VERSION 5.7 ;
  NOWIREEXTENSIONATPIN ON ;
  DIVIDERCHAR "/" ;
  BUSBITCHARS "[]" ;
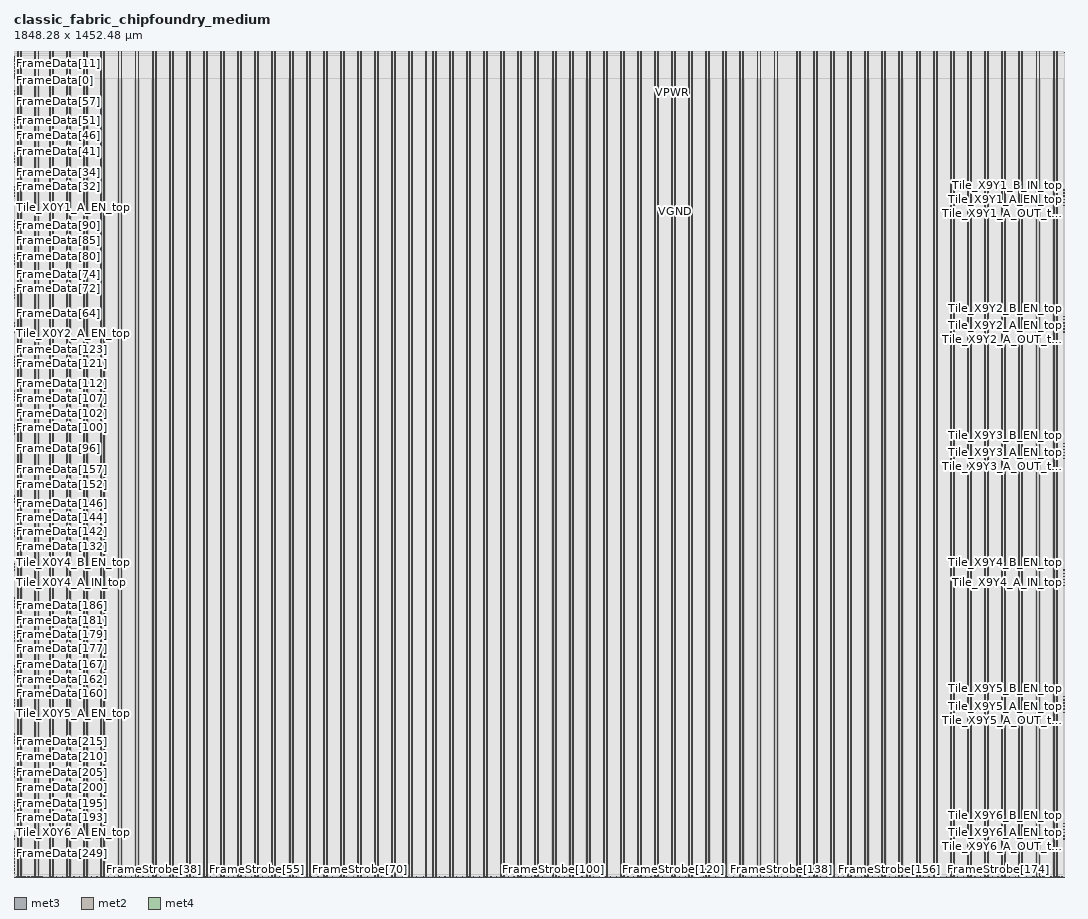
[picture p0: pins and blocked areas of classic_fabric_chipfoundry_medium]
MACRO classic_fabric_chipfoundry_medium
  CLASS BLOCK ;
  FOREIGN classic_fabric_chipfoundry_medium ;
  ORIGIN 0.000 0.000 ;
  SIZE 1848.280 BY 1452.480 ;
  PIN FrameData[0]
    DIRECTION INPUT ;
    USE SIGNAL ;
    ANTENNAGATEAREA 0.593700 ;
    ANTENNADIFFAREA 0.434700 ;
    PORT
      LAYER met3 ;
        RECT 0.000 1402.200 0.600 1402.800 ;
    END
  END FrameData[0]
  PIN FrameData[100]
    DIRECTION INPUT ;
    USE SIGNAL ;
    ANTENNAGATEAREA 0.795000 ;
    PORT
      LAYER met3 ;
        RECT 0.000 790.200 0.600 790.800 ;
    END
  END FrameData[100]
  PIN FrameData[101]
    DIRECTION INPUT ;
    USE SIGNAL ;
    ANTENNAGATEAREA 0.795000 ;
    PORT
      LAYER met3 ;
        RECT 0.000 795.640 0.600 796.240 ;
    END
  END FrameData[101]
  PIN FrameData[102]
    DIRECTION INPUT ;
    USE SIGNAL ;
    ANTENNAGATEAREA 0.795000 ;
    PORT
      LAYER met3 ;
        RECT 0.000 801.080 0.600 801.680 ;
    END
  END FrameData[102]
  PIN FrameData[103]
    DIRECTION INPUT ;
    USE SIGNAL ;
    ANTENNAGATEAREA 0.795000 ;
    PORT
      LAYER met3 ;
        RECT 0.000 806.520 0.600 807.120 ;
    END
  END FrameData[103]
  PIN FrameData[104]
    DIRECTION INPUT ;
    USE SIGNAL ;
    ANTENNAGATEAREA 0.795000 ;
    PORT
      LAYER met3 ;
        RECT 0.000 811.960 0.600 812.560 ;
    END
  END FrameData[104]
  PIN FrameData[105]
    DIRECTION INPUT ;
    USE SIGNAL ;
    ANTENNAGATEAREA 0.795000 ;
    PORT
      LAYER met3 ;
        RECT 0.000 817.400 0.600 818.000 ;
    END
  END FrameData[105]
  PIN FrameData[106]
    DIRECTION INPUT ;
    USE SIGNAL ;
    ANTENNAGATEAREA 0.795000 ;
    PORT
      LAYER met3 ;
        RECT 0.000 822.840 0.600 823.440 ;
    END
  END FrameData[106]
  PIN FrameData[107]
    DIRECTION INPUT ;
    USE SIGNAL ;
    ANTENNAGATEAREA 0.795000 ;
    PORT
      LAYER met3 ;
        RECT 0.000 828.280 0.600 828.880 ;
    END
  END FrameData[107]
  PIN FrameData[108]
    DIRECTION INPUT ;
    USE SIGNAL ;
    ANTENNAGATEAREA 0.795000 ;
    PORT
      LAYER met3 ;
        RECT 0.000 833.720 0.600 834.320 ;
    END
  END FrameData[108]
  PIN FrameData[109]
    DIRECTION INPUT ;
    USE SIGNAL ;
    ANTENNAGATEAREA 0.795000 ;
    PORT
      LAYER met3 ;
        RECT 0.000 839.160 0.600 839.760 ;
    END
  END FrameData[109]
  PIN FrameData[10]
    DIRECTION INPUT ;
    USE SIGNAL ;
    ANTENNAGATEAREA 0.159000 ;
    PORT
      LAYER met3 ;
        RECT 0.000 1415.800 0.600 1416.400 ;
    END
  END FrameData[10]
  PIN FrameData[110]
    DIRECTION INPUT ;
    USE SIGNAL ;
    ANTENNAGATEAREA 0.795000 ;
    PORT
      LAYER met3 ;
        RECT 0.000 844.600 0.600 845.200 ;
    END
  END FrameData[110]
  PIN FrameData[111]
    DIRECTION INPUT ;
    USE SIGNAL ;
    ANTENNAGATEAREA 0.795000 ;
    PORT
      LAYER met3 ;
        RECT 0.000 850.040 0.600 850.640 ;
    END
  END FrameData[111]
  PIN FrameData[112]
    DIRECTION INPUT ;
    USE SIGNAL ;
    ANTENNAGATEAREA 0.795000 ;
    PORT
      LAYER met3 ;
        RECT 0.000 855.480 0.600 856.080 ;
    END
  END FrameData[112]
  PIN FrameData[113]
    DIRECTION INPUT ;
    USE SIGNAL ;
    ANTENNAGATEAREA 0.795000 ;
    PORT
      LAYER met3 ;
        RECT 0.000 860.920 0.600 861.520 ;
    END
  END FrameData[113]
  PIN FrameData[114]
    DIRECTION INPUT ;
    USE SIGNAL ;
    ANTENNAGATEAREA 1.664400 ;
    ANTENNADIFFAREA 0.869400 ;
    PORT
      LAYER met3 ;
        RECT 0.000 866.360 0.600 866.960 ;
    END
  END FrameData[114]
  PIN FrameData[115]
    DIRECTION INPUT ;
    USE SIGNAL ;
    ANTENNAGATEAREA 0.795000 ;
    PORT
      LAYER met3 ;
        RECT 0.000 871.800 0.600 872.400 ;
    END
  END FrameData[115]
  PIN FrameData[116]
    DIRECTION INPUT ;
    USE SIGNAL ;
    ANTENNAGATEAREA 0.795000 ;
    PORT
      LAYER met3 ;
        RECT 0.000 877.240 0.600 877.840 ;
    END
  END FrameData[116]
  PIN FrameData[117]
    DIRECTION INPUT ;
    USE SIGNAL ;
    ANTENNAGATEAREA 0.795000 ;
    PORT
      LAYER met3 ;
        RECT 0.000 882.680 0.600 883.280 ;
    END
  END FrameData[117]
  PIN FrameData[118]
    DIRECTION INPUT ;
    USE SIGNAL ;
    ANTENNAGATEAREA 1.229700 ;
    ANTENNADIFFAREA 0.434700 ;
    PORT
      LAYER met3 ;
        RECT 0.000 888.120 0.600 888.720 ;
    END
  END FrameData[118]
  PIN FrameData[119]
    DIRECTION INPUT ;
    USE SIGNAL ;
    ANTENNAGATEAREA 0.795000 ;
    PORT
      LAYER met3 ;
        RECT 0.000 893.560 0.600 894.160 ;
    END
  END FrameData[119]
  PIN FrameData[11]
    DIRECTION INPUT ;
    USE SIGNAL ;
    ANTENNAGATEAREA 0.159000 ;
    PORT
      LAYER met3 ;
        RECT 0.000 1417.160 0.600 1417.760 ;
    END
  END FrameData[11]
  PIN FrameData[120]
    DIRECTION INPUT ;
    USE SIGNAL ;
    ANTENNAGATEAREA 0.795000 ;
    PORT
      LAYER met3 ;
        RECT 0.000 899.000 0.600 899.600 ;
    END
  END FrameData[120]
  PIN FrameData[121]
    DIRECTION INPUT ;
    USE SIGNAL ;
    ANTENNAGATEAREA 0.795000 ;
    PORT
      LAYER met3 ;
        RECT 0.000 904.440 0.600 905.040 ;
    END
  END FrameData[121]
  PIN FrameData[122]
    DIRECTION INPUT ;
    USE SIGNAL ;
    ANTENNAGATEAREA 0.795000 ;
    PORT
      LAYER met3 ;
        RECT 0.000 909.880 0.600 910.480 ;
    END
  END FrameData[122]
  PIN FrameData[123]
    DIRECTION INPUT ;
    USE SIGNAL ;
    ANTENNAGATEAREA 1.229700 ;
    ANTENNADIFFAREA 0.434700 ;
    PORT
      LAYER met3 ;
        RECT 0.000 915.320 0.600 915.920 ;
    END
  END FrameData[123]
  PIN FrameData[124]
    DIRECTION INPUT ;
    USE SIGNAL ;
    ANTENNAGATEAREA 0.795000 ;
    PORT
      LAYER met3 ;
        RECT 0.000 920.760 0.600 921.360 ;
    END
  END FrameData[124]
  PIN FrameData[125]
    DIRECTION INPUT ;
    USE SIGNAL ;
    ANTENNAGATEAREA 0.795000 ;
    PORT
      LAYER met3 ;
        RECT 0.000 926.200 0.600 926.800 ;
    END
  END FrameData[125]
  PIN FrameData[126]
    DIRECTION INPUT ;
    USE SIGNAL ;
    ANTENNAGATEAREA 0.795000 ;
    PORT
      LAYER met3 ;
        RECT 0.000 931.640 0.600 932.240 ;
    END
  END FrameData[126]
  PIN FrameData[127]
    DIRECTION INPUT ;
    USE SIGNAL ;
    ANTENNAGATEAREA 0.795000 ;
    PORT
      LAYER met3 ;
        RECT 0.000 937.080 0.600 937.680 ;
    END
  END FrameData[127]
  PIN FrameData[128]
    DIRECTION INPUT ;
    USE SIGNAL ;
    ANTENNAGATEAREA 0.636000 ;
    PORT
      LAYER met3 ;
        RECT 0.000 545.400 0.600 546.000 ;
    END
  END FrameData[128]
  PIN FrameData[129]
    DIRECTION INPUT ;
    USE SIGNAL ;
    ANTENNAGATEAREA 0.636000 ;
    PORT
      LAYER met3 ;
        RECT 0.000 550.840 0.600 551.440 ;
    END
  END FrameData[129]
  PIN FrameData[12]
    DIRECTION INPUT ;
    USE SIGNAL ;
    ANTENNAGATEAREA 0.159000 ;
    PORT
      LAYER met3 ;
        RECT 0.000 1418.520 0.600 1419.120 ;
    END
  END FrameData[12]
  PIN FrameData[130]
    DIRECTION INPUT ;
    USE SIGNAL ;
    ANTENNAGATEAREA 0.795000 ;
    PORT
      LAYER met3 ;
        RECT 0.000 556.280 0.600 556.880 ;
    END
  END FrameData[130]
  PIN FrameData[131]
    DIRECTION INPUT ;
    USE SIGNAL ;
    ANTENNAGATEAREA 0.795000 ;
    PORT
      LAYER met3 ;
        RECT 0.000 561.720 0.600 562.320 ;
    END
  END FrameData[131]
  PIN FrameData[132]
    DIRECTION INPUT ;
    USE SIGNAL ;
    ANTENNAGATEAREA 0.795000 ;
    PORT
      LAYER met3 ;
        RECT 0.000 567.160 0.600 567.760 ;
    END
  END FrameData[132]
  PIN FrameData[133]
    DIRECTION INPUT ;
    USE SIGNAL ;
    ANTENNAGATEAREA 0.795000 ;
    PORT
      LAYER met3 ;
        RECT 0.000 572.600 0.600 573.200 ;
    END
  END FrameData[133]
  PIN FrameData[134]
    DIRECTION INPUT ;
    USE SIGNAL ;
    ANTENNAGATEAREA 0.795000 ;
    PORT
      LAYER met3 ;
        RECT 0.000 578.040 0.600 578.640 ;
    END
  END FrameData[134]
  PIN FrameData[135]
    DIRECTION INPUT ;
    USE SIGNAL ;
    ANTENNAGATEAREA 0.795000 ;
    PORT
      LAYER met3 ;
        RECT 0.000 583.480 0.600 584.080 ;
    END
  END FrameData[135]
  PIN FrameData[136]
    DIRECTION INPUT ;
    USE SIGNAL ;
    ANTENNAGATEAREA 0.795000 ;
    PORT
      LAYER met3 ;
        RECT 0.000 588.920 0.600 589.520 ;
    END
  END FrameData[136]
  PIN FrameData[137]
    DIRECTION INPUT ;
    USE SIGNAL ;
    ANTENNAGATEAREA 0.795000 ;
    PORT
      LAYER met3 ;
        RECT 0.000 594.360 0.600 594.960 ;
    END
  END FrameData[137]
  PIN FrameData[138]
    DIRECTION INPUT ;
    USE SIGNAL ;
    ANTENNAGATEAREA 0.795000 ;
    PORT
      LAYER met3 ;
        RECT 0.000 599.800 0.600 600.400 ;
    END
  END FrameData[138]
  PIN FrameData[139]
    DIRECTION INPUT ;
    USE SIGNAL ;
    ANTENNAGATEAREA 0.795000 ;
    PORT
      LAYER met3 ;
        RECT 0.000 605.240 0.600 605.840 ;
    END
  END FrameData[139]
  PIN FrameData[13]
    DIRECTION INPUT ;
    USE SIGNAL ;
    ANTENNAGATEAREA 0.593700 ;
    ANTENNADIFFAREA 0.434700 ;
    PORT
      LAYER met3 ;
        RECT 0.000 1419.880 0.600 1420.480 ;
    END
  END FrameData[13]
  PIN FrameData[140]
    DIRECTION INPUT ;
    USE SIGNAL ;
    ANTENNAGATEAREA 0.795000 ;
    PORT
      LAYER met3 ;
        RECT 0.000 610.680 0.600 611.280 ;
    END
  END FrameData[140]
  PIN FrameData[141]
    DIRECTION INPUT ;
    USE SIGNAL ;
    ANTENNAGATEAREA 0.795000 ;
    PORT
      LAYER met3 ;
        RECT 0.000 616.120 0.600 616.720 ;
    END
  END FrameData[141]
  PIN FrameData[142]
    DIRECTION INPUT ;
    USE SIGNAL ;
    ANTENNAGATEAREA 0.795000 ;
    PORT
      LAYER met3 ;
        RECT 0.000 621.560 0.600 622.160 ;
    END
  END FrameData[142]
  PIN FrameData[143]
    DIRECTION INPUT ;
    USE SIGNAL ;
    ANTENNAGATEAREA 0.795000 ;
    PORT
      LAYER met3 ;
        RECT 0.000 627.000 0.600 627.600 ;
    END
  END FrameData[143]
  PIN FrameData[144]
    DIRECTION INPUT ;
    USE SIGNAL ;
    ANTENNAGATEAREA 0.795000 ;
    PORT
      LAYER met3 ;
        RECT 0.000 632.440 0.600 633.040 ;
    END
  END FrameData[144]
  PIN FrameData[145]
    DIRECTION INPUT ;
    USE SIGNAL ;
    ANTENNAGATEAREA 0.795000 ;
    PORT
      LAYER met3 ;
        RECT 0.000 637.880 0.600 638.480 ;
    END
  END FrameData[145]
  PIN FrameData[146]
    DIRECTION INPUT ;
    USE SIGNAL ;
    ANTENNAGATEAREA 1.664400 ;
    ANTENNADIFFAREA 0.869400 ;
    PORT
      LAYER met3 ;
        RECT 0.000 643.320 0.600 643.920 ;
    END
  END FrameData[146]
  PIN FrameData[147]
    DIRECTION INPUT ;
    USE SIGNAL ;
    ANTENNAGATEAREA 0.795000 ;
    PORT
      LAYER met3 ;
        RECT 0.000 648.760 0.600 649.360 ;
    END
  END FrameData[147]
  PIN FrameData[148]
    DIRECTION INPUT ;
    USE SIGNAL ;
    ANTENNAGATEAREA 0.795000 ;
    PORT
      LAYER met3 ;
        RECT 0.000 654.200 0.600 654.800 ;
    END
  END FrameData[148]
  PIN FrameData[149]
    DIRECTION INPUT ;
    USE SIGNAL ;
    ANTENNAGATEAREA 0.795000 ;
    PORT
      LAYER met3 ;
        RECT 0.000 659.640 0.600 660.240 ;
    END
  END FrameData[149]
  PIN FrameData[14]
    DIRECTION INPUT ;
    USE SIGNAL ;
    ANTENNAGATEAREA 0.593700 ;
    ANTENNADIFFAREA 0.434700 ;
    PORT
      LAYER met3 ;
        RECT 0.000 1421.240 0.600 1421.840 ;
    END
  END FrameData[14]
  PIN FrameData[150]
    DIRECTION INPUT ;
    USE SIGNAL ;
    ANTENNAGATEAREA 1.229700 ;
    ANTENNADIFFAREA 0.434700 ;
    PORT
      LAYER met3 ;
        RECT 0.000 665.080 0.600 665.680 ;
    END
  END FrameData[150]
  PIN FrameData[151]
    DIRECTION INPUT ;
    USE SIGNAL ;
    ANTENNAGATEAREA 0.795000 ;
    PORT
      LAYER met3 ;
        RECT 0.000 670.520 0.600 671.120 ;
    END
  END FrameData[151]
  PIN FrameData[152]
    DIRECTION INPUT ;
    USE SIGNAL ;
    ANTENNAGATEAREA 0.795000 ;
    PORT
      LAYER met3 ;
        RECT 0.000 675.960 0.600 676.560 ;
    END
  END FrameData[152]
  PIN FrameData[153]
    DIRECTION INPUT ;
    USE SIGNAL ;
    ANTENNAGATEAREA 0.795000 ;
    PORT
      LAYER met3 ;
        RECT 0.000 681.400 0.600 682.000 ;
    END
  END FrameData[153]
  PIN FrameData[154]
    DIRECTION INPUT ;
    USE SIGNAL ;
    ANTENNAGATEAREA 0.795000 ;
    PORT
      LAYER met3 ;
        RECT 0.000 686.840 0.600 687.440 ;
    END
  END FrameData[154]
  PIN FrameData[155]
    DIRECTION INPUT ;
    USE SIGNAL ;
    ANTENNAGATEAREA 1.229700 ;
    ANTENNADIFFAREA 0.434700 ;
    PORT
      LAYER met3 ;
        RECT 0.000 692.280 0.600 692.880 ;
    END
  END FrameData[155]
  PIN FrameData[156]
    DIRECTION INPUT ;
    USE SIGNAL ;
    ANTENNAGATEAREA 0.795000 ;
    PORT
      LAYER met3 ;
        RECT 0.000 697.720 0.600 698.320 ;
    END
  END FrameData[156]
  PIN FrameData[157]
    DIRECTION INPUT ;
    USE SIGNAL ;
    ANTENNAGATEAREA 0.795000 ;
    PORT
      LAYER met3 ;
        RECT 0.000 703.160 0.600 703.760 ;
    END
  END FrameData[157]
  PIN FrameData[158]
    DIRECTION INPUT ;
    USE SIGNAL ;
    ANTENNAGATEAREA 0.795000 ;
    PORT
      LAYER met3 ;
        RECT 0.000 708.600 0.600 709.200 ;
    END
  END FrameData[158]
  PIN FrameData[159]
    DIRECTION INPUT ;
    USE SIGNAL ;
    ANTENNAGATEAREA 0.795000 ;
    PORT
      LAYER met3 ;
        RECT 0.000 714.040 0.600 714.640 ;
    END
  END FrameData[159]
  PIN FrameData[15]
    DIRECTION INPUT ;
    USE SIGNAL ;
    ANTENNAGATEAREA 0.159000 ;
    PORT
      LAYER met3 ;
        RECT 0.000 1422.600 0.600 1423.200 ;
    END
  END FrameData[15]
  PIN FrameData[160]
    DIRECTION INPUT ;
    USE SIGNAL ;
    ANTENNAGATEAREA 0.636000 ;
    PORT
      LAYER met3 ;
        RECT 0.000 322.360 0.600 322.960 ;
    END
  END FrameData[160]
  PIN FrameData[161]
    DIRECTION INPUT ;
    USE SIGNAL ;
    ANTENNAGATEAREA 0.636000 ;
    PORT
      LAYER met3 ;
        RECT 0.000 327.800 0.600 328.400 ;
    END
  END FrameData[161]
  PIN FrameData[162]
    DIRECTION INPUT ;
    USE SIGNAL ;
    ANTENNAGATEAREA 0.795000 ;
    PORT
      LAYER met3 ;
        RECT 0.000 333.240 0.600 333.840 ;
    END
  END FrameData[162]
  PIN FrameData[163]
    DIRECTION INPUT ;
    USE SIGNAL ;
    ANTENNAGATEAREA 0.795000 ;
    PORT
      LAYER met3 ;
        RECT 0.000 338.680 0.600 339.280 ;
    END
  END FrameData[163]
  PIN FrameData[164]
    DIRECTION INPUT ;
    USE SIGNAL ;
    ANTENNAGATEAREA 0.795000 ;
    PORT
      LAYER met3 ;
        RECT 0.000 344.120 0.600 344.720 ;
    END
  END FrameData[164]
  PIN FrameData[165]
    DIRECTION INPUT ;
    USE SIGNAL ;
    ANTENNAGATEAREA 0.795000 ;
    PORT
      LAYER met3 ;
        RECT 0.000 349.560 0.600 350.160 ;
    END
  END FrameData[165]
  PIN FrameData[166]
    DIRECTION INPUT ;
    USE SIGNAL ;
    ANTENNAGATEAREA 0.795000 ;
    PORT
      LAYER met3 ;
        RECT 0.000 355.000 0.600 355.600 ;
    END
  END FrameData[166]
  PIN FrameData[167]
    DIRECTION INPUT ;
    USE SIGNAL ;
    ANTENNAGATEAREA 0.795000 ;
    PORT
      LAYER met3 ;
        RECT 0.000 360.440 0.600 361.040 ;
    END
  END FrameData[167]
  PIN FrameData[168]
    DIRECTION INPUT ;
    USE SIGNAL ;
    ANTENNAGATEAREA 0.795000 ;
    PORT
      LAYER met3 ;
        RECT 0.000 365.880 0.600 366.480 ;
    END
  END FrameData[168]
  PIN FrameData[169]
    DIRECTION INPUT ;
    USE SIGNAL ;
    ANTENNAGATEAREA 0.795000 ;
    PORT
      LAYER met3 ;
        RECT 0.000 371.320 0.600 371.920 ;
    END
  END FrameData[169]
  PIN FrameData[16]
    DIRECTION INPUT ;
    USE SIGNAL ;
    ANTENNAGATEAREA 0.593700 ;
    ANTENNADIFFAREA 0.434700 ;
    PORT
      LAYER met3 ;
        RECT 0.000 1423.960 0.600 1424.560 ;
    END
  END FrameData[16]
  PIN FrameData[170]
    DIRECTION INPUT ;
    USE SIGNAL ;
    ANTENNAGATEAREA 0.795000 ;
    PORT
      LAYER met3 ;
        RECT 0.000 376.760 0.600 377.360 ;
    END
  END FrameData[170]
  PIN FrameData[171]
    DIRECTION INPUT ;
    USE SIGNAL ;
    ANTENNAGATEAREA 0.795000 ;
    PORT
      LAYER met3 ;
        RECT 0.000 382.200 0.600 382.800 ;
    END
  END FrameData[171]
  PIN FrameData[172]
    DIRECTION INPUT ;
    USE SIGNAL ;
    ANTENNAGATEAREA 0.795000 ;
    PORT
      LAYER met3 ;
        RECT 0.000 387.640 0.600 388.240 ;
    END
  END FrameData[172]
  PIN FrameData[173]
    DIRECTION INPUT ;
    USE SIGNAL ;
    ANTENNAGATEAREA 0.795000 ;
    PORT
      LAYER met3 ;
        RECT 0.000 393.080 0.600 393.680 ;
    END
  END FrameData[173]
  PIN FrameData[174]
    DIRECTION INPUT ;
    USE SIGNAL ;
    ANTENNAGATEAREA 0.795000 ;
    PORT
      LAYER met3 ;
        RECT 0.000 398.520 0.600 399.120 ;
    END
  END FrameData[174]
  PIN FrameData[175]
    DIRECTION INPUT ;
    USE SIGNAL ;
    ANTENNAGATEAREA 0.795000 ;
    PORT
      LAYER met3 ;
        RECT 0.000 403.960 0.600 404.560 ;
    END
  END FrameData[175]
  PIN FrameData[176]
    DIRECTION INPUT ;
    USE SIGNAL ;
    ANTENNAGATEAREA 0.795000 ;
    PORT
      LAYER met3 ;
        RECT 0.000 409.400 0.600 410.000 ;
    END
  END FrameData[176]
  PIN FrameData[177]
    DIRECTION INPUT ;
    USE SIGNAL ;
    ANTENNAGATEAREA 0.795000 ;
    PORT
      LAYER met3 ;
        RECT 0.000 414.840 0.600 415.440 ;
    END
  END FrameData[177]
  PIN FrameData[178]
    DIRECTION INPUT ;
    USE SIGNAL ;
    ANTENNAGATEAREA 1.664400 ;
    ANTENNADIFFAREA 0.869400 ;
    PORT
      LAYER met3 ;
        RECT 0.000 420.280 0.600 420.880 ;
    END
  END FrameData[178]
  PIN FrameData[179]
    DIRECTION INPUT ;
    USE SIGNAL ;
    ANTENNAGATEAREA 0.795000 ;
    PORT
      LAYER met3 ;
        RECT 0.000 425.720 0.600 426.320 ;
    END
  END FrameData[179]
  PIN FrameData[17]
    DIRECTION INPUT ;
    USE SIGNAL ;
    ANTENNAGATEAREA 0.593700 ;
    ANTENNADIFFAREA 0.434700 ;
    PORT
      LAYER met3 ;
        RECT 0.000 1425.320 0.600 1425.920 ;
    END
  END FrameData[17]
  PIN FrameData[180]
    DIRECTION INPUT ;
    USE SIGNAL ;
    ANTENNAGATEAREA 0.795000 ;
    PORT
      LAYER met3 ;
        RECT 0.000 431.160 0.600 431.760 ;
    END
  END FrameData[180]
  PIN FrameData[181]
    DIRECTION INPUT ;
    USE SIGNAL ;
    ANTENNAGATEAREA 0.795000 ;
    PORT
      LAYER met3 ;
        RECT 0.000 436.600 0.600 437.200 ;
    END
  END FrameData[181]
  PIN FrameData[182]
    DIRECTION INPUT ;
    USE SIGNAL ;
    ANTENNAGATEAREA 1.229700 ;
    ANTENNADIFFAREA 0.434700 ;
    PORT
      LAYER met3 ;
        RECT 0.000 442.040 0.600 442.640 ;
    END
  END FrameData[182]
  PIN FrameData[183]
    DIRECTION INPUT ;
    USE SIGNAL ;
    ANTENNAGATEAREA 0.795000 ;
    PORT
      LAYER met3 ;
        RECT 0.000 447.480 0.600 448.080 ;
    END
  END FrameData[183]
  PIN FrameData[184]
    DIRECTION INPUT ;
    USE SIGNAL ;
    ANTENNAGATEAREA 0.795000 ;
    PORT
      LAYER met3 ;
        RECT 0.000 452.920 0.600 453.520 ;
    END
  END FrameData[184]
  PIN FrameData[185]
    DIRECTION INPUT ;
    USE SIGNAL ;
    ANTENNAGATEAREA 0.795000 ;
    PORT
      LAYER met3 ;
        RECT 0.000 458.360 0.600 458.960 ;
    END
  END FrameData[185]
  PIN FrameData[186]
    DIRECTION INPUT ;
    USE SIGNAL ;
    ANTENNAGATEAREA 0.795000 ;
    PORT
      LAYER met3 ;
        RECT 0.000 463.800 0.600 464.400 ;
    END
  END FrameData[186]
  PIN FrameData[187]
    DIRECTION INPUT ;
    USE SIGNAL ;
    ANTENNAGATEAREA 1.229700 ;
    ANTENNADIFFAREA 0.434700 ;
    PORT
      LAYER met3 ;
        RECT 0.000 469.240 0.600 469.840 ;
    END
  END FrameData[187]
  PIN FrameData[188]
    DIRECTION INPUT ;
    USE SIGNAL ;
    ANTENNAGATEAREA 0.795000 ;
    PORT
      LAYER met3 ;
        RECT 0.000 474.680 0.600 475.280 ;
    END
  END FrameData[188]
  PIN FrameData[189]
    DIRECTION INPUT ;
    USE SIGNAL ;
    ANTENNAGATEAREA 0.795000 ;
    PORT
      LAYER met3 ;
        RECT 0.000 480.120 0.600 480.720 ;
    END
  END FrameData[189]
  PIN FrameData[18]
    DIRECTION INPUT ;
    USE SIGNAL ;
    ANTENNAGATEAREA 0.159000 ;
    PORT
      LAYER met3 ;
        RECT 0.000 1426.680 0.600 1427.280 ;
    END
  END FrameData[18]
  PIN FrameData[190]
    DIRECTION INPUT ;
    USE SIGNAL ;
    ANTENNAGATEAREA 0.795000 ;
    PORT
      LAYER met3 ;
        RECT 0.000 485.560 0.600 486.160 ;
    END
  END FrameData[190]
  PIN FrameData[191]
    DIRECTION INPUT ;
    USE SIGNAL ;
    ANTENNAGATEAREA 0.795000 ;
    PORT
      LAYER met3 ;
        RECT 0.000 491.000 0.600 491.600 ;
    END
  END FrameData[191]
  PIN FrameData[192]
    DIRECTION INPUT ;
    USE SIGNAL ;
    ANTENNAGATEAREA 0.636000 ;
    PORT
      LAYER met3 ;
        RECT 0.000 99.320 0.600 99.920 ;
    END
  END FrameData[192]
  PIN FrameData[193]
    DIRECTION INPUT ;
    USE SIGNAL ;
    ANTENNAGATEAREA 0.636000 ;
    PORT
      LAYER met3 ;
        RECT 0.000 104.760 0.600 105.360 ;
    END
  END FrameData[193]
  PIN FrameData[194]
    DIRECTION INPUT ;
    USE SIGNAL ;
    ANTENNAGATEAREA 0.795000 ;
    PORT
      LAYER met3 ;
        RECT 0.000 110.200 0.600 110.800 ;
    END
  END FrameData[194]
  PIN FrameData[195]
    DIRECTION INPUT ;
    USE SIGNAL ;
    ANTENNAGATEAREA 0.795000 ;
    PORT
      LAYER met3 ;
        RECT 0.000 115.640 0.600 116.240 ;
    END
  END FrameData[195]
  PIN FrameData[196]
    DIRECTION INPUT ;
    USE SIGNAL ;
    ANTENNAGATEAREA 0.795000 ;
    PORT
      LAYER met3 ;
        RECT 0.000 121.080 0.600 121.680 ;
    END
  END FrameData[196]
  PIN FrameData[197]
    DIRECTION INPUT ;
    USE SIGNAL ;
    ANTENNAGATEAREA 0.795000 ;
    PORT
      LAYER met3 ;
        RECT 0.000 126.520 0.600 127.120 ;
    END
  END FrameData[197]
  PIN FrameData[198]
    DIRECTION INPUT ;
    USE SIGNAL ;
    ANTENNAGATEAREA 0.795000 ;
    PORT
      LAYER met3 ;
        RECT 0.000 131.960 0.600 132.560 ;
    END
  END FrameData[198]
  PIN FrameData[199]
    DIRECTION INPUT ;
    USE SIGNAL ;
    ANTENNAGATEAREA 0.795000 ;
    PORT
      LAYER met3 ;
        RECT 0.000 137.400 0.600 138.000 ;
    END
  END FrameData[199]
  PIN FrameData[19]
    DIRECTION INPUT ;
    USE SIGNAL ;
    ANTENNAGATEAREA 0.593700 ;
    ANTENNADIFFAREA 0.434700 ;
    PORT
      LAYER met3 ;
        RECT 0.000 1428.040 0.600 1428.640 ;
    END
  END FrameData[19]
  PIN FrameData[1]
    DIRECTION INPUT ;
    USE SIGNAL ;
    ANTENNAGATEAREA 0.593700 ;
    ANTENNADIFFAREA 0.434700 ;
    PORT
      LAYER met3 ;
        RECT 0.000 1403.560 0.600 1404.160 ;
    END
  END FrameData[1]
  PIN FrameData[200]
    DIRECTION INPUT ;
    USE SIGNAL ;
    ANTENNAGATEAREA 0.795000 ;
    PORT
      LAYER met3 ;
        RECT 0.000 142.840 0.600 143.440 ;
    END
  END FrameData[200]
  PIN FrameData[201]
    DIRECTION INPUT ;
    USE SIGNAL ;
    ANTENNAGATEAREA 0.795000 ;
    PORT
      LAYER met3 ;
        RECT 0.000 148.280 0.600 148.880 ;
    END
  END FrameData[201]
  PIN FrameData[202]
    DIRECTION INPUT ;
    USE SIGNAL ;
    ANTENNAGATEAREA 0.795000 ;
    PORT
      LAYER met3 ;
        RECT 0.000 153.720 0.600 154.320 ;
    END
  END FrameData[202]
  PIN FrameData[203]
    DIRECTION INPUT ;
    USE SIGNAL ;
    ANTENNAGATEAREA 0.795000 ;
    PORT
      LAYER met3 ;
        RECT 0.000 159.160 0.600 159.760 ;
    END
  END FrameData[203]
  PIN FrameData[204]
    DIRECTION INPUT ;
    USE SIGNAL ;
    ANTENNAGATEAREA 0.795000 ;
    PORT
      LAYER met3 ;
        RECT 0.000 164.600 0.600 165.200 ;
    END
  END FrameData[204]
  PIN FrameData[205]
    DIRECTION INPUT ;
    USE SIGNAL ;
    ANTENNAGATEAREA 0.795000 ;
    PORT
      LAYER met3 ;
        RECT 0.000 170.040 0.600 170.640 ;
    END
  END FrameData[205]
  PIN FrameData[206]
    DIRECTION INPUT ;
    USE SIGNAL ;
    ANTENNAGATEAREA 0.795000 ;
    PORT
      LAYER met3 ;
        RECT 0.000 175.480 0.600 176.080 ;
    END
  END FrameData[206]
  PIN FrameData[207]
    DIRECTION INPUT ;
    USE SIGNAL ;
    ANTENNAGATEAREA 0.795000 ;
    PORT
      LAYER met3 ;
        RECT 0.000 180.920 0.600 181.520 ;
    END
  END FrameData[207]
  PIN FrameData[208]
    DIRECTION INPUT ;
    USE SIGNAL ;
    ANTENNAGATEAREA 0.795000 ;
    PORT
      LAYER met3 ;
        RECT 0.000 186.360 0.600 186.960 ;
    END
  END FrameData[208]
  PIN FrameData[209]
    DIRECTION INPUT ;
    USE SIGNAL ;
    ANTENNAGATEAREA 0.795000 ;
    PORT
      LAYER met3 ;
        RECT 0.000 191.800 0.600 192.400 ;
    END
  END FrameData[209]
  PIN FrameData[20]
    DIRECTION INPUT ;
    USE SIGNAL ;
    ANTENNAGATEAREA 0.593700 ;
    ANTENNADIFFAREA 0.434700 ;
    PORT
      LAYER met3 ;
        RECT 0.000 1429.400 0.600 1430.000 ;
    END
  END FrameData[20]
  PIN FrameData[210]
    DIRECTION INPUT ;
    USE SIGNAL ;
    ANTENNAGATEAREA 1.664400 ;
    ANTENNADIFFAREA 0.869400 ;
    PORT
      LAYER met3 ;
        RECT 0.000 197.240 0.600 197.840 ;
    END
  END FrameData[210]
  PIN FrameData[211]
    DIRECTION INPUT ;
    USE SIGNAL ;
    ANTENNAGATEAREA 0.795000 ;
    PORT
      LAYER met3 ;
        RECT 0.000 202.680 0.600 203.280 ;
    END
  END FrameData[211]
  PIN FrameData[212]
    DIRECTION INPUT ;
    USE SIGNAL ;
    ANTENNAGATEAREA 0.795000 ;
    PORT
      LAYER met3 ;
        RECT 0.000 208.120 0.600 208.720 ;
    END
  END FrameData[212]
  PIN FrameData[213]
    DIRECTION INPUT ;
    USE SIGNAL ;
    ANTENNAGATEAREA 0.795000 ;
    PORT
      LAYER met3 ;
        RECT 0.000 213.560 0.600 214.160 ;
    END
  END FrameData[213]
  PIN FrameData[214]
    DIRECTION INPUT ;
    USE SIGNAL ;
    ANTENNAGATEAREA 1.229700 ;
    ANTENNADIFFAREA 0.434700 ;
    PORT
      LAYER met3 ;
        RECT 0.000 219.000 0.600 219.600 ;
    END
  END FrameData[214]
  PIN FrameData[215]
    DIRECTION INPUT ;
    USE SIGNAL ;
    ANTENNAGATEAREA 0.795000 ;
    PORT
      LAYER met3 ;
        RECT 0.000 224.440 0.600 225.040 ;
    END
  END FrameData[215]
  PIN FrameData[216]
    DIRECTION INPUT ;
    USE SIGNAL ;
    ANTENNAGATEAREA 0.795000 ;
    PORT
      LAYER met3 ;
        RECT 0.000 229.880 0.600 230.480 ;
    END
  END FrameData[216]
  PIN FrameData[217]
    DIRECTION INPUT ;
    USE SIGNAL ;
    ANTENNAGATEAREA 0.795000 ;
    PORT
      LAYER met3 ;
        RECT 0.000 235.320 0.600 235.920 ;
    END
  END FrameData[217]
  PIN FrameData[218]
    DIRECTION INPUT ;
    USE SIGNAL ;
    ANTENNAGATEAREA 0.795000 ;
    PORT
      LAYER met3 ;
        RECT 0.000 240.760 0.600 241.360 ;
    END
  END FrameData[218]
  PIN FrameData[219]
    DIRECTION INPUT ;
    USE SIGNAL ;
    ANTENNAGATEAREA 1.229700 ;
    ANTENNADIFFAREA 0.434700 ;
    PORT
      LAYER met3 ;
        RECT 0.000 246.200 0.600 246.800 ;
    END
  END FrameData[219]
  PIN FrameData[21]
    DIRECTION INPUT ;
    USE SIGNAL ;
    ANTENNAGATEAREA 0.159000 ;
    PORT
      LAYER met3 ;
        RECT 0.000 1430.760 0.600 1431.360 ;
    END
  END FrameData[21]
  PIN FrameData[220]
    DIRECTION INPUT ;
    USE SIGNAL ;
    ANTENNAGATEAREA 0.795000 ;
    PORT
      LAYER met3 ;
        RECT 0.000 251.640 0.600 252.240 ;
    END
  END FrameData[220]
  PIN FrameData[221]
    DIRECTION INPUT ;
    USE SIGNAL ;
    ANTENNAGATEAREA 0.795000 ;
    PORT
      LAYER met3 ;
        RECT 0.000 257.080 0.600 257.680 ;
    END
  END FrameData[221]
  PIN FrameData[222]
    DIRECTION INPUT ;
    USE SIGNAL ;
    ANTENNAGATEAREA 0.795000 ;
    PORT
      LAYER met3 ;
        RECT 0.000 262.520 0.600 263.120 ;
    END
  END FrameData[222]
  PIN FrameData[223]
    DIRECTION INPUT ;
    USE SIGNAL ;
    ANTENNAGATEAREA 0.795000 ;
    PORT
      LAYER met3 ;
        RECT 0.000 267.960 0.600 268.560 ;
    END
  END FrameData[223]
  PIN FrameData[224]
    DIRECTION INPUT ;
    USE SIGNAL ;
    ANTENNAGATEAREA 0.159000 ;
    PORT
      LAYER met3 ;
        RECT 0.000 6.840 0.600 7.440 ;
    END
  END FrameData[224]
  PIN FrameData[225]
    DIRECTION INPUT ;
    USE SIGNAL ;
    ANTENNAGATEAREA 0.159000 ;
    PORT
      LAYER met3 ;
        RECT 0.000 8.200 0.600 8.800 ;
    END
  END FrameData[225]
  PIN FrameData[226]
    DIRECTION INPUT ;
    USE SIGNAL ;
    ANTENNAGATEAREA 0.159000 ;
    PORT
      LAYER met3 ;
        RECT 0.000 9.560 0.600 10.160 ;
    END
  END FrameData[226]
  PIN FrameData[227]
    DIRECTION INPUT ;
    USE SIGNAL ;
    ANTENNAGATEAREA 0.593700 ;
    ANTENNADIFFAREA 0.434700 ;
    PORT
      LAYER met3 ;
        RECT 0.000 10.920 0.600 11.520 ;
    END
  END FrameData[227]
  PIN FrameData[228]
    DIRECTION INPUT ;
    USE SIGNAL ;
    ANTENNAGATEAREA 0.593700 ;
    ANTENNADIFFAREA 0.434700 ;
    PORT
      LAYER met3 ;
        RECT 0.000 12.280 0.600 12.880 ;
    END
  END FrameData[228]
  PIN FrameData[229]
    DIRECTION INPUT ;
    USE SIGNAL ;
    ANTENNAGATEAREA 0.593700 ;
    ANTENNADIFFAREA 0.434700 ;
    PORT
      LAYER met3 ;
        RECT 0.000 13.640 0.600 14.240 ;
    END
  END FrameData[229]
  PIN FrameData[22]
    DIRECTION INPUT ;
    USE SIGNAL ;
    ANTENNAGATEAREA 0.159000 ;
    PORT
      LAYER met3 ;
        RECT 0.000 1432.120 0.600 1432.720 ;
    END
  END FrameData[22]
  PIN FrameData[230]
    DIRECTION INPUT ;
    USE SIGNAL ;
    ANTENNAGATEAREA 0.159000 ;
    PORT
      LAYER met3 ;
        RECT 0.000 15.000 0.600 15.600 ;
    END
  END FrameData[230]
  PIN FrameData[231]
    DIRECTION INPUT ;
    USE SIGNAL ;
    ANTENNAGATEAREA 0.159000 ;
    PORT
      LAYER met3 ;
        RECT 0.000 16.360 0.600 16.960 ;
    END
  END FrameData[231]
  PIN FrameData[232]
    DIRECTION INPUT ;
    USE SIGNAL ;
    ANTENNAGATEAREA 0.593700 ;
    ANTENNADIFFAREA 0.434700 ;
    PORT
      LAYER met3 ;
        RECT 0.000 17.720 0.600 18.320 ;
    END
  END FrameData[232]
  PIN FrameData[233]
    DIRECTION INPUT ;
    USE SIGNAL ;
    ANTENNAGATEAREA 0.593700 ;
    ANTENNADIFFAREA 0.434700 ;
    PORT
      LAYER met3 ;
        RECT 0.000 19.080 0.600 19.680 ;
    END
  END FrameData[233]
  PIN FrameData[234]
    DIRECTION INPUT ;
    USE SIGNAL ;
    ANTENNAGATEAREA 0.159000 ;
    PORT
      LAYER met3 ;
        RECT 0.000 20.440 0.600 21.040 ;
    END
  END FrameData[234]
  PIN FrameData[235]
    DIRECTION INPUT ;
    USE SIGNAL ;
    ANTENNAGATEAREA 0.593700 ;
    ANTENNADIFFAREA 0.434700 ;
    PORT
      LAYER met3 ;
        RECT 0.000 21.800 0.600 22.400 ;
    END
  END FrameData[235]
  PIN FrameData[236]
    DIRECTION INPUT ;
    USE SIGNAL ;
    ANTENNAGATEAREA 0.318000 ;
    PORT
      LAYER met3 ;
        RECT 0.000 23.160 0.600 23.760 ;
    END
  END FrameData[236]
  PIN FrameData[237]
    DIRECTION INPUT ;
    USE SIGNAL ;
    ANTENNAGATEAREA 0.318000 ;
    PORT
      LAYER met3 ;
        RECT 0.000 24.520 0.600 25.120 ;
    END
  END FrameData[237]
  PIN FrameData[238]
    DIRECTION INPUT ;
    USE SIGNAL ;
    ANTENNAGATEAREA 0.318000 ;
    PORT
      LAYER met3 ;
        RECT 0.000 25.880 0.600 26.480 ;
    END
  END FrameData[238]
  PIN FrameData[239]
    DIRECTION INPUT ;
    USE SIGNAL ;
    ANTENNAGATEAREA 0.318000 ;
    PORT
      LAYER met3 ;
        RECT 0.000 27.240 0.600 27.840 ;
    END
  END FrameData[239]
  PIN FrameData[23]
    DIRECTION INPUT ;
    USE SIGNAL ;
    ANTENNAGATEAREA 0.159000 ;
    PORT
      LAYER met3 ;
        RECT 0.000 1433.480 0.600 1434.080 ;
    END
  END FrameData[23]
  PIN FrameData[240]
    DIRECTION INPUT ;
    USE SIGNAL ;
    ANTENNAGATEAREA 0.318000 ;
    PORT
      LAYER met3 ;
        RECT 0.000 28.600 0.600 29.200 ;
    END
  END FrameData[240]
  PIN FrameData[241]
    DIRECTION INPUT ;
    USE SIGNAL ;
    ANTENNAGATEAREA 0.318000 ;
    PORT
      LAYER met3 ;
        RECT 0.000 29.960 0.600 30.560 ;
    END
  END FrameData[241]
  PIN FrameData[242]
    DIRECTION INPUT ;
    USE SIGNAL ;
    ANTENNAGATEAREA 0.318000 ;
    PORT
      LAYER met3 ;
        RECT 0.000 31.320 0.600 31.920 ;
    END
  END FrameData[242]
  PIN FrameData[243]
    DIRECTION INPUT ;
    USE SIGNAL ;
    ANTENNAGATEAREA 0.318000 ;
    PORT
      LAYER met3 ;
        RECT 0.000 32.680 0.600 33.280 ;
    END
  END FrameData[243]
  PIN FrameData[244]
    DIRECTION INPUT ;
    USE SIGNAL ;
    ANTENNAGATEAREA 0.318000 ;
    PORT
      LAYER met3 ;
        RECT 0.000 34.040 0.600 34.640 ;
    END
  END FrameData[244]
  PIN FrameData[245]
    DIRECTION INPUT ;
    USE SIGNAL ;
    ANTENNAGATEAREA 0.318000 ;
    PORT
      LAYER met3 ;
        RECT 0.000 35.400 0.600 36.000 ;
    END
  END FrameData[245]
  PIN FrameData[246]
    DIRECTION INPUT ;
    USE SIGNAL ;
    ANTENNAGATEAREA 0.318000 ;
    PORT
      LAYER met3 ;
        RECT 0.000 36.760 0.600 37.360 ;
    END
  END FrameData[246]
  PIN FrameData[247]
    DIRECTION INPUT ;
    USE SIGNAL ;
    ANTENNAGATEAREA 0.318000 ;
    PORT
      LAYER met3 ;
        RECT 0.000 38.120 0.600 38.720 ;
    END
  END FrameData[247]
  PIN FrameData[248]
    DIRECTION INPUT ;
    USE SIGNAL ;
    ANTENNAGATEAREA 0.318000 ;
    PORT
      LAYER met3 ;
        RECT 0.000 39.480 0.600 40.080 ;
    END
  END FrameData[248]
  PIN FrameData[249]
    DIRECTION INPUT ;
    USE SIGNAL ;
    ANTENNAGATEAREA 0.318000 ;
    PORT
      LAYER met3 ;
        RECT 0.000 40.840 0.600 41.440 ;
    END
  END FrameData[249]
  PIN FrameData[24]
    DIRECTION INPUT ;
    USE SIGNAL ;
    ANTENNAGATEAREA 0.159000 ;
    PORT
      LAYER met3 ;
        RECT 0.000 1434.840 0.600 1435.440 ;
    END
  END FrameData[24]
  PIN FrameData[250]
    DIRECTION INPUT ;
    USE SIGNAL ;
    ANTENNAGATEAREA 0.318000 ;
    PORT
      LAYER met3 ;
        RECT 0.000 42.200 0.600 42.800 ;
    END
  END FrameData[250]
  PIN FrameData[251]
    DIRECTION INPUT ;
    USE SIGNAL ;
    ANTENNAGATEAREA 0.318000 ;
    PORT
      LAYER met3 ;
        RECT 0.000 43.560 0.600 44.160 ;
    END
  END FrameData[251]
  PIN FrameData[252]
    DIRECTION INPUT ;
    USE SIGNAL ;
    ANTENNAGATEAREA 0.318000 ;
    PORT
      LAYER met3 ;
        RECT 0.000 44.920 0.600 45.520 ;
    END
  END FrameData[252]
  PIN FrameData[253]
    DIRECTION INPUT ;
    USE SIGNAL ;
    ANTENNAGATEAREA 0.318000 ;
    PORT
      LAYER met3 ;
        RECT 0.000 46.280 0.600 46.880 ;
    END
  END FrameData[253]
  PIN FrameData[254]
    DIRECTION INPUT ;
    USE SIGNAL ;
    ANTENNAGATEAREA 0.318000 ;
    PORT
      LAYER met3 ;
        RECT 0.000 47.640 0.600 48.240 ;
    END
  END FrameData[254]
  PIN FrameData[255]
    DIRECTION INPUT ;
    USE SIGNAL ;
    ANTENNAGATEAREA 0.318000 ;
    PORT
      LAYER met3 ;
        RECT 0.000 49.000 0.600 49.600 ;
    END
  END FrameData[255]
  PIN FrameData[25]
    DIRECTION INPUT ;
    USE SIGNAL ;
    ANTENNAGATEAREA 0.159000 ;
    PORT
      LAYER met3 ;
        RECT 0.000 1436.200 0.600 1436.800 ;
    END
  END FrameData[25]
  PIN FrameData[26]
    DIRECTION INPUT ;
    USE SIGNAL ;
    ANTENNAGATEAREA 0.159000 ;
    PORT
      LAYER met3 ;
        RECT 0.000 1437.560 0.600 1438.160 ;
    END
  END FrameData[26]
  PIN FrameData[27]
    DIRECTION INPUT ;
    USE SIGNAL ;
    ANTENNAGATEAREA 0.159000 ;
    PORT
      LAYER met3 ;
        RECT 0.000 1438.920 0.600 1439.520 ;
    END
  END FrameData[27]
  PIN FrameData[28]
    DIRECTION INPUT ;
    USE SIGNAL ;
    ANTENNAGATEAREA 0.318000 ;
    PORT
      LAYER met3 ;
        RECT 0.000 1440.280 0.600 1440.880 ;
    END
  END FrameData[28]
  PIN FrameData[29]
    DIRECTION INPUT ;
    USE SIGNAL ;
    ANTENNAGATEAREA 0.318000 ;
    PORT
      LAYER met3 ;
        RECT 0.000 1441.640 0.600 1442.240 ;
    END
  END FrameData[29]
  PIN FrameData[2]
    DIRECTION INPUT ;
    USE SIGNAL ;
    ANTENNAGATEAREA 0.593700 ;
    ANTENNADIFFAREA 0.434700 ;
    PORT
      LAYER met3 ;
        RECT 0.000 1404.920 0.600 1405.520 ;
    END
  END FrameData[2]
  PIN FrameData[30]
    DIRECTION INPUT ;
    USE SIGNAL ;
    ANTENNAGATEAREA 0.318000 ;
    PORT
      LAYER met3 ;
        RECT 0.000 1443.000 0.600 1443.600 ;
    END
  END FrameData[30]
  PIN FrameData[31]
    DIRECTION INPUT ;
    USE SIGNAL ;
    ANTENNAGATEAREA 0.318000 ;
    PORT
      LAYER met3 ;
        RECT 0.000 1444.360 0.600 1444.960 ;
    END
  END FrameData[31]
  PIN FrameData[32]
    DIRECTION INPUT ;
    USE SIGNAL ;
    ANTENNAGATEAREA 0.636000 ;
    PORT
      LAYER met3 ;
        RECT 0.000 1214.520 0.600 1215.120 ;
    END
  END FrameData[32]
  PIN FrameData[33]
    DIRECTION INPUT ;
    USE SIGNAL ;
    ANTENNAGATEAREA 0.636000 ;
    PORT
      LAYER met3 ;
        RECT 0.000 1219.960 0.600 1220.560 ;
    END
  END FrameData[33]
  PIN FrameData[34]
    DIRECTION INPUT ;
    USE SIGNAL ;
    ANTENNAGATEAREA 0.795000 ;
    PORT
      LAYER met3 ;
        RECT 0.000 1225.400 0.600 1226.000 ;
    END
  END FrameData[34]
  PIN FrameData[35]
    DIRECTION INPUT ;
    USE SIGNAL ;
    ANTENNAGATEAREA 0.795000 ;
    PORT
      LAYER met3 ;
        RECT 0.000 1230.840 0.600 1231.440 ;
    END
  END FrameData[35]
  PIN FrameData[36]
    DIRECTION INPUT ;
    USE SIGNAL ;
    ANTENNAGATEAREA 0.795000 ;
    PORT
      LAYER met3 ;
        RECT 0.000 1236.280 0.600 1236.880 ;
    END
  END FrameData[36]
  PIN FrameData[37]
    DIRECTION INPUT ;
    USE SIGNAL ;
    ANTENNAGATEAREA 0.795000 ;
    PORT
      LAYER met3 ;
        RECT 0.000 1241.720 0.600 1242.320 ;
    END
  END FrameData[37]
  PIN FrameData[38]
    DIRECTION INPUT ;
    USE SIGNAL ;
    ANTENNAGATEAREA 0.795000 ;
    PORT
      LAYER met3 ;
        RECT 0.000 1247.160 0.600 1247.760 ;
    END
  END FrameData[38]
  PIN FrameData[39]
    DIRECTION INPUT ;
    USE SIGNAL ;
    ANTENNAGATEAREA 0.795000 ;
    PORT
      LAYER met3 ;
        RECT 0.000 1252.600 0.600 1253.200 ;
    END
  END FrameData[39]
  PIN FrameData[3]
    DIRECTION INPUT ;
    USE SIGNAL ;
    ANTENNAGATEAREA 0.593700 ;
    ANTENNADIFFAREA 0.434700 ;
    PORT
      LAYER met3 ;
        RECT 0.000 1406.280 0.600 1406.880 ;
    END
  END FrameData[3]
  PIN FrameData[40]
    DIRECTION INPUT ;
    USE SIGNAL ;
    ANTENNAGATEAREA 0.795000 ;
    PORT
      LAYER met3 ;
        RECT 0.000 1258.040 0.600 1258.640 ;
    END
  END FrameData[40]
  PIN FrameData[41]
    DIRECTION INPUT ;
    USE SIGNAL ;
    ANTENNAGATEAREA 0.795000 ;
    PORT
      LAYER met3 ;
        RECT 0.000 1263.480 0.600 1264.080 ;
    END
  END FrameData[41]
  PIN FrameData[42]
    DIRECTION INPUT ;
    USE SIGNAL ;
    ANTENNAGATEAREA 0.795000 ;
    PORT
      LAYER met3 ;
        RECT 0.000 1268.920 0.600 1269.520 ;
    END
  END FrameData[42]
  PIN FrameData[43]
    DIRECTION INPUT ;
    USE SIGNAL ;
    ANTENNAGATEAREA 0.795000 ;
    PORT
      LAYER met3 ;
        RECT 0.000 1274.360 0.600 1274.960 ;
    END
  END FrameData[43]
  PIN FrameData[44]
    DIRECTION INPUT ;
    USE SIGNAL ;
    ANTENNAGATEAREA 0.795000 ;
    PORT
      LAYER met3 ;
        RECT 0.000 1279.800 0.600 1280.400 ;
    END
  END FrameData[44]
  PIN FrameData[45]
    DIRECTION INPUT ;
    USE SIGNAL ;
    ANTENNAGATEAREA 0.795000 ;
    PORT
      LAYER met3 ;
        RECT 0.000 1285.240 0.600 1285.840 ;
    END
  END FrameData[45]
  PIN FrameData[46]
    DIRECTION INPUT ;
    USE SIGNAL ;
    ANTENNAGATEAREA 0.795000 ;
    PORT
      LAYER met3 ;
        RECT 0.000 1290.680 0.600 1291.280 ;
    END
  END FrameData[46]
  PIN FrameData[47]
    DIRECTION INPUT ;
    USE SIGNAL ;
    ANTENNAGATEAREA 0.795000 ;
    PORT
      LAYER met3 ;
        RECT 0.000 1296.120 0.600 1296.720 ;
    END
  END FrameData[47]
  PIN FrameData[48]
    DIRECTION INPUT ;
    USE SIGNAL ;
    ANTENNAGATEAREA 0.795000 ;
    PORT
      LAYER met3 ;
        RECT 0.000 1301.560 0.600 1302.160 ;
    END
  END FrameData[48]
  PIN FrameData[49]
    DIRECTION INPUT ;
    USE SIGNAL ;
    ANTENNAGATEAREA 0.795000 ;
    PORT
      LAYER met3 ;
        RECT 0.000 1307.000 0.600 1307.600 ;
    END
  END FrameData[49]
  PIN FrameData[4]
    DIRECTION INPUT ;
    USE SIGNAL ;
    ANTENNAGATEAREA 0.159000 ;
    PORT
      LAYER met3 ;
        RECT 0.000 1407.640 0.600 1408.240 ;
    END
  END FrameData[4]
  PIN FrameData[50]
    DIRECTION INPUT ;
    USE SIGNAL ;
    ANTENNAGATEAREA 1.664400 ;
    ANTENNADIFFAREA 0.869400 ;
    PORT
      LAYER met3 ;
        RECT 0.000 1312.440 0.600 1313.040 ;
    END
  END FrameData[50]
  PIN FrameData[51]
    DIRECTION INPUT ;
    USE SIGNAL ;
    ANTENNAGATEAREA 0.795000 ;
    PORT
      LAYER met3 ;
        RECT 0.000 1317.880 0.600 1318.480 ;
    END
  END FrameData[51]
  PIN FrameData[52]
    DIRECTION INPUT ;
    USE SIGNAL ;
    ANTENNAGATEAREA 0.795000 ;
    PORT
      LAYER met3 ;
        RECT 0.000 1323.320 0.600 1323.920 ;
    END
  END FrameData[52]
  PIN FrameData[53]
    DIRECTION INPUT ;
    USE SIGNAL ;
    ANTENNAGATEAREA 0.795000 ;
    PORT
      LAYER met3 ;
        RECT 0.000 1328.760 0.600 1329.360 ;
    END
  END FrameData[53]
  PIN FrameData[54]
    DIRECTION INPUT ;
    USE SIGNAL ;
    ANTENNAGATEAREA 1.229700 ;
    ANTENNADIFFAREA 0.434700 ;
    PORT
      LAYER met3 ;
        RECT 0.000 1334.200 0.600 1334.800 ;
    END
  END FrameData[54]
  PIN FrameData[55]
    DIRECTION INPUT ;
    USE SIGNAL ;
    ANTENNAGATEAREA 0.795000 ;
    PORT
      LAYER met3 ;
        RECT 0.000 1339.640 0.600 1340.240 ;
    END
  END FrameData[55]
  PIN FrameData[56]
    DIRECTION INPUT ;
    USE SIGNAL ;
    ANTENNAGATEAREA 0.795000 ;
    PORT
      LAYER met3 ;
        RECT 0.000 1345.080 0.600 1345.680 ;
    END
  END FrameData[56]
  PIN FrameData[57]
    DIRECTION INPUT ;
    USE SIGNAL ;
    ANTENNAGATEAREA 0.795000 ;
    PORT
      LAYER met3 ;
        RECT 0.000 1350.520 0.600 1351.120 ;
    END
  END FrameData[57]
  PIN FrameData[58]
    DIRECTION INPUT ;
    USE SIGNAL ;
    ANTENNAGATEAREA 0.795000 ;
    PORT
      LAYER met3 ;
        RECT 0.000 1355.960 0.600 1356.560 ;
    END
  END FrameData[58]
  PIN FrameData[59]
    DIRECTION INPUT ;
    USE SIGNAL ;
    ANTENNAGATEAREA 1.229700 ;
    ANTENNADIFFAREA 0.434700 ;
    PORT
      LAYER met3 ;
        RECT 0.000 1361.400 0.600 1362.000 ;
    END
  END FrameData[59]
  PIN FrameData[5]
    DIRECTION INPUT ;
    USE SIGNAL ;
    ANTENNAGATEAREA 0.159000 ;
    PORT
      LAYER met3 ;
        RECT 0.000 1409.000 0.600 1409.600 ;
    END
  END FrameData[5]
  PIN FrameData[60]
    DIRECTION INPUT ;
    USE SIGNAL ;
    ANTENNAGATEAREA 0.795000 ;
    PORT
      LAYER met3 ;
        RECT 0.000 1366.840 0.600 1367.440 ;
    END
  END FrameData[60]
  PIN FrameData[61]
    DIRECTION INPUT ;
    USE SIGNAL ;
    ANTENNAGATEAREA 0.795000 ;
    PORT
      LAYER met3 ;
        RECT 0.000 1372.280 0.600 1372.880 ;
    END
  END FrameData[61]
  PIN FrameData[62]
    DIRECTION INPUT ;
    USE SIGNAL ;
    ANTENNAGATEAREA 0.795000 ;
    PORT
      LAYER met3 ;
        RECT 0.000 1377.720 0.600 1378.320 ;
    END
  END FrameData[62]
  PIN FrameData[63]
    DIRECTION INPUT ;
    USE SIGNAL ;
    ANTENNAGATEAREA 0.795000 ;
    PORT
      LAYER met3 ;
        RECT 0.000 1383.160 0.600 1383.760 ;
    END
  END FrameData[63]
  PIN FrameData[64]
    DIRECTION INPUT ;
    USE SIGNAL ;
    ANTENNAGATEAREA 0.636000 ;
    PORT
      LAYER met3 ;
        RECT 0.000 991.480 0.600 992.080 ;
    END
  END FrameData[64]
  PIN FrameData[65]
    DIRECTION INPUT ;
    USE SIGNAL ;
    ANTENNAGATEAREA 0.636000 ;
    PORT
      LAYER met3 ;
        RECT 0.000 996.920 0.600 997.520 ;
    END
  END FrameData[65]
  PIN FrameData[66]
    DIRECTION INPUT ;
    USE SIGNAL ;
    ANTENNAGATEAREA 0.795000 ;
    PORT
      LAYER met3 ;
        RECT 0.000 1002.360 0.600 1002.960 ;
    END
  END FrameData[66]
  PIN FrameData[67]
    DIRECTION INPUT ;
    USE SIGNAL ;
    ANTENNAGATEAREA 0.795000 ;
    PORT
      LAYER met3 ;
        RECT 0.000 1007.800 0.600 1008.400 ;
    END
  END FrameData[67]
  PIN FrameData[68]
    DIRECTION INPUT ;
    USE SIGNAL ;
    ANTENNAGATEAREA 0.795000 ;
    PORT
      LAYER met3 ;
        RECT 0.000 1013.240 0.600 1013.840 ;
    END
  END FrameData[68]
  PIN FrameData[69]
    DIRECTION INPUT ;
    USE SIGNAL ;
    ANTENNAGATEAREA 0.795000 ;
    PORT
      LAYER met3 ;
        RECT 0.000 1018.680 0.600 1019.280 ;
    END
  END FrameData[69]
  PIN FrameData[6]
    DIRECTION INPUT ;
    USE SIGNAL ;
    ANTENNAGATEAREA 0.159000 ;
    PORT
      LAYER met3 ;
        RECT 0.000 1410.360 0.600 1410.960 ;
    END
  END FrameData[6]
  PIN FrameData[70]
    DIRECTION INPUT ;
    USE SIGNAL ;
    ANTENNAGATEAREA 0.795000 ;
    PORT
      LAYER met3 ;
        RECT 0.000 1024.120 0.600 1024.720 ;
    END
  END FrameData[70]
  PIN FrameData[71]
    DIRECTION INPUT ;
    USE SIGNAL ;
    ANTENNAGATEAREA 0.795000 ;
    PORT
      LAYER met3 ;
        RECT 0.000 1029.560 0.600 1030.160 ;
    END
  END FrameData[71]
  PIN FrameData[72]
    DIRECTION INPUT ;
    USE SIGNAL ;
    ANTENNAGATEAREA 0.795000 ;
    PORT
      LAYER met3 ;
        RECT 0.000 1035.000 0.600 1035.600 ;
    END
  END FrameData[72]
  PIN FrameData[73]
    DIRECTION INPUT ;
    USE SIGNAL ;
    ANTENNAGATEAREA 0.795000 ;
    PORT
      LAYER met3 ;
        RECT 0.000 1040.440 0.600 1041.040 ;
    END
  END FrameData[73]
  PIN FrameData[74]
    DIRECTION INPUT ;
    USE SIGNAL ;
    ANTENNAGATEAREA 0.795000 ;
    PORT
      LAYER met3 ;
        RECT 0.000 1045.880 0.600 1046.480 ;
    END
  END FrameData[74]
  PIN FrameData[75]
    DIRECTION INPUT ;
    USE SIGNAL ;
    ANTENNAGATEAREA 0.795000 ;
    PORT
      LAYER met3 ;
        RECT 0.000 1051.320 0.600 1051.920 ;
    END
  END FrameData[75]
  PIN FrameData[76]
    DIRECTION INPUT ;
    USE SIGNAL ;
    ANTENNAGATEAREA 0.795000 ;
    PORT
      LAYER met3 ;
        RECT 0.000 1056.760 0.600 1057.360 ;
    END
  END FrameData[76]
  PIN FrameData[77]
    DIRECTION INPUT ;
    USE SIGNAL ;
    ANTENNAGATEAREA 0.795000 ;
    PORT
      LAYER met3 ;
        RECT 0.000 1062.200 0.600 1062.800 ;
    END
  END FrameData[77]
  PIN FrameData[78]
    DIRECTION INPUT ;
    USE SIGNAL ;
    ANTENNAGATEAREA 0.795000 ;
    PORT
      LAYER met3 ;
        RECT 0.000 1067.640 0.600 1068.240 ;
    END
  END FrameData[78]
  PIN FrameData[79]
    DIRECTION INPUT ;
    USE SIGNAL ;
    ANTENNAGATEAREA 0.795000 ;
    PORT
      LAYER met3 ;
        RECT 0.000 1073.080 0.600 1073.680 ;
    END
  END FrameData[79]
  PIN FrameData[7]
    DIRECTION INPUT ;
    USE SIGNAL ;
    ANTENNAGATEAREA 0.593700 ;
    ANTENNADIFFAREA 0.434700 ;
    PORT
      LAYER met3 ;
        RECT 0.000 1411.720 0.600 1412.320 ;
    END
  END FrameData[7]
  PIN FrameData[80]
    DIRECTION INPUT ;
    USE SIGNAL ;
    ANTENNAGATEAREA 0.795000 ;
    PORT
      LAYER met3 ;
        RECT 0.000 1078.520 0.600 1079.120 ;
    END
  END FrameData[80]
  PIN FrameData[81]
    DIRECTION INPUT ;
    USE SIGNAL ;
    ANTENNAGATEAREA 0.795000 ;
    PORT
      LAYER met3 ;
        RECT 0.000 1083.960 0.600 1084.560 ;
    END
  END FrameData[81]
  PIN FrameData[82]
    DIRECTION INPUT ;
    USE SIGNAL ;
    ANTENNAGATEAREA 1.664400 ;
    ANTENNADIFFAREA 0.869400 ;
    PORT
      LAYER met3 ;
        RECT 0.000 1089.400 0.600 1090.000 ;
    END
  END FrameData[82]
  PIN FrameData[83]
    DIRECTION INPUT ;
    USE SIGNAL ;
    ANTENNAGATEAREA 0.795000 ;
    PORT
      LAYER met3 ;
        RECT 0.000 1094.840 0.600 1095.440 ;
    END
  END FrameData[83]
  PIN FrameData[84]
    DIRECTION INPUT ;
    USE SIGNAL ;
    ANTENNAGATEAREA 0.795000 ;
    PORT
      LAYER met3 ;
        RECT 0.000 1100.280 0.600 1100.880 ;
    END
  END FrameData[84]
  PIN FrameData[85]
    DIRECTION INPUT ;
    USE SIGNAL ;
    ANTENNAGATEAREA 0.795000 ;
    PORT
      LAYER met3 ;
        RECT 0.000 1105.720 0.600 1106.320 ;
    END
  END FrameData[85]
  PIN FrameData[86]
    DIRECTION INPUT ;
    USE SIGNAL ;
    ANTENNAGATEAREA 1.229700 ;
    ANTENNADIFFAREA 0.434700 ;
    PORT
      LAYER met3 ;
        RECT 0.000 1111.160 0.600 1111.760 ;
    END
  END FrameData[86]
  PIN FrameData[87]
    DIRECTION INPUT ;
    USE SIGNAL ;
    ANTENNAGATEAREA 0.795000 ;
    PORT
      LAYER met3 ;
        RECT 0.000 1116.600 0.600 1117.200 ;
    END
  END FrameData[87]
  PIN FrameData[88]
    DIRECTION INPUT ;
    USE SIGNAL ;
    ANTENNAGATEAREA 0.795000 ;
    PORT
      LAYER met3 ;
        RECT 0.000 1122.040 0.600 1122.640 ;
    END
  END FrameData[88]
  PIN FrameData[89]
    DIRECTION INPUT ;
    USE SIGNAL ;
    ANTENNAGATEAREA 0.795000 ;
    PORT
      LAYER met3 ;
        RECT 0.000 1127.480 0.600 1128.080 ;
    END
  END FrameData[89]
  PIN FrameData[8]
    DIRECTION INPUT ;
    USE SIGNAL ;
    ANTENNAGATEAREA 0.159000 ;
    PORT
      LAYER met3 ;
        RECT 0.000 1413.080 0.600 1413.680 ;
    END
  END FrameData[8]
  PIN FrameData[90]
    DIRECTION INPUT ;
    USE SIGNAL ;
    ANTENNAGATEAREA 0.795000 ;
    PORT
      LAYER met3 ;
        RECT 0.000 1132.920 0.600 1133.520 ;
    END
  END FrameData[90]
  PIN FrameData[91]
    DIRECTION INPUT ;
    USE SIGNAL ;
    ANTENNAGATEAREA 1.229700 ;
    ANTENNADIFFAREA 0.434700 ;
    PORT
      LAYER met3 ;
        RECT 0.000 1138.360 0.600 1138.960 ;
    END
  END FrameData[91]
  PIN FrameData[92]
    DIRECTION INPUT ;
    USE SIGNAL ;
    ANTENNAGATEAREA 0.795000 ;
    PORT
      LAYER met3 ;
        RECT 0.000 1143.800 0.600 1144.400 ;
    END
  END FrameData[92]
  PIN FrameData[93]
    DIRECTION INPUT ;
    USE SIGNAL ;
    ANTENNAGATEAREA 0.795000 ;
    PORT
      LAYER met3 ;
        RECT 0.000 1149.240 0.600 1149.840 ;
    END
  END FrameData[93]
  PIN FrameData[94]
    DIRECTION INPUT ;
    USE SIGNAL ;
    ANTENNAGATEAREA 0.795000 ;
    PORT
      LAYER met3 ;
        RECT 0.000 1154.680 0.600 1155.280 ;
    END
  END FrameData[94]
  PIN FrameData[95]
    DIRECTION INPUT ;
    USE SIGNAL ;
    ANTENNAGATEAREA 0.795000 ;
    PORT
      LAYER met3 ;
        RECT 0.000 1160.120 0.600 1160.720 ;
    END
  END FrameData[95]
  PIN FrameData[96]
    DIRECTION INPUT ;
    USE SIGNAL ;
    ANTENNAGATEAREA 0.636000 ;
    PORT
      LAYER met3 ;
        RECT 0.000 768.440 0.600 769.040 ;
    END
  END FrameData[96]
  PIN FrameData[97]
    DIRECTION INPUT ;
    USE SIGNAL ;
    ANTENNAGATEAREA 0.636000 ;
    PORT
      LAYER met3 ;
        RECT 0.000 773.880 0.600 774.480 ;
    END
  END FrameData[97]
  PIN FrameData[98]
    DIRECTION INPUT ;
    USE SIGNAL ;
    ANTENNAGATEAREA 0.795000 ;
    PORT
      LAYER met3 ;
        RECT 0.000 779.320 0.600 779.920 ;
    END
  END FrameData[98]
  PIN FrameData[99]
    DIRECTION INPUT ;
    USE SIGNAL ;
    ANTENNAGATEAREA 0.795000 ;
    PORT
      LAYER met3 ;
        RECT 0.000 784.760 0.600 785.360 ;
    END
  END FrameData[99]
  PIN FrameData[9]
    DIRECTION INPUT ;
    USE SIGNAL ;
    ANTENNAGATEAREA 0.159000 ;
    PORT
      LAYER met3 ;
        RECT 0.000 1414.440 0.600 1415.040 ;
    END
  END FrameData[9]
  PIN FrameStrobe[0]
    DIRECTION INPUT ;
    USE SIGNAL ;
    ANTENNAGATEAREA 3.339000 ;
    PORT
      LAYER met2 ;
        RECT 6.990 0.000 7.270 0.280 ;
    END
  END FrameStrobe[0]
  PIN FrameStrobe[100]
    DIRECTION INPUT ;
    USE SIGNAL ;
    ANTENNAGATEAREA 1.431000 ;
    PORT
      LAYER met2 ;
        RECT 949.070 0.000 949.350 0.280 ;
    END
  END FrameStrobe[100]
  PIN FrameStrobe[101]
    DIRECTION INPUT ;
    USE SIGNAL ;
    ANTENNAGATEAREA 0.593700 ;
    ANTENNADIFFAREA 0.434700 ;
    PORT
      LAYER met2 ;
        RECT 959.190 0.000 959.470 0.280 ;
    END
  END FrameStrobe[101]
  PIN FrameStrobe[102]
    DIRECTION INPUT ;
    USE SIGNAL ;
    ANTENNAGATEAREA 0.593700 ;
    ANTENNADIFFAREA 0.434700 ;
    PORT
      LAYER met2 ;
        RECT 969.310 0.000 969.590 0.280 ;
    END
  END FrameStrobe[102]
  PIN FrameStrobe[103]
    DIRECTION INPUT ;
    USE SIGNAL ;
    ANTENNAGATEAREA 0.159000 ;
    PORT
      LAYER met2 ;
        RECT 979.430 0.000 979.710 0.280 ;
    END
  END FrameStrobe[103]
  PIN FrameStrobe[104]
    DIRECTION INPUT ;
    USE SIGNAL ;
    ANTENNAGATEAREA 0.159000 ;
    PORT
      LAYER met2 ;
        RECT 989.550 0.000 989.830 0.280 ;
    END
  END FrameStrobe[104]
  PIN FrameStrobe[105]
    DIRECTION INPUT ;
    USE SIGNAL ;
    ANTENNAGATEAREA 0.159000 ;
    PORT
      LAYER met2 ;
        RECT 999.670 0.000 999.950 0.280 ;
    END
  END FrameStrobe[105]
  PIN FrameStrobe[106]
    DIRECTION INPUT ;
    USE SIGNAL ;
    ANTENNAGATEAREA 0.159000 ;
    PORT
      LAYER met2 ;
        RECT 1009.790 0.000 1010.070 0.280 ;
    END
  END FrameStrobe[106]
  PIN FrameStrobe[107]
    DIRECTION INPUT ;
    USE SIGNAL ;
    ANTENNAGATEAREA 0.159000 ;
    PORT
      LAYER met2 ;
        RECT 1019.910 0.000 1020.190 0.280 ;
    END
  END FrameStrobe[107]
  PIN FrameStrobe[108]
    DIRECTION INPUT ;
    USE SIGNAL ;
    ANTENNAGATEAREA 0.159000 ;
    PORT
      LAYER met2 ;
        RECT 1030.030 0.000 1030.310 0.280 ;
    END
  END FrameStrobe[108]
  PIN FrameStrobe[109]
    DIRECTION INPUT ;
    USE SIGNAL ;
    ANTENNAGATEAREA 0.159000 ;
    PORT
      LAYER met2 ;
        RECT 1040.150 0.000 1040.430 0.280 ;
    END
  END FrameStrobe[109]
  PIN FrameStrobe[10]
    DIRECTION INPUT ;
    USE SIGNAL ;
    ANTENNAGATEAREA 0.159000 ;
    PORT
      LAYER met2 ;
        RECT 29.990 0.000 30.270 0.280 ;
    END
  END FrameStrobe[10]
  PIN FrameStrobe[110]
    DIRECTION INPUT ;
    USE SIGNAL ;
    ANTENNAGATEAREA 0.159000 ;
    PORT
      LAYER met2 ;
        RECT 1050.270 0.000 1050.550 0.280 ;
    END
  END FrameStrobe[110]
  PIN FrameStrobe[111]
    DIRECTION INPUT ;
    USE SIGNAL ;
    ANTENNAGATEAREA 0.159000 ;
    PORT
      LAYER met2 ;
        RECT 1060.390 0.000 1060.670 0.280 ;
    END
  END FrameStrobe[111]
  PIN FrameStrobe[112]
    DIRECTION INPUT ;
    USE SIGNAL ;
    ANTENNAGATEAREA 0.159000 ;
    PORT
      LAYER met2 ;
        RECT 1070.510 0.000 1070.790 0.280 ;
    END
  END FrameStrobe[112]
  PIN FrameStrobe[113]
    DIRECTION INPUT ;
    USE SIGNAL ;
    ANTENNAGATEAREA 0.159000 ;
    PORT
      LAYER met2 ;
        RECT 1080.630 0.000 1080.910 0.280 ;
    END
  END FrameStrobe[113]
  PIN FrameStrobe[114]
    DIRECTION INPUT ;
    USE SIGNAL ;
    ANTENNAGATEAREA 0.159000 ;
    PORT
      LAYER met2 ;
        RECT 1090.750 0.000 1091.030 0.280 ;
    END
  END FrameStrobe[114]
  PIN FrameStrobe[115]
    DIRECTION INPUT ;
    USE SIGNAL ;
    ANTENNAGATEAREA 0.159000 ;
    PORT
      LAYER met2 ;
        RECT 1100.870 0.000 1101.150 0.280 ;
    END
  END FrameStrobe[115]
  PIN FrameStrobe[116]
    DIRECTION INPUT ;
    USE SIGNAL ;
    ANTENNAGATEAREA 0.159000 ;
    PORT
      LAYER met2 ;
        RECT 1110.990 0.000 1111.270 0.280 ;
    END
  END FrameStrobe[116]
  PIN FrameStrobe[117]
    DIRECTION INPUT ;
    USE SIGNAL ;
    ANTENNAGATEAREA 0.159000 ;
    PORT
      LAYER met2 ;
        RECT 1121.110 0.000 1121.390 0.280 ;
    END
  END FrameStrobe[117]
  PIN FrameStrobe[118]
    DIRECTION INPUT ;
    USE SIGNAL ;
    ANTENNAGATEAREA 0.159000 ;
    PORT
      LAYER met2 ;
        RECT 1131.230 0.000 1131.510 0.280 ;
    END
  END FrameStrobe[118]
  PIN FrameStrobe[119]
    DIRECTION INPUT ;
    USE SIGNAL ;
    ANTENNAGATEAREA 0.159000 ;
    PORT
      LAYER met2 ;
        RECT 1141.350 0.000 1141.630 0.280 ;
    END
  END FrameStrobe[119]
  PIN FrameStrobe[11]
    DIRECTION INPUT ;
    USE SIGNAL ;
    ANTENNAGATEAREA 0.159000 ;
    PORT
      LAYER met2 ;
        RECT 32.290 0.000 32.570 0.280 ;
    END
  END FrameStrobe[11]
  PIN FrameStrobe[120]
    DIRECTION INPUT ;
    USE SIGNAL ;
    ANTENNAGATEAREA 1.431000 ;
    PORT
      LAYER met2 ;
        RECT 1160.210 0.000 1160.490 0.280 ;
    END
  END FrameStrobe[120]
  PIN FrameStrobe[121]
    DIRECTION INPUT ;
    USE SIGNAL ;
    ANTENNAGATEAREA 0.159000 ;
    PORT
      LAYER met2 ;
        RECT 1170.790 0.000 1171.070 0.280 ;
    END
  END FrameStrobe[121]
  PIN FrameStrobe[122]
    DIRECTION INPUT ;
    USE SIGNAL ;
    ANTENNAGATEAREA 0.159000 ;
    PORT
      LAYER met2 ;
        RECT 1181.370 0.000 1181.650 0.280 ;
    END
  END FrameStrobe[122]
  PIN FrameStrobe[123]
    DIRECTION INPUT ;
    USE SIGNAL ;
    ANTENNAGATEAREA 0.159000 ;
    PORT
      LAYER met2 ;
        RECT 1191.950 0.000 1192.230 0.280 ;
    END
  END FrameStrobe[123]
  PIN FrameStrobe[124]
    DIRECTION INPUT ;
    USE SIGNAL ;
    ANTENNAGATEAREA 0.159000 ;
    PORT
      LAYER met2 ;
        RECT 1202.530 0.000 1202.810 0.280 ;
    END
  END FrameStrobe[124]
  PIN FrameStrobe[125]
    DIRECTION INPUT ;
    USE SIGNAL ;
    ANTENNAGATEAREA 0.159000 ;
    PORT
      LAYER met2 ;
        RECT 1213.110 0.000 1213.390 0.280 ;
    END
  END FrameStrobe[125]
  PIN FrameStrobe[126]
    DIRECTION INPUT ;
    USE SIGNAL ;
    ANTENNAGATEAREA 0.159000 ;
    PORT
      LAYER met2 ;
        RECT 1223.690 0.000 1223.970 0.280 ;
    END
  END FrameStrobe[126]
  PIN FrameStrobe[127]
    DIRECTION INPUT ;
    USE SIGNAL ;
    ANTENNAGATEAREA 0.159000 ;
    PORT
      LAYER met2 ;
        RECT 1234.270 0.000 1234.550 0.280 ;
    END
  END FrameStrobe[127]
  PIN FrameStrobe[128]
    DIRECTION INPUT ;
    USE SIGNAL ;
    ANTENNAGATEAREA 0.159000 ;
    PORT
      LAYER met2 ;
        RECT 1244.850 0.000 1245.130 0.280 ;
    END
  END FrameStrobe[128]
  PIN FrameStrobe[129]
    DIRECTION INPUT ;
    USE SIGNAL ;
    ANTENNAGATEAREA 0.159000 ;
    PORT
      LAYER met2 ;
        RECT 1255.430 0.000 1255.710 0.280 ;
    END
  END FrameStrobe[129]
  PIN FrameStrobe[12]
    DIRECTION INPUT ;
    USE SIGNAL ;
    ANTENNAGATEAREA 0.159000 ;
    PORT
      LAYER met2 ;
        RECT 34.590 0.000 34.870 0.280 ;
    END
  END FrameStrobe[12]
  PIN FrameStrobe[130]
    DIRECTION INPUT ;
    USE SIGNAL ;
    ANTENNAGATEAREA 0.159000 ;
    PORT
      LAYER met2 ;
        RECT 1266.010 0.000 1266.290 0.280 ;
    END
  END FrameStrobe[130]
  PIN FrameStrobe[131]
    DIRECTION INPUT ;
    USE SIGNAL ;
    ANTENNAGATEAREA 0.159000 ;
    PORT
      LAYER met2 ;
        RECT 1276.590 0.000 1276.870 0.280 ;
    END
  END FrameStrobe[131]
  PIN FrameStrobe[132]
    DIRECTION INPUT ;
    USE SIGNAL ;
    ANTENNAGATEAREA 0.159000 ;
    PORT
      LAYER met2 ;
        RECT 1287.170 0.000 1287.450 0.280 ;
    END
  END FrameStrobe[132]
  PIN FrameStrobe[133]
    DIRECTION INPUT ;
    USE SIGNAL ;
    ANTENNAGATEAREA 0.159000 ;
    PORT
      LAYER met2 ;
        RECT 1297.750 0.000 1298.030 0.280 ;
    END
  END FrameStrobe[133]
  PIN FrameStrobe[134]
    DIRECTION INPUT ;
    USE SIGNAL ;
    ANTENNAGATEAREA 0.159000 ;
    PORT
      LAYER met2 ;
        RECT 1308.330 0.000 1308.610 0.280 ;
    END
  END FrameStrobe[134]
  PIN FrameStrobe[135]
    DIRECTION INPUT ;
    USE SIGNAL ;
    ANTENNAGATEAREA 0.159000 ;
    PORT
      LAYER met2 ;
        RECT 1318.910 0.000 1319.190 0.280 ;
    END
  END FrameStrobe[135]
  PIN FrameStrobe[136]
    DIRECTION INPUT ;
    USE SIGNAL ;
    ANTENNAGATEAREA 0.159000 ;
    PORT
      LAYER met2 ;
        RECT 1329.490 0.000 1329.770 0.280 ;
    END
  END FrameStrobe[136]
  PIN FrameStrobe[137]
    DIRECTION INPUT ;
    USE SIGNAL ;
    ANTENNAGATEAREA 0.159000 ;
    PORT
      LAYER met2 ;
        RECT 1340.070 0.000 1340.350 0.280 ;
    END
  END FrameStrobe[137]
  PIN FrameStrobe[138]
    DIRECTION INPUT ;
    USE SIGNAL ;
    ANTENNAGATEAREA 0.159000 ;
    PORT
      LAYER met2 ;
        RECT 1350.650 0.000 1350.930 0.280 ;
    END
  END FrameStrobe[138]
  PIN FrameStrobe[139]
    DIRECTION INPUT ;
    USE SIGNAL ;
    ANTENNAGATEAREA 0.159000 ;
    PORT
      LAYER met2 ;
        RECT 1361.230 0.000 1361.510 0.280 ;
    END
  END FrameStrobe[139]
  PIN FrameStrobe[13]
    DIRECTION INPUT ;
    USE SIGNAL ;
    ANTENNAGATEAREA 0.159000 ;
    PORT
      LAYER met2 ;
        RECT 36.890 0.000 37.170 0.280 ;
    END
  END FrameStrobe[13]
  PIN FrameStrobe[140]
    DIRECTION INPUT ;
    USE SIGNAL ;
    ANTENNAGATEAREA 1.431000 ;
    PORT
      LAYER met2 ;
        RECT 1379.630 0.000 1379.910 0.280 ;
    END
  END FrameStrobe[140]
  PIN FrameStrobe[141]
    DIRECTION INPUT ;
    USE SIGNAL ;
    ANTENNAGATEAREA 0.593700 ;
    ANTENNADIFFAREA 0.434700 ;
    PORT
      LAYER met2 ;
        RECT 1389.750 0.000 1390.030 0.280 ;
    END
  END FrameStrobe[141]
  PIN FrameStrobe[142]
    DIRECTION INPUT ;
    USE SIGNAL ;
    ANTENNAGATEAREA 0.593700 ;
    ANTENNADIFFAREA 0.434700 ;
    PORT
      LAYER met2 ;
        RECT 1399.870 0.000 1400.150 0.280 ;
    END
  END FrameStrobe[142]
  PIN FrameStrobe[143]
    DIRECTION INPUT ;
    USE SIGNAL ;
    ANTENNAGATEAREA 0.159000 ;
    PORT
      LAYER met2 ;
        RECT 1409.990 0.000 1410.270 0.280 ;
    END
  END FrameStrobe[143]
  PIN FrameStrobe[144]
    DIRECTION INPUT ;
    USE SIGNAL ;
    ANTENNAGATEAREA 0.159000 ;
    PORT
      LAYER met2 ;
        RECT 1420.110 0.000 1420.390 0.280 ;
    END
  END FrameStrobe[144]
  PIN FrameStrobe[145]
    DIRECTION INPUT ;
    USE SIGNAL ;
    ANTENNAGATEAREA 0.159000 ;
    PORT
      LAYER met2 ;
        RECT 1430.230 0.000 1430.510 0.280 ;
    END
  END FrameStrobe[145]
  PIN FrameStrobe[146]
    DIRECTION INPUT ;
    USE SIGNAL ;
    ANTENNAGATEAREA 0.159000 ;
    PORT
      LAYER met2 ;
        RECT 1440.350 0.000 1440.630 0.280 ;
    END
  END FrameStrobe[146]
  PIN FrameStrobe[147]
    DIRECTION INPUT ;
    USE SIGNAL ;
    ANTENNAGATEAREA 0.159000 ;
    PORT
      LAYER met2 ;
        RECT 1450.470 0.000 1450.750 0.280 ;
    END
  END FrameStrobe[147]
  PIN FrameStrobe[148]
    DIRECTION INPUT ;
    USE SIGNAL ;
    ANTENNAGATEAREA 0.159000 ;
    PORT
      LAYER met2 ;
        RECT 1460.590 0.000 1460.870 0.280 ;
    END
  END FrameStrobe[148]
  PIN FrameStrobe[149]
    DIRECTION INPUT ;
    USE SIGNAL ;
    ANTENNAGATEAREA 0.159000 ;
    PORT
      LAYER met2 ;
        RECT 1470.710 0.000 1470.990 0.280 ;
    END
  END FrameStrobe[149]
  PIN FrameStrobe[14]
    DIRECTION INPUT ;
    USE SIGNAL ;
    ANTENNAGATEAREA 0.159000 ;
    PORT
      LAYER met2 ;
        RECT 39.190 0.000 39.470 0.280 ;
    END
  END FrameStrobe[14]
  PIN FrameStrobe[150]
    DIRECTION INPUT ;
    USE SIGNAL ;
    ANTENNAGATEAREA 0.159000 ;
    PORT
      LAYER met2 ;
        RECT 1480.830 0.000 1481.110 0.280 ;
    END
  END FrameStrobe[150]
  PIN FrameStrobe[151]
    DIRECTION INPUT ;
    USE SIGNAL ;
    ANTENNAGATEAREA 0.159000 ;
    PORT
      LAYER met2 ;
        RECT 1490.950 0.000 1491.230 0.280 ;
    END
  END FrameStrobe[151]
  PIN FrameStrobe[152]
    DIRECTION INPUT ;
    USE SIGNAL ;
    ANTENNAGATEAREA 0.159000 ;
    PORT
      LAYER met2 ;
        RECT 1501.070 0.000 1501.350 0.280 ;
    END
  END FrameStrobe[152]
  PIN FrameStrobe[153]
    DIRECTION INPUT ;
    USE SIGNAL ;
    ANTENNAGATEAREA 0.159000 ;
    PORT
      LAYER met2 ;
        RECT 1511.190 0.000 1511.470 0.280 ;
    END
  END FrameStrobe[153]
  PIN FrameStrobe[154]
    DIRECTION INPUT ;
    USE SIGNAL ;
    ANTENNAGATEAREA 0.159000 ;
    PORT
      LAYER met2 ;
        RECT 1521.310 0.000 1521.590 0.280 ;
    END
  END FrameStrobe[154]
  PIN FrameStrobe[155]
    DIRECTION INPUT ;
    USE SIGNAL ;
    ANTENNAGATEAREA 0.159000 ;
    PORT
      LAYER met2 ;
        RECT 1531.430 0.000 1531.710 0.280 ;
    END
  END FrameStrobe[155]
  PIN FrameStrobe[156]
    DIRECTION INPUT ;
    USE SIGNAL ;
    ANTENNAGATEAREA 0.159000 ;
    PORT
      LAYER met2 ;
        RECT 1541.550 0.000 1541.830 0.280 ;
    END
  END FrameStrobe[156]
  PIN FrameStrobe[157]
    DIRECTION INPUT ;
    USE SIGNAL ;
    ANTENNAGATEAREA 0.159000 ;
    PORT
      LAYER met2 ;
        RECT 1551.670 0.000 1551.950 0.280 ;
    END
  END FrameStrobe[157]
  PIN FrameStrobe[158]
    DIRECTION INPUT ;
    USE SIGNAL ;
    ANTENNAGATEAREA 0.159000 ;
    PORT
      LAYER met2 ;
        RECT 1561.790 0.000 1562.070 0.280 ;
    END
  END FrameStrobe[158]
  PIN FrameStrobe[159]
    DIRECTION INPUT ;
    USE SIGNAL ;
    ANTENNAGATEAREA 0.159000 ;
    PORT
      LAYER met2 ;
        RECT 1571.910 0.000 1572.190 0.280 ;
    END
  END FrameStrobe[159]
  PIN FrameStrobe[15]
    DIRECTION INPUT ;
    USE SIGNAL ;
    ANTENNAGATEAREA 0.159000 ;
    PORT
      LAYER met2 ;
        RECT 41.490 0.000 41.770 0.280 ;
    END
  END FrameStrobe[15]
  PIN FrameStrobe[160]
    DIRECTION INPUT ;
    USE SIGNAL ;
    ANTENNAGATEAREA 1.431000 ;
    PORT
      LAYER met2 ;
        RECT 1590.310 0.000 1590.590 0.280 ;
    END
  END FrameStrobe[160]
  PIN FrameStrobe[161]
    DIRECTION INPUT ;
    USE SIGNAL ;
    ANTENNAGATEAREA 0.593700 ;
    ANTENNADIFFAREA 0.434700 ;
    PORT
      LAYER met2 ;
        RECT 1600.430 0.000 1600.710 0.280 ;
    END
  END FrameStrobe[161]
  PIN FrameStrobe[162]
    DIRECTION INPUT ;
    USE SIGNAL ;
    ANTENNAGATEAREA 0.593700 ;
    ANTENNADIFFAREA 0.434700 ;
    PORT
      LAYER met2 ;
        RECT 1610.550 0.000 1610.830 0.280 ;
    END
  END FrameStrobe[162]
  PIN FrameStrobe[163]
    DIRECTION INPUT ;
    USE SIGNAL ;
    ANTENNAGATEAREA 0.159000 ;
    PORT
      LAYER met2 ;
        RECT 1620.670 0.000 1620.950 0.280 ;
    END
  END FrameStrobe[163]
  PIN FrameStrobe[164]
    DIRECTION INPUT ;
    USE SIGNAL ;
    ANTENNAGATEAREA 0.159000 ;
    PORT
      LAYER met2 ;
        RECT 1630.790 0.000 1631.070 0.280 ;
    END
  END FrameStrobe[164]
  PIN FrameStrobe[165]
    DIRECTION INPUT ;
    USE SIGNAL ;
    ANTENNAGATEAREA 0.159000 ;
    PORT
      LAYER met2 ;
        RECT 1640.910 0.000 1641.190 0.280 ;
    END
  END FrameStrobe[165]
  PIN FrameStrobe[166]
    DIRECTION INPUT ;
    USE SIGNAL ;
    ANTENNAGATEAREA 0.159000 ;
    PORT
      LAYER met2 ;
        RECT 1651.030 0.000 1651.310 0.280 ;
    END
  END FrameStrobe[166]
  PIN FrameStrobe[167]
    DIRECTION INPUT ;
    USE SIGNAL ;
    ANTENNAGATEAREA 0.159000 ;
    PORT
      LAYER met2 ;
        RECT 1661.150 0.000 1661.430 0.280 ;
    END
  END FrameStrobe[167]
  PIN FrameStrobe[168]
    DIRECTION INPUT ;
    USE SIGNAL ;
    ANTENNAGATEAREA 0.159000 ;
    PORT
      LAYER met2 ;
        RECT 1671.270 0.000 1671.550 0.280 ;
    END
  END FrameStrobe[168]
  PIN FrameStrobe[169]
    DIRECTION INPUT ;
    USE SIGNAL ;
    ANTENNAGATEAREA 0.159000 ;
    PORT
      LAYER met2 ;
        RECT 1681.390 0.000 1681.670 0.280 ;
    END
  END FrameStrobe[169]
  PIN FrameStrobe[16]
    DIRECTION INPUT ;
    USE SIGNAL ;
    ANTENNAGATEAREA 0.159000 ;
    PORT
      LAYER met2 ;
        RECT 43.790 0.000 44.070 0.280 ;
    END
  END FrameStrobe[16]
  PIN FrameStrobe[170]
    DIRECTION INPUT ;
    USE SIGNAL ;
    ANTENNAGATEAREA 0.159000 ;
    PORT
      LAYER met2 ;
        RECT 1691.510 0.000 1691.790 0.280 ;
    END
  END FrameStrobe[170]
  PIN FrameStrobe[171]
    DIRECTION INPUT ;
    USE SIGNAL ;
    ANTENNAGATEAREA 0.159000 ;
    PORT
      LAYER met2 ;
        RECT 1701.630 0.000 1701.910 0.280 ;
    END
  END FrameStrobe[171]
  PIN FrameStrobe[172]
    DIRECTION INPUT ;
    USE SIGNAL ;
    ANTENNAGATEAREA 0.159000 ;
    PORT
      LAYER met2 ;
        RECT 1711.750 0.000 1712.030 0.280 ;
    END
  END FrameStrobe[172]
  PIN FrameStrobe[173]
    DIRECTION INPUT ;
    USE SIGNAL ;
    ANTENNAGATEAREA 0.159000 ;
    PORT
      LAYER met2 ;
        RECT 1721.870 0.000 1722.150 0.280 ;
    END
  END FrameStrobe[173]
  PIN FrameStrobe[174]
    DIRECTION INPUT ;
    USE SIGNAL ;
    ANTENNAGATEAREA 0.159000 ;
    PORT
      LAYER met2 ;
        RECT 1731.990 0.000 1732.270 0.280 ;
    END
  END FrameStrobe[174]
  PIN FrameStrobe[175]
    DIRECTION INPUT ;
    USE SIGNAL ;
    ANTENNAGATEAREA 0.159000 ;
    PORT
      LAYER met2 ;
        RECT 1742.110 0.000 1742.390 0.280 ;
    END
  END FrameStrobe[175]
  PIN FrameStrobe[176]
    DIRECTION INPUT ;
    USE SIGNAL ;
    ANTENNAGATEAREA 0.159000 ;
    PORT
      LAYER met2 ;
        RECT 1752.230 0.000 1752.510 0.280 ;
    END
  END FrameStrobe[176]
  PIN FrameStrobe[177]
    DIRECTION INPUT ;
    USE SIGNAL ;
    ANTENNAGATEAREA 0.159000 ;
    PORT
      LAYER met2 ;
        RECT 1762.350 0.000 1762.630 0.280 ;
    END
  END FrameStrobe[177]
  PIN FrameStrobe[178]
    DIRECTION INPUT ;
    USE SIGNAL ;
    ANTENNAGATEAREA 0.159000 ;
    PORT
      LAYER met2 ;
        RECT 1772.470 0.000 1772.750 0.280 ;
    END
  END FrameStrobe[178]
  PIN FrameStrobe[179]
    DIRECTION INPUT ;
    USE SIGNAL ;
    ANTENNAGATEAREA 0.159000 ;
    PORT
      LAYER met2 ;
        RECT 1782.590 0.000 1782.870 0.280 ;
    END
  END FrameStrobe[179]
  PIN FrameStrobe[17]
    DIRECTION INPUT ;
    USE SIGNAL ;
    ANTENNAGATEAREA 0.159000 ;
    PORT
      LAYER met2 ;
        RECT 46.090 0.000 46.370 0.280 ;
    END
  END FrameStrobe[17]
  PIN FrameStrobe[180]
    DIRECTION INPUT ;
    USE SIGNAL ;
    ANTENNAGATEAREA 0.795000 ;
    PORT
      LAYER met2 ;
        RECT 1793.630 0.000 1793.910 0.280 ;
    END
  END FrameStrobe[180]
  PIN FrameStrobe[181]
    DIRECTION INPUT ;
    USE SIGNAL ;
    ANTENNAGATEAREA 0.159000 ;
    PORT
      LAYER met2 ;
        RECT 1796.390 0.000 1796.670 0.280 ;
    END
  END FrameStrobe[181]
  PIN FrameStrobe[182]
    DIRECTION INPUT ;
    USE SIGNAL ;
    ANTENNAGATEAREA 0.159000 ;
    PORT
      LAYER met2 ;
        RECT 1799.150 0.000 1799.430 0.280 ;
    END
  END FrameStrobe[182]
  PIN FrameStrobe[183]
    DIRECTION INPUT ;
    USE SIGNAL ;
    ANTENNAGATEAREA 0.159000 ;
    PORT
      LAYER met2 ;
        RECT 1801.910 0.000 1802.190 0.280 ;
    END
  END FrameStrobe[183]
  PIN FrameStrobe[184]
    DIRECTION INPUT ;
    USE SIGNAL ;
    ANTENNAGATEAREA 0.159000 ;
    PORT
      LAYER met2 ;
        RECT 1804.670 0.000 1804.950 0.280 ;
    END
  END FrameStrobe[184]
  PIN FrameStrobe[185]
    DIRECTION INPUT ;
    USE SIGNAL ;
    ANTENNAGATEAREA 0.159000 ;
    PORT
      LAYER met2 ;
        RECT 1807.430 0.000 1807.710 0.280 ;
    END
  END FrameStrobe[185]
  PIN FrameStrobe[186]
    DIRECTION INPUT ;
    USE SIGNAL ;
    ANTENNAGATEAREA 0.159000 ;
    PORT
      LAYER met2 ;
        RECT 1810.190 0.000 1810.470 0.280 ;
    END
  END FrameStrobe[186]
  PIN FrameStrobe[187]
    DIRECTION INPUT ;
    USE SIGNAL ;
    ANTENNAGATEAREA 0.159000 ;
    PORT
      LAYER met2 ;
        RECT 1812.950 0.000 1813.230 0.280 ;
    END
  END FrameStrobe[187]
  PIN FrameStrobe[188]
    DIRECTION INPUT ;
    USE SIGNAL ;
    ANTENNAGATEAREA 0.159000 ;
    PORT
      LAYER met2 ;
        RECT 1815.710 0.000 1815.990 0.280 ;
    END
  END FrameStrobe[188]
  PIN FrameStrobe[189]
    DIRECTION INPUT ;
    USE SIGNAL ;
    ANTENNAGATEAREA 0.159000 ;
    PORT
      LAYER met2 ;
        RECT 1818.470 0.000 1818.750 0.280 ;
    END
  END FrameStrobe[189]
  PIN FrameStrobe[18]
    DIRECTION INPUT ;
    USE SIGNAL ;
    ANTENNAGATEAREA 0.159000 ;
    PORT
      LAYER met2 ;
        RECT 48.390 0.000 48.670 0.280 ;
    END
  END FrameStrobe[18]
  PIN FrameStrobe[190]
    DIRECTION INPUT ;
    USE SIGNAL ;
    ANTENNAGATEAREA 0.159000 ;
    PORT
      LAYER met2 ;
        RECT 1821.230 0.000 1821.510 0.280 ;
    END
  END FrameStrobe[190]
  PIN FrameStrobe[191]
    DIRECTION INPUT ;
    USE SIGNAL ;
    ANTENNAGATEAREA 0.159000 ;
    PORT
      LAYER met2 ;
        RECT 1823.990 0.000 1824.270 0.280 ;
    END
  END FrameStrobe[191]
  PIN FrameStrobe[192]
    DIRECTION INPUT ;
    USE SIGNAL ;
    ANTENNAGATEAREA 0.159000 ;
    PORT
      LAYER met2 ;
        RECT 1826.750 0.000 1827.030 0.280 ;
    END
  END FrameStrobe[192]
  PIN FrameStrobe[193]
    DIRECTION INPUT ;
    USE SIGNAL ;
    ANTENNAGATEAREA 0.159000 ;
    PORT
      LAYER met2 ;
        RECT 1829.510 0.000 1829.790 0.280 ;
    END
  END FrameStrobe[193]
  PIN FrameStrobe[194]
    DIRECTION INPUT ;
    USE SIGNAL ;
    ANTENNAGATEAREA 0.159000 ;
    PORT
      LAYER met2 ;
        RECT 1832.270 0.000 1832.550 0.280 ;
    END
  END FrameStrobe[194]
  PIN FrameStrobe[195]
    DIRECTION INPUT ;
    USE SIGNAL ;
    ANTENNAGATEAREA 0.159000 ;
    PORT
      LAYER met2 ;
        RECT 1835.030 0.000 1835.310 0.280 ;
    END
  END FrameStrobe[195]
  PIN FrameStrobe[196]
    DIRECTION INPUT ;
    USE SIGNAL ;
    ANTENNAGATEAREA 0.159000 ;
    PORT
      LAYER met2 ;
        RECT 1837.790 0.000 1838.070 0.280 ;
    END
  END FrameStrobe[196]
  PIN FrameStrobe[197]
    DIRECTION INPUT ;
    USE SIGNAL ;
    ANTENNAGATEAREA 0.159000 ;
    PORT
      LAYER met2 ;
        RECT 1840.550 0.000 1840.830 0.280 ;
    END
  END FrameStrobe[197]
  PIN FrameStrobe[198]
    DIRECTION INPUT ;
    USE SIGNAL ;
    ANTENNAGATEAREA 0.159000 ;
    PORT
      LAYER met2 ;
        RECT 1843.310 0.000 1843.590 0.280 ;
    END
  END FrameStrobe[198]
  PIN FrameStrobe[199]
    DIRECTION INPUT ;
    USE SIGNAL ;
    ANTENNAGATEAREA 0.159000 ;
    PORT
      LAYER met2 ;
        RECT 1846.070 0.000 1846.350 0.280 ;
    END
  END FrameStrobe[199]
  PIN FrameStrobe[19]
    DIRECTION INPUT ;
    USE SIGNAL ;
    ANTENNAGATEAREA 0.159000 ;
    PORT
      LAYER met2 ;
        RECT 50.690 0.000 50.970 0.280 ;
    END
  END FrameStrobe[19]
  PIN FrameStrobe[1]
    DIRECTION INPUT ;
    USE SIGNAL ;
    ANTENNAGATEAREA 0.159000 ;
    PORT
      LAYER met2 ;
        RECT 9.290 0.000 9.570 0.280 ;
    END
  END FrameStrobe[1]
  PIN FrameStrobe[20]
    DIRECTION INPUT ;
    USE SIGNAL ;
    ANTENNAGATEAREA 1.431000 ;
    PORT
      LAYER met2 ;
        RECT 64.950 0.000 65.230 0.280 ;
    END
  END FrameStrobe[20]
  PIN FrameStrobe[21]
    DIRECTION INPUT ;
    USE SIGNAL ;
    ANTENNAGATEAREA 0.593700 ;
    ANTENNADIFFAREA 0.434700 ;
    PORT
      LAYER met2 ;
        RECT 75.070 0.000 75.350 0.280 ;
    END
  END FrameStrobe[21]
  PIN FrameStrobe[22]
    DIRECTION INPUT ;
    USE SIGNAL ;
    ANTENNAGATEAREA 0.593700 ;
    ANTENNADIFFAREA 0.434700 ;
    PORT
      LAYER met2 ;
        RECT 85.190 0.000 85.470 0.280 ;
    END
  END FrameStrobe[22]
  PIN FrameStrobe[23]
    DIRECTION INPUT ;
    USE SIGNAL ;
    ANTENNAGATEAREA 0.159000 ;
    PORT
      LAYER met2 ;
        RECT 95.310 0.000 95.590 0.280 ;
    END
  END FrameStrobe[23]
  PIN FrameStrobe[24]
    DIRECTION INPUT ;
    USE SIGNAL ;
    ANTENNAGATEAREA 0.159000 ;
    PORT
      LAYER met2 ;
        RECT 105.430 0.000 105.710 0.280 ;
    END
  END FrameStrobe[24]
  PIN FrameStrobe[25]
    DIRECTION INPUT ;
    USE SIGNAL ;
    ANTENNAGATEAREA 0.159000 ;
    PORT
      LAYER met2 ;
        RECT 115.550 0.000 115.830 0.280 ;
    END
  END FrameStrobe[25]
  PIN FrameStrobe[26]
    DIRECTION INPUT ;
    USE SIGNAL ;
    ANTENNAGATEAREA 0.159000 ;
    PORT
      LAYER met2 ;
        RECT 125.670 0.000 125.950 0.280 ;
    END
  END FrameStrobe[26]
  PIN FrameStrobe[27]
    DIRECTION INPUT ;
    USE SIGNAL ;
    ANTENNAGATEAREA 0.159000 ;
    PORT
      LAYER met2 ;
        RECT 135.790 0.000 136.070 0.280 ;
    END
  END FrameStrobe[27]
  PIN FrameStrobe[28]
    DIRECTION INPUT ;
    USE SIGNAL ;
    ANTENNAGATEAREA 0.159000 ;
    PORT
      LAYER met2 ;
        RECT 145.910 0.000 146.190 0.280 ;
    END
  END FrameStrobe[28]
  PIN FrameStrobe[29]
    DIRECTION INPUT ;
    USE SIGNAL ;
    ANTENNAGATEAREA 0.159000 ;
    PORT
      LAYER met2 ;
        RECT 156.030 0.000 156.310 0.280 ;
    END
  END FrameStrobe[29]
  PIN FrameStrobe[2]
    DIRECTION INPUT ;
    USE SIGNAL ;
    ANTENNAGATEAREA 0.159000 ;
    PORT
      LAYER met2 ;
        RECT 11.590 0.000 11.870 0.280 ;
    END
  END FrameStrobe[2]
  PIN FrameStrobe[30]
    DIRECTION INPUT ;
    USE SIGNAL ;
    ANTENNAGATEAREA 0.159000 ;
    PORT
      LAYER met2 ;
        RECT 166.150 0.000 166.430 0.280 ;
    END
  END FrameStrobe[30]
  PIN FrameStrobe[31]
    DIRECTION INPUT ;
    USE SIGNAL ;
    ANTENNAGATEAREA 0.159000 ;
    PORT
      LAYER met2 ;
        RECT 176.270 0.000 176.550 0.280 ;
    END
  END FrameStrobe[31]
  PIN FrameStrobe[32]
    DIRECTION INPUT ;
    USE SIGNAL ;
    ANTENNAGATEAREA 0.159000 ;
    PORT
      LAYER met2 ;
        RECT 186.390 0.000 186.670 0.280 ;
    END
  END FrameStrobe[32]
  PIN FrameStrobe[33]
    DIRECTION INPUT ;
    USE SIGNAL ;
    ANTENNAGATEAREA 0.159000 ;
    PORT
      LAYER met2 ;
        RECT 196.510 0.000 196.790 0.280 ;
    END
  END FrameStrobe[33]
  PIN FrameStrobe[34]
    DIRECTION INPUT ;
    USE SIGNAL ;
    ANTENNAGATEAREA 0.159000 ;
    PORT
      LAYER met2 ;
        RECT 206.630 0.000 206.910 0.280 ;
    END
  END FrameStrobe[34]
  PIN FrameStrobe[35]
    DIRECTION INPUT ;
    USE SIGNAL ;
    ANTENNAGATEAREA 0.159000 ;
    PORT
      LAYER met2 ;
        RECT 216.750 0.000 217.030 0.280 ;
    END
  END FrameStrobe[35]
  PIN FrameStrobe[36]
    DIRECTION INPUT ;
    USE SIGNAL ;
    ANTENNAGATEAREA 0.159000 ;
    PORT
      LAYER met2 ;
        RECT 226.870 0.000 227.150 0.280 ;
    END
  END FrameStrobe[36]
  PIN FrameStrobe[37]
    DIRECTION INPUT ;
    USE SIGNAL ;
    ANTENNAGATEAREA 0.159000 ;
    PORT
      LAYER met2 ;
        RECT 236.990 0.000 237.270 0.280 ;
    END
  END FrameStrobe[37]
  PIN FrameStrobe[38]
    DIRECTION INPUT ;
    USE SIGNAL ;
    ANTENNAGATEAREA 0.159000 ;
    PORT
      LAYER met2 ;
        RECT 247.110 0.000 247.390 0.280 ;
    END
  END FrameStrobe[38]
  PIN FrameStrobe[39]
    DIRECTION INPUT ;
    USE SIGNAL ;
    ANTENNAGATEAREA 0.159000 ;
    PORT
      LAYER met2 ;
        RECT 257.230 0.000 257.510 0.280 ;
    END
  END FrameStrobe[39]
  PIN FrameStrobe[3]
    DIRECTION INPUT ;
    USE SIGNAL ;
    ANTENNAGATEAREA 0.159000 ;
    PORT
      LAYER met2 ;
        RECT 13.890 0.000 14.170 0.280 ;
    END
  END FrameStrobe[3]
  PIN FrameStrobe[40]
    DIRECTION INPUT ;
    USE SIGNAL ;
    ANTENNAGATEAREA 1.431000 ;
    PORT
      LAYER met2 ;
        RECT 275.630 0.000 275.910 0.280 ;
    END
  END FrameStrobe[40]
  PIN FrameStrobe[41]
    DIRECTION INPUT ;
    USE SIGNAL ;
    ANTENNAGATEAREA 0.593700 ;
    ANTENNADIFFAREA 0.434700 ;
    PORT
      LAYER met2 ;
        RECT 285.750 0.000 286.030 0.280 ;
    END
  END FrameStrobe[41]
  PIN FrameStrobe[42]
    DIRECTION INPUT ;
    USE SIGNAL ;
    ANTENNAGATEAREA 0.593700 ;
    ANTENNADIFFAREA 0.434700 ;
    PORT
      LAYER met2 ;
        RECT 295.870 0.000 296.150 0.280 ;
    END
  END FrameStrobe[42]
  PIN FrameStrobe[43]
    DIRECTION INPUT ;
    USE SIGNAL ;
    ANTENNAGATEAREA 0.159000 ;
    PORT
      LAYER met2 ;
        RECT 305.990 0.000 306.270 0.280 ;
    END
  END FrameStrobe[43]
  PIN FrameStrobe[44]
    DIRECTION INPUT ;
    USE SIGNAL ;
    ANTENNAGATEAREA 0.159000 ;
    PORT
      LAYER met2 ;
        RECT 316.110 0.000 316.390 0.280 ;
    END
  END FrameStrobe[44]
  PIN FrameStrobe[45]
    DIRECTION INPUT ;
    USE SIGNAL ;
    ANTENNAGATEAREA 0.159000 ;
    PORT
      LAYER met2 ;
        RECT 326.230 0.000 326.510 0.280 ;
    END
  END FrameStrobe[45]
  PIN FrameStrobe[46]
    DIRECTION INPUT ;
    USE SIGNAL ;
    ANTENNAGATEAREA 0.159000 ;
    PORT
      LAYER met2 ;
        RECT 336.350 0.000 336.630 0.280 ;
    END
  END FrameStrobe[46]
  PIN FrameStrobe[47]
    DIRECTION INPUT ;
    USE SIGNAL ;
    ANTENNAGATEAREA 0.159000 ;
    PORT
      LAYER met2 ;
        RECT 346.470 0.000 346.750 0.280 ;
    END
  END FrameStrobe[47]
  PIN FrameStrobe[48]
    DIRECTION INPUT ;
    USE SIGNAL ;
    ANTENNAGATEAREA 0.159000 ;
    PORT
      LAYER met2 ;
        RECT 356.590 0.000 356.870 0.280 ;
    END
  END FrameStrobe[48]
  PIN FrameStrobe[49]
    DIRECTION INPUT ;
    USE SIGNAL ;
    ANTENNAGATEAREA 0.159000 ;
    PORT
      LAYER met2 ;
        RECT 366.710 0.000 366.990 0.280 ;
    END
  END FrameStrobe[49]
  PIN FrameStrobe[4]
    DIRECTION INPUT ;
    USE SIGNAL ;
    ANTENNAGATEAREA 0.159000 ;
    PORT
      LAYER met2 ;
        RECT 16.190 0.000 16.470 0.280 ;
    END
  END FrameStrobe[4]
  PIN FrameStrobe[50]
    DIRECTION INPUT ;
    USE SIGNAL ;
    ANTENNAGATEAREA 0.159000 ;
    PORT
      LAYER met2 ;
        RECT 376.830 0.000 377.110 0.280 ;
    END
  END FrameStrobe[50]
  PIN FrameStrobe[51]
    DIRECTION INPUT ;
    USE SIGNAL ;
    ANTENNAGATEAREA 0.159000 ;
    PORT
      LAYER met2 ;
        RECT 386.950 0.000 387.230 0.280 ;
    END
  END FrameStrobe[51]
  PIN FrameStrobe[52]
    DIRECTION INPUT ;
    USE SIGNAL ;
    ANTENNAGATEAREA 0.159000 ;
    PORT
      LAYER met2 ;
        RECT 397.070 0.000 397.350 0.280 ;
    END
  END FrameStrobe[52]
  PIN FrameStrobe[53]
    DIRECTION INPUT ;
    USE SIGNAL ;
    ANTENNAGATEAREA 0.159000 ;
    PORT
      LAYER met2 ;
        RECT 407.190 0.000 407.470 0.280 ;
    END
  END FrameStrobe[53]
  PIN FrameStrobe[54]
    DIRECTION INPUT ;
    USE SIGNAL ;
    ANTENNAGATEAREA 0.159000 ;
    PORT
      LAYER met2 ;
        RECT 417.310 0.000 417.590 0.280 ;
    END
  END FrameStrobe[54]
  PIN FrameStrobe[55]
    DIRECTION INPUT ;
    USE SIGNAL ;
    ANTENNAGATEAREA 0.159000 ;
    PORT
      LAYER met2 ;
        RECT 427.430 0.000 427.710 0.280 ;
    END
  END FrameStrobe[55]
  PIN FrameStrobe[56]
    DIRECTION INPUT ;
    USE SIGNAL ;
    ANTENNAGATEAREA 0.159000 ;
    PORT
      LAYER met2 ;
        RECT 437.550 0.000 437.830 0.280 ;
    END
  END FrameStrobe[56]
  PIN FrameStrobe[57]
    DIRECTION INPUT ;
    USE SIGNAL ;
    ANTENNAGATEAREA 0.159000 ;
    PORT
      LAYER met2 ;
        RECT 447.670 0.000 447.950 0.280 ;
    END
  END FrameStrobe[57]
  PIN FrameStrobe[58]
    DIRECTION INPUT ;
    USE SIGNAL ;
    ANTENNAGATEAREA 0.159000 ;
    PORT
      LAYER met2 ;
        RECT 457.790 0.000 458.070 0.280 ;
    END
  END FrameStrobe[58]
  PIN FrameStrobe[59]
    DIRECTION INPUT ;
    USE SIGNAL ;
    ANTENNAGATEAREA 0.159000 ;
    PORT
      LAYER met2 ;
        RECT 467.910 0.000 468.190 0.280 ;
    END
  END FrameStrobe[59]
  PIN FrameStrobe[5]
    DIRECTION INPUT ;
    USE SIGNAL ;
    ANTENNAGATEAREA 0.159000 ;
    PORT
      LAYER met2 ;
        RECT 18.490 0.000 18.770 0.280 ;
    END
  END FrameStrobe[5]
  PIN FrameStrobe[60]
    DIRECTION INPUT ;
    USE SIGNAL ;
    ANTENNAGATEAREA 1.431000 ;
    PORT
      LAYER met2 ;
        RECT 485.390 0.000 485.670 0.280 ;
    END
  END FrameStrobe[60]
  PIN FrameStrobe[61]
    DIRECTION INPUT ;
    USE SIGNAL ;
    ANTENNAGATEAREA 0.159000 ;
    PORT
      LAYER met2 ;
        RECT 497.810 0.000 498.090 0.280 ;
    END
  END FrameStrobe[61]
  PIN FrameStrobe[62]
    DIRECTION INPUT ;
    USE SIGNAL ;
    ANTENNAGATEAREA 0.593700 ;
    ANTENNADIFFAREA 0.434700 ;
    PORT
      LAYER met2 ;
        RECT 510.230 0.000 510.510 0.280 ;
    END
  END FrameStrobe[62]
  PIN FrameStrobe[63]
    DIRECTION INPUT ;
    USE SIGNAL ;
    ANTENNAGATEAREA 0.593700 ;
    ANTENNADIFFAREA 0.434700 ;
    PORT
      LAYER met2 ;
        RECT 522.650 0.000 522.930 0.280 ;
    END
  END FrameStrobe[63]
  PIN FrameStrobe[64]
    DIRECTION INPUT ;
    USE SIGNAL ;
    ANTENNAGATEAREA 0.159000 ;
    PORT
      LAYER met2 ;
        RECT 535.070 0.000 535.350 0.280 ;
    END
  END FrameStrobe[64]
  PIN FrameStrobe[65]
    DIRECTION INPUT ;
    USE SIGNAL ;
    ANTENNAGATEAREA 0.159000 ;
    PORT
      LAYER met2 ;
        RECT 547.490 0.000 547.770 0.280 ;
    END
  END FrameStrobe[65]
  PIN FrameStrobe[66]
    DIRECTION INPUT ;
    USE SIGNAL ;
    ANTENNAGATEAREA 0.593700 ;
    ANTENNADIFFAREA 0.434700 ;
    PORT
      LAYER met2 ;
        RECT 559.910 0.000 560.190 0.280 ;
    END
  END FrameStrobe[66]
  PIN FrameStrobe[67]
    DIRECTION INPUT ;
    USE SIGNAL ;
    ANTENNAGATEAREA 0.159000 ;
    PORT
      LAYER met2 ;
        RECT 572.330 0.000 572.610 0.280 ;
    END
  END FrameStrobe[67]
  PIN FrameStrobe[68]
    DIRECTION INPUT ;
    USE SIGNAL ;
    ANTENNAGATEAREA 0.159000 ;
    PORT
      LAYER met2 ;
        RECT 584.750 0.000 585.030 0.280 ;
    END
  END FrameStrobe[68]
  PIN FrameStrobe[69]
    DIRECTION INPUT ;
    USE SIGNAL ;
    ANTENNAGATEAREA 0.593700 ;
    ANTENNADIFFAREA 0.434700 ;
    PORT
      LAYER met2 ;
        RECT 597.170 0.000 597.450 0.280 ;
    END
  END FrameStrobe[69]
  PIN FrameStrobe[6]
    DIRECTION INPUT ;
    USE SIGNAL ;
    ANTENNAGATEAREA 0.159000 ;
    PORT
      LAYER met2 ;
        RECT 20.790 0.000 21.070 0.280 ;
    END
  END FrameStrobe[6]
  PIN FrameStrobe[70]
    DIRECTION INPUT ;
    USE SIGNAL ;
    ANTENNAGATEAREA 0.159000 ;
    PORT
      LAYER met2 ;
        RECT 609.590 0.000 609.870 0.280 ;
    END
  END FrameStrobe[70]
  PIN FrameStrobe[71]
    DIRECTION INPUT ;
    USE SIGNAL ;
    ANTENNAGATEAREA 0.159000 ;
    PORT
      LAYER met2 ;
        RECT 622.010 0.000 622.290 0.280 ;
    END
  END FrameStrobe[71]
  PIN FrameStrobe[72]
    DIRECTION INPUT ;
    USE SIGNAL ;
    ANTENNAGATEAREA 0.159000 ;
    PORT
      LAYER met2 ;
        RECT 634.430 0.000 634.710 0.280 ;
    END
  END FrameStrobe[72]
  PIN FrameStrobe[73]
    DIRECTION INPUT ;
    USE SIGNAL ;
    ANTENNAGATEAREA 0.159000 ;
    PORT
      LAYER met2 ;
        RECT 646.850 0.000 647.130 0.280 ;
    END
  END FrameStrobe[73]
  PIN FrameStrobe[74]
    DIRECTION INPUT ;
    USE SIGNAL ;
    ANTENNAGATEAREA 0.159000 ;
    PORT
      LAYER met2 ;
        RECT 659.270 0.000 659.550 0.280 ;
    END
  END FrameStrobe[74]
  PIN FrameStrobe[75]
    DIRECTION INPUT ;
    USE SIGNAL ;
    ANTENNAGATEAREA 0.159000 ;
    PORT
      LAYER met2 ;
        RECT 671.690 0.000 671.970 0.280 ;
    END
  END FrameStrobe[75]
  PIN FrameStrobe[76]
    DIRECTION INPUT ;
    USE SIGNAL ;
    ANTENNAGATEAREA 0.159000 ;
    PORT
      LAYER met2 ;
        RECT 684.110 0.000 684.390 0.280 ;
    END
  END FrameStrobe[76]
  PIN FrameStrobe[77]
    DIRECTION INPUT ;
    USE SIGNAL ;
    ANTENNAGATEAREA 0.159000 ;
    PORT
      LAYER met2 ;
        RECT 696.530 0.000 696.810 0.280 ;
    END
  END FrameStrobe[77]
  PIN FrameStrobe[78]
    DIRECTION INPUT ;
    USE SIGNAL ;
    ANTENNAGATEAREA 0.159000 ;
    PORT
      LAYER met2 ;
        RECT 708.950 0.000 709.230 0.280 ;
    END
  END FrameStrobe[78]
  PIN FrameStrobe[79]
    DIRECTION INPUT ;
    USE SIGNAL ;
    ANTENNAGATEAREA 0.159000 ;
    PORT
      LAYER met2 ;
        RECT 721.370 0.000 721.650 0.280 ;
    END
  END FrameStrobe[79]
  PIN FrameStrobe[7]
    DIRECTION INPUT ;
    USE SIGNAL ;
    ANTENNAGATEAREA 0.159000 ;
    PORT
      LAYER met2 ;
        RECT 23.090 0.000 23.370 0.280 ;
    END
  END FrameStrobe[7]
  PIN FrameStrobe[80]
    DIRECTION INPUT ;
    USE SIGNAL ;
    ANTENNAGATEAREA 1.431000 ;
    PORT
      LAYER met2 ;
        RECT 738.390 0.000 738.670 0.280 ;
    END
  END FrameStrobe[80]
  PIN FrameStrobe[81]
    DIRECTION INPUT ;
    USE SIGNAL ;
    ANTENNAGATEAREA 0.593700 ;
    ANTENNADIFFAREA 0.434700 ;
    PORT
      LAYER met2 ;
        RECT 748.510 0.000 748.790 0.280 ;
    END
  END FrameStrobe[81]
  PIN FrameStrobe[82]
    DIRECTION INPUT ;
    USE SIGNAL ;
    ANTENNAGATEAREA 0.593700 ;
    ANTENNADIFFAREA 0.434700 ;
    PORT
      LAYER met2 ;
        RECT 758.630 0.000 758.910 0.280 ;
    END
  END FrameStrobe[82]
  PIN FrameStrobe[83]
    DIRECTION INPUT ;
    USE SIGNAL ;
    ANTENNAGATEAREA 0.159000 ;
    PORT
      LAYER met2 ;
        RECT 768.750 0.000 769.030 0.280 ;
    END
  END FrameStrobe[83]
  PIN FrameStrobe[84]
    DIRECTION INPUT ;
    USE SIGNAL ;
    ANTENNAGATEAREA 0.159000 ;
    PORT
      LAYER met2 ;
        RECT 778.870 0.000 779.150 0.280 ;
    END
  END FrameStrobe[84]
  PIN FrameStrobe[85]
    DIRECTION INPUT ;
    USE SIGNAL ;
    ANTENNAGATEAREA 0.159000 ;
    PORT
      LAYER met2 ;
        RECT 788.990 0.000 789.270 0.280 ;
    END
  END FrameStrobe[85]
  PIN FrameStrobe[86]
    DIRECTION INPUT ;
    USE SIGNAL ;
    ANTENNAGATEAREA 0.159000 ;
    PORT
      LAYER met2 ;
        RECT 799.110 0.000 799.390 0.280 ;
    END
  END FrameStrobe[86]
  PIN FrameStrobe[87]
    DIRECTION INPUT ;
    USE SIGNAL ;
    ANTENNAGATEAREA 0.159000 ;
    PORT
      LAYER met2 ;
        RECT 809.230 0.000 809.510 0.280 ;
    END
  END FrameStrobe[87]
  PIN FrameStrobe[88]
    DIRECTION INPUT ;
    USE SIGNAL ;
    ANTENNAGATEAREA 0.159000 ;
    PORT
      LAYER met2 ;
        RECT 819.350 0.000 819.630 0.280 ;
    END
  END FrameStrobe[88]
  PIN FrameStrobe[89]
    DIRECTION INPUT ;
    USE SIGNAL ;
    ANTENNAGATEAREA 0.159000 ;
    PORT
      LAYER met2 ;
        RECT 829.470 0.000 829.750 0.280 ;
    END
  END FrameStrobe[89]
  PIN FrameStrobe[8]
    DIRECTION INPUT ;
    USE SIGNAL ;
    ANTENNAGATEAREA 0.159000 ;
    PORT
      LAYER met2 ;
        RECT 25.390 0.000 25.670 0.280 ;
    END
  END FrameStrobe[8]
  PIN FrameStrobe[90]
    DIRECTION INPUT ;
    USE SIGNAL ;
    ANTENNAGATEAREA 0.159000 ;
    PORT
      LAYER met2 ;
        RECT 839.590 0.000 839.870 0.280 ;
    END
  END FrameStrobe[90]
  PIN FrameStrobe[91]
    DIRECTION INPUT ;
    USE SIGNAL ;
    ANTENNAGATEAREA 0.159000 ;
    PORT
      LAYER met2 ;
        RECT 849.710 0.000 849.990 0.280 ;
    END
  END FrameStrobe[91]
  PIN FrameStrobe[92]
    DIRECTION INPUT ;
    USE SIGNAL ;
    ANTENNAGATEAREA 0.159000 ;
    PORT
      LAYER met2 ;
        RECT 859.830 0.000 860.110 0.280 ;
    END
  END FrameStrobe[92]
  PIN FrameStrobe[93]
    DIRECTION INPUT ;
    USE SIGNAL ;
    ANTENNAGATEAREA 0.159000 ;
    PORT
      LAYER met2 ;
        RECT 869.950 0.000 870.230 0.280 ;
    END
  END FrameStrobe[93]
  PIN FrameStrobe[94]
    DIRECTION INPUT ;
    USE SIGNAL ;
    ANTENNAGATEAREA 0.159000 ;
    PORT
      LAYER met2 ;
        RECT 880.070 0.000 880.350 0.280 ;
    END
  END FrameStrobe[94]
  PIN FrameStrobe[95]
    DIRECTION INPUT ;
    USE SIGNAL ;
    ANTENNAGATEAREA 0.159000 ;
    PORT
      LAYER met2 ;
        RECT 890.190 0.000 890.470 0.280 ;
    END
  END FrameStrobe[95]
  PIN FrameStrobe[96]
    DIRECTION INPUT ;
    USE SIGNAL ;
    ANTENNAGATEAREA 0.159000 ;
    PORT
      LAYER met2 ;
        RECT 900.310 0.000 900.590 0.280 ;
    END
  END FrameStrobe[96]
  PIN FrameStrobe[97]
    DIRECTION INPUT ;
    USE SIGNAL ;
    ANTENNAGATEAREA 0.159000 ;
    PORT
      LAYER met2 ;
        RECT 910.430 0.000 910.710 0.280 ;
    END
  END FrameStrobe[97]
  PIN FrameStrobe[98]
    DIRECTION INPUT ;
    USE SIGNAL ;
    ANTENNAGATEAREA 0.159000 ;
    PORT
      LAYER met2 ;
        RECT 920.550 0.000 920.830 0.280 ;
    END
  END FrameStrobe[98]
  PIN FrameStrobe[99]
    DIRECTION INPUT ;
    USE SIGNAL ;
    ANTENNAGATEAREA 0.159000 ;
    PORT
      LAYER met2 ;
        RECT 930.670 0.000 930.950 0.280 ;
    END
  END FrameStrobe[99]
  PIN FrameStrobe[9]
    DIRECTION INPUT ;
    USE SIGNAL ;
    ANTENNAGATEAREA 0.159000 ;
    PORT
      LAYER met2 ;
        RECT 27.690 0.000 27.970 0.280 ;
    END
  END FrameStrobe[9]
  PIN Tile_X0Y1_A_EN_top
    DIRECTION OUTPUT ;
    USE SIGNAL ;
    ANTENNADIFFAREA 0.702900 ;
    PORT
      LAYER met3 ;
        RECT 0.000 1192.760 0.600 1193.360 ;
    END
  END Tile_X0Y1_A_EN_top
  PIN Tile_X0Y1_A_IN_top
    DIRECTION OUTPUT ;
    USE SIGNAL ;
    ANTENNADIFFAREA 0.702900 ;
    PORT
      LAYER met3 ;
        RECT 0.000 1187.320 0.600 1187.920 ;
    END
  END Tile_X0Y1_A_IN_top
  PIN Tile_X0Y1_A_OUT_top
    DIRECTION INPUT ;
    USE SIGNAL ;
    ANTENNAGATEAREA 0.252000 ;
    PORT
      LAYER met3 ;
        RECT 0.000 1181.880 0.600 1182.480 ;
    END
  END Tile_X0Y1_A_OUT_top
  PIN Tile_X0Y1_B_EN_top
    DIRECTION OUTPUT ;
    USE SIGNAL ;
    ANTENNADIFFAREA 0.702900 ;
    PORT
      LAYER met3 ;
        RECT 0.000 1209.080 0.600 1209.680 ;
    END
  END Tile_X0Y1_B_EN_top
  PIN Tile_X0Y1_B_IN_top
    DIRECTION OUTPUT ;
    USE SIGNAL ;
    ANTENNADIFFAREA 0.702900 ;
    PORT
      LAYER met3 ;
        RECT 0.000 1203.640 0.600 1204.240 ;
    END
  END Tile_X0Y1_B_IN_top
  PIN Tile_X0Y1_B_OUT_top
    DIRECTION INPUT ;
    USE SIGNAL ;
    ANTENNAGATEAREA 0.252000 ;
    PORT
      LAYER met3 ;
        RECT 0.000 1198.200 0.600 1198.800 ;
    END
  END Tile_X0Y1_B_OUT_top
  PIN Tile_X0Y2_A_EN_top
    DIRECTION OUTPUT ;
    USE SIGNAL ;
    ANTENNADIFFAREA 0.702900 ;
    PORT
      LAYER met3 ;
        RECT 0.000 969.720 0.600 970.320 ;
    END
  END Tile_X0Y2_A_EN_top
  PIN Tile_X0Y2_A_IN_top
    DIRECTION OUTPUT ;
    USE SIGNAL ;
    ANTENNADIFFAREA 0.702900 ;
    PORT
      LAYER met3 ;
        RECT 0.000 964.280 0.600 964.880 ;
    END
  END Tile_X0Y2_A_IN_top
  PIN Tile_X0Y2_A_OUT_top
    DIRECTION INPUT ;
    USE SIGNAL ;
    ANTENNAGATEAREA 0.252000 ;
    PORT
      LAYER met3 ;
        RECT 0.000 958.840 0.600 959.440 ;
    END
  END Tile_X0Y2_A_OUT_top
  PIN Tile_X0Y2_B_EN_top
    DIRECTION OUTPUT ;
    USE SIGNAL ;
    ANTENNADIFFAREA 0.702900 ;
    PORT
      LAYER met3 ;
        RECT 0.000 986.040 0.600 986.640 ;
    END
  END Tile_X0Y2_B_EN_top
  PIN Tile_X0Y2_B_IN_top
    DIRECTION OUTPUT ;
    USE SIGNAL ;
    ANTENNADIFFAREA 0.702900 ;
    PORT
      LAYER met3 ;
        RECT 0.000 980.600 0.600 981.200 ;
    END
  END Tile_X0Y2_B_IN_top
  PIN Tile_X0Y2_B_OUT_top
    DIRECTION INPUT ;
    USE SIGNAL ;
    ANTENNAGATEAREA 0.252000 ;
    PORT
      LAYER met3 ;
        RECT 0.000 975.160 0.600 975.760 ;
    END
  END Tile_X0Y2_B_OUT_top
  PIN Tile_X0Y3_A_EN_top
    DIRECTION OUTPUT ;
    USE SIGNAL ;
    ANTENNADIFFAREA 0.702900 ;
    PORT
      LAYER met3 ;
        RECT 0.000 746.680 0.600 747.280 ;
    END
  END Tile_X0Y3_A_EN_top
  PIN Tile_X0Y3_A_IN_top
    DIRECTION OUTPUT ;
    USE SIGNAL ;
    ANTENNADIFFAREA 0.702900 ;
    PORT
      LAYER met3 ;
        RECT 0.000 741.240 0.600 741.840 ;
    END
  END Tile_X0Y3_A_IN_top
  PIN Tile_X0Y3_A_OUT_top
    DIRECTION INPUT ;
    USE SIGNAL ;
    ANTENNAGATEAREA 0.252000 ;
    PORT
      LAYER met3 ;
        RECT 0.000 735.800 0.600 736.400 ;
    END
  END Tile_X0Y3_A_OUT_top
  PIN Tile_X0Y3_B_EN_top
    DIRECTION OUTPUT ;
    USE SIGNAL ;
    ANTENNADIFFAREA 0.702900 ;
    PORT
      LAYER met3 ;
        RECT 0.000 763.000 0.600 763.600 ;
    END
  END Tile_X0Y3_B_EN_top
  PIN Tile_X0Y3_B_IN_top
    DIRECTION OUTPUT ;
    USE SIGNAL ;
    ANTENNADIFFAREA 0.702900 ;
    PORT
      LAYER met3 ;
        RECT 0.000 757.560 0.600 758.160 ;
    END
  END Tile_X0Y3_B_IN_top
  PIN Tile_X0Y3_B_OUT_top
    DIRECTION INPUT ;
    USE SIGNAL ;
    ANTENNAGATEAREA 0.252000 ;
    PORT
      LAYER met3 ;
        RECT 0.000 752.120 0.600 752.720 ;
    END
  END Tile_X0Y3_B_OUT_top
  PIN Tile_X0Y4_A_EN_top
    DIRECTION OUTPUT ;
    USE SIGNAL ;
    ANTENNADIFFAREA 0.702900 ;
    PORT
      LAYER met3 ;
        RECT 0.000 523.640 0.600 524.240 ;
    END
  END Tile_X0Y4_A_EN_top
  PIN Tile_X0Y4_A_IN_top
    DIRECTION OUTPUT ;
    USE SIGNAL ;
    ANTENNADIFFAREA 0.702900 ;
    PORT
      LAYER met3 ;
        RECT 0.000 518.200 0.600 518.800 ;
    END
  END Tile_X0Y4_A_IN_top
  PIN Tile_X0Y4_A_OUT_top
    DIRECTION INPUT ;
    USE SIGNAL ;
    ANTENNAGATEAREA 0.252000 ;
    PORT
      LAYER met3 ;
        RECT 0.000 512.760 0.600 513.360 ;
    END
  END Tile_X0Y4_A_OUT_top
  PIN Tile_X0Y4_B_EN_top
    DIRECTION OUTPUT ;
    USE SIGNAL ;
    ANTENNADIFFAREA 0.702900 ;
    PORT
      LAYER met3 ;
        RECT 0.000 539.960 0.600 540.560 ;
    END
  END Tile_X0Y4_B_EN_top
  PIN Tile_X0Y4_B_IN_top
    DIRECTION OUTPUT ;
    USE SIGNAL ;
    ANTENNADIFFAREA 0.702900 ;
    PORT
      LAYER met3 ;
        RECT 0.000 534.520 0.600 535.120 ;
    END
  END Tile_X0Y4_B_IN_top
  PIN Tile_X0Y4_B_OUT_top
    DIRECTION INPUT ;
    USE SIGNAL ;
    ANTENNAGATEAREA 0.252000 ;
    PORT
      LAYER met3 ;
        RECT 0.000 529.080 0.600 529.680 ;
    END
  END Tile_X0Y4_B_OUT_top
  PIN Tile_X0Y5_A_EN_top
    DIRECTION OUTPUT ;
    USE SIGNAL ;
    ANTENNADIFFAREA 0.702900 ;
    PORT
      LAYER met3 ;
        RECT 0.000 300.600 0.600 301.200 ;
    END
  END Tile_X0Y5_A_EN_top
  PIN Tile_X0Y5_A_IN_top
    DIRECTION OUTPUT ;
    USE SIGNAL ;
    ANTENNADIFFAREA 0.702900 ;
    PORT
      LAYER met3 ;
        RECT 0.000 295.160 0.600 295.760 ;
    END
  END Tile_X0Y5_A_IN_top
  PIN Tile_X0Y5_A_OUT_top
    DIRECTION INPUT ;
    USE SIGNAL ;
    ANTENNAGATEAREA 0.252000 ;
    PORT
      LAYER met3 ;
        RECT 0.000 289.720 0.600 290.320 ;
    END
  END Tile_X0Y5_A_OUT_top
  PIN Tile_X0Y5_B_EN_top
    DIRECTION OUTPUT ;
    USE SIGNAL ;
    ANTENNADIFFAREA 0.702900 ;
    PORT
      LAYER met3 ;
        RECT 0.000 316.920 0.600 317.520 ;
    END
  END Tile_X0Y5_B_EN_top
  PIN Tile_X0Y5_B_IN_top
    DIRECTION OUTPUT ;
    USE SIGNAL ;
    ANTENNADIFFAREA 0.702900 ;
    PORT
      LAYER met3 ;
        RECT 0.000 311.480 0.600 312.080 ;
    END
  END Tile_X0Y5_B_IN_top
  PIN Tile_X0Y5_B_OUT_top
    DIRECTION INPUT ;
    USE SIGNAL ;
    ANTENNAGATEAREA 0.252000 ;
    PORT
      LAYER met3 ;
        RECT 0.000 306.040 0.600 306.640 ;
    END
  END Tile_X0Y5_B_OUT_top
  PIN Tile_X0Y6_A_EN_top
    DIRECTION OUTPUT ;
    USE SIGNAL ;
    ANTENNADIFFAREA 0.702900 ;
    PORT
      LAYER met3 ;
        RECT 0.000 77.560 0.600 78.160 ;
    END
  END Tile_X0Y6_A_EN_top
  PIN Tile_X0Y6_A_IN_top
    DIRECTION OUTPUT ;
    USE SIGNAL ;
    ANTENNADIFFAREA 0.702900 ;
    PORT
      LAYER met3 ;
        RECT 0.000 72.120 0.600 72.720 ;
    END
  END Tile_X0Y6_A_IN_top
  PIN Tile_X0Y6_A_OUT_top
    DIRECTION INPUT ;
    USE SIGNAL ;
    ANTENNAGATEAREA 0.252000 ;
    PORT
      LAYER met3 ;
        RECT 0.000 66.680 0.600 67.280 ;
    END
  END Tile_X0Y6_A_OUT_top
  PIN Tile_X0Y6_B_EN_top
    DIRECTION OUTPUT ;
    USE SIGNAL ;
    ANTENNADIFFAREA 0.702900 ;
    PORT
      LAYER met3 ;
        RECT 0.000 93.880 0.600 94.480 ;
    END
  END Tile_X0Y6_B_EN_top
  PIN Tile_X0Y6_B_IN_top
    DIRECTION OUTPUT ;
    USE SIGNAL ;
    ANTENNADIFFAREA 0.702900 ;
    PORT
      LAYER met3 ;
        RECT 0.000 88.440 0.600 89.040 ;
    END
  END Tile_X0Y6_B_IN_top
  PIN Tile_X0Y6_B_OUT_top
    DIRECTION INPUT ;
    USE SIGNAL ;
    ANTENNAGATEAREA 0.252000 ;
    PORT
      LAYER met3 ;
        RECT 0.000 83.000 0.600 83.600 ;
    END
  END Tile_X0Y6_B_OUT_top
  PIN Tile_X0Y7_SYS_RESET_RESET_top
    DIRECTION INPUT ;
    USE SIGNAL ;
    ANTENNAGATEAREA 0.621000 ;
    PORT
      LAYER met2 ;
        RECT 4.690 0.000 4.970 0.280 ;
    END
  END Tile_X0Y7_SYS_RESET_RESET_top
  PIN Tile_X9Y1_A_EN_top
    DIRECTION OUTPUT ;
    USE SIGNAL ;
    ANTENNADIFFAREA 0.702900 ;
    PORT
      LAYER met3 ;
        RECT 1847.680 1192.760 1848.280 1193.360 ;
    END
  END Tile_X9Y1_A_EN_top
  PIN Tile_X9Y1_A_IN_top
    DIRECTION OUTPUT ;
    USE SIGNAL ;
    ANTENNADIFFAREA 0.702900 ;
    PORT
      LAYER met3 ;
        RECT 1847.680 1187.320 1848.280 1187.920 ;
    END
  END Tile_X9Y1_A_IN_top
  PIN Tile_X9Y1_A_OUT_top
    DIRECTION INPUT ;
    USE SIGNAL ;
    ANTENNAGATEAREA 0.252000 ;
    PORT
      LAYER met3 ;
        RECT 1847.680 1181.880 1848.280 1182.480 ;
    END
  END Tile_X9Y1_A_OUT_top
  PIN Tile_X9Y1_B_EN_top
    DIRECTION OUTPUT ;
    USE SIGNAL ;
    ANTENNADIFFAREA 0.702900 ;
    PORT
      LAYER met3 ;
        RECT 1847.680 1209.080 1848.280 1209.680 ;
    END
  END Tile_X9Y1_B_EN_top
  PIN Tile_X9Y1_B_IN_top
    DIRECTION OUTPUT ;
    USE SIGNAL ;
    ANTENNADIFFAREA 0.702900 ;
    PORT
      LAYER met3 ;
        RECT 1847.680 1203.640 1848.280 1204.240 ;
    END
  END Tile_X9Y1_B_IN_top
  PIN Tile_X9Y1_B_OUT_top
    DIRECTION INPUT ;
    USE SIGNAL ;
    ANTENNAGATEAREA 0.252000 ;
    PORT
      LAYER met3 ;
        RECT 1847.680 1198.200 1848.280 1198.800 ;
    END
  END Tile_X9Y1_B_OUT_top
  PIN Tile_X9Y2_A_EN_top
    DIRECTION OUTPUT ;
    USE SIGNAL ;
    ANTENNADIFFAREA 0.702900 ;
    PORT
      LAYER met3 ;
        RECT 1847.680 969.720 1848.280 970.320 ;
    END
  END Tile_X9Y2_A_EN_top
  PIN Tile_X9Y2_A_IN_top
    DIRECTION OUTPUT ;
    USE SIGNAL ;
    ANTENNADIFFAREA 0.702900 ;
    PORT
      LAYER met3 ;
        RECT 1847.680 964.280 1848.280 964.880 ;
    END
  END Tile_X9Y2_A_IN_top
  PIN Tile_X9Y2_A_OUT_top
    DIRECTION INPUT ;
    USE SIGNAL ;
    ANTENNAGATEAREA 0.252000 ;
    PORT
      LAYER met3 ;
        RECT 1847.680 958.840 1848.280 959.440 ;
    END
  END Tile_X9Y2_A_OUT_top
  PIN Tile_X9Y2_B_EN_top
    DIRECTION OUTPUT ;
    USE SIGNAL ;
    ANTENNADIFFAREA 0.702900 ;
    PORT
      LAYER met3 ;
        RECT 1847.680 986.040 1848.280 986.640 ;
    END
  END Tile_X9Y2_B_EN_top
  PIN Tile_X9Y2_B_IN_top
    DIRECTION OUTPUT ;
    USE SIGNAL ;
    ANTENNADIFFAREA 0.702900 ;
    PORT
      LAYER met3 ;
        RECT 1847.680 980.600 1848.280 981.200 ;
    END
  END Tile_X9Y2_B_IN_top
  PIN Tile_X9Y2_B_OUT_top
    DIRECTION INPUT ;
    USE SIGNAL ;
    ANTENNAGATEAREA 0.252000 ;
    PORT
      LAYER met3 ;
        RECT 1847.680 975.160 1848.280 975.760 ;
    END
  END Tile_X9Y2_B_OUT_top
  PIN Tile_X9Y3_A_EN_top
    DIRECTION OUTPUT ;
    USE SIGNAL ;
    ANTENNADIFFAREA 0.702900 ;
    PORT
      LAYER met3 ;
        RECT 1847.680 746.680 1848.280 747.280 ;
    END
  END Tile_X9Y3_A_EN_top
  PIN Tile_X9Y3_A_IN_top
    DIRECTION OUTPUT ;
    USE SIGNAL ;
    ANTENNADIFFAREA 0.702900 ;
    PORT
      LAYER met3 ;
        RECT 1847.680 741.240 1848.280 741.840 ;
    END
  END Tile_X9Y3_A_IN_top
  PIN Tile_X9Y3_A_OUT_top
    DIRECTION INPUT ;
    USE SIGNAL ;
    ANTENNAGATEAREA 0.252000 ;
    PORT
      LAYER met3 ;
        RECT 1847.680 735.800 1848.280 736.400 ;
    END
  END Tile_X9Y3_A_OUT_top
  PIN Tile_X9Y3_B_EN_top
    DIRECTION OUTPUT ;
    USE SIGNAL ;
    ANTENNADIFFAREA 0.702900 ;
    PORT
      LAYER met3 ;
        RECT 1847.680 763.000 1848.280 763.600 ;
    END
  END Tile_X9Y3_B_EN_top
  PIN Tile_X9Y3_B_IN_top
    DIRECTION OUTPUT ;
    USE SIGNAL ;
    ANTENNADIFFAREA 0.702900 ;
    PORT
      LAYER met3 ;
        RECT 1847.680 757.560 1848.280 758.160 ;
    END
  END Tile_X9Y3_B_IN_top
  PIN Tile_X9Y3_B_OUT_top
    DIRECTION INPUT ;
    USE SIGNAL ;
    ANTENNAGATEAREA 0.252000 ;
    PORT
      LAYER met3 ;
        RECT 1847.680 752.120 1848.280 752.720 ;
    END
  END Tile_X9Y3_B_OUT_top
  PIN Tile_X9Y4_A_EN_top
    DIRECTION OUTPUT ;
    USE SIGNAL ;
    ANTENNADIFFAREA 0.702900 ;
    PORT
      LAYER met3 ;
        RECT 1847.680 523.640 1848.280 524.240 ;
    END
  END Tile_X9Y4_A_EN_top
  PIN Tile_X9Y4_A_IN_top
    DIRECTION OUTPUT ;
    USE SIGNAL ;
    ANTENNADIFFAREA 0.702900 ;
    PORT
      LAYER met3 ;
        RECT 1847.680 518.200 1848.280 518.800 ;
    END
  END Tile_X9Y4_A_IN_top
  PIN Tile_X9Y4_A_OUT_top
    DIRECTION INPUT ;
    USE SIGNAL ;
    ANTENNAGATEAREA 0.252000 ;
    PORT
      LAYER met3 ;
        RECT 1847.680 512.760 1848.280 513.360 ;
    END
  END Tile_X9Y4_A_OUT_top
  PIN Tile_X9Y4_B_EN_top
    DIRECTION OUTPUT ;
    USE SIGNAL ;
    ANTENNADIFFAREA 0.702900 ;
    PORT
      LAYER met3 ;
        RECT 1847.680 539.960 1848.280 540.560 ;
    END
  END Tile_X9Y4_B_EN_top
  PIN Tile_X9Y4_B_IN_top
    DIRECTION OUTPUT ;
    USE SIGNAL ;
    ANTENNADIFFAREA 0.702900 ;
    PORT
      LAYER met3 ;
        RECT 1847.680 534.520 1848.280 535.120 ;
    END
  END Tile_X9Y4_B_IN_top
  PIN Tile_X9Y4_B_OUT_top
    DIRECTION INPUT ;
    USE SIGNAL ;
    ANTENNAGATEAREA 0.252000 ;
    PORT
      LAYER met3 ;
        RECT 1847.680 529.080 1848.280 529.680 ;
    END
  END Tile_X9Y4_B_OUT_top
  PIN Tile_X9Y5_A_EN_top
    DIRECTION OUTPUT ;
    USE SIGNAL ;
    ANTENNADIFFAREA 0.702900 ;
    PORT
      LAYER met3 ;
        RECT 1847.680 300.600 1848.280 301.200 ;
    END
  END Tile_X9Y5_A_EN_top
  PIN Tile_X9Y5_A_IN_top
    DIRECTION OUTPUT ;
    USE SIGNAL ;
    ANTENNADIFFAREA 0.702900 ;
    PORT
      LAYER met3 ;
        RECT 1847.680 295.160 1848.280 295.760 ;
    END
  END Tile_X9Y5_A_IN_top
  PIN Tile_X9Y5_A_OUT_top
    DIRECTION INPUT ;
    USE SIGNAL ;
    ANTENNAGATEAREA 0.252000 ;
    PORT
      LAYER met3 ;
        RECT 1847.680 289.720 1848.280 290.320 ;
    END
  END Tile_X9Y5_A_OUT_top
  PIN Tile_X9Y5_B_EN_top
    DIRECTION OUTPUT ;
    USE SIGNAL ;
    ANTENNADIFFAREA 0.702900 ;
    PORT
      LAYER met3 ;
        RECT 1847.680 316.920 1848.280 317.520 ;
    END
  END Tile_X9Y5_B_EN_top
  PIN Tile_X9Y5_B_IN_top
    DIRECTION OUTPUT ;
    USE SIGNAL ;
    ANTENNADIFFAREA 0.702900 ;
    PORT
      LAYER met3 ;
        RECT 1847.680 311.480 1848.280 312.080 ;
    END
  END Tile_X9Y5_B_IN_top
  PIN Tile_X9Y5_B_OUT_top
    DIRECTION INPUT ;
    USE SIGNAL ;
    ANTENNAGATEAREA 0.252000 ;
    PORT
      LAYER met3 ;
        RECT 1847.680 306.040 1848.280 306.640 ;
    END
  END Tile_X9Y5_B_OUT_top
  PIN Tile_X9Y6_A_EN_top
    DIRECTION OUTPUT ;
    USE SIGNAL ;
    ANTENNADIFFAREA 0.702900 ;
    PORT
      LAYER met3 ;
        RECT 1847.680 77.560 1848.280 78.160 ;
    END
  END Tile_X9Y6_A_EN_top
  PIN Tile_X9Y6_A_IN_top
    DIRECTION OUTPUT ;
    USE SIGNAL ;
    ANTENNADIFFAREA 0.702900 ;
    PORT
      LAYER met3 ;
        RECT 1847.680 72.120 1848.280 72.720 ;
    END
  END Tile_X9Y6_A_IN_top
  PIN Tile_X9Y6_A_OUT_top
    DIRECTION INPUT ;
    USE SIGNAL ;
    ANTENNAGATEAREA 0.252000 ;
    PORT
      LAYER met3 ;
        RECT 1847.680 66.680 1848.280 67.280 ;
    END
  END Tile_X9Y6_A_OUT_top
  PIN Tile_X9Y6_B_EN_top
    DIRECTION OUTPUT ;
    USE SIGNAL ;
    ANTENNADIFFAREA 0.702900 ;
    PORT
      LAYER met3 ;
        RECT 1847.680 93.880 1848.280 94.480 ;
    END
  END Tile_X9Y6_B_EN_top
  PIN Tile_X9Y6_B_IN_top
    DIRECTION OUTPUT ;
    USE SIGNAL ;
    ANTENNADIFFAREA 0.702900 ;
    PORT
      LAYER met3 ;
        RECT 1847.680 88.440 1848.280 89.040 ;
    END
  END Tile_X9Y6_B_IN_top
  PIN Tile_X9Y6_B_OUT_top
    DIRECTION INPUT ;
    USE SIGNAL ;
    ANTENNAGATEAREA 0.252000 ;
    PORT
      LAYER met3 ;
        RECT 1847.680 83.000 1848.280 83.600 ;
    END
  END Tile_X9Y6_B_OUT_top
  PIN VGND
    DIRECTION INOUT ;
    USE GROUND ;
    PORT
      LAYER met4 ;
        RECT 12.260 1395.360 13.860 1452.480 ;
    END
    PORT
      LAYER met4 ;
        RECT 42.260 1395.360 43.860 1452.480 ;
    END
    PORT
      LAYER met4 ;
        RECT 12.260 1172.320 13.860 1395.360 ;
    END
    PORT
      LAYER met4 ;
        RECT 42.260 1172.320 43.860 1395.360 ;
    END
    PORT
      LAYER met4 ;
        RECT 12.260 949.280 13.860 1172.320 ;
    END
    PORT
      LAYER met4 ;
        RECT 42.260 949.280 43.860 1172.320 ;
    END
    PORT
      LAYER met4 ;
        RECT 12.260 726.240 13.860 949.280 ;
    END
    PORT
      LAYER met4 ;
        RECT 42.260 726.240 43.860 949.280 ;
    END
    PORT
      LAYER met4 ;
        RECT 12.260 503.200 13.860 726.240 ;
    END
    PORT
      LAYER met4 ;
        RECT 42.260 503.200 43.860 726.240 ;
    END
    PORT
      LAYER met4 ;
        RECT 12.260 280.160 13.860 503.200 ;
    END
    PORT
      LAYER met4 ;
        RECT 42.260 280.160 43.860 503.200 ;
    END
    PORT
      LAYER met4 ;
        RECT 12.260 57.120 13.860 280.160 ;
    END
    PORT
      LAYER met4 ;
        RECT 42.260 57.120 43.860 280.160 ;
    END
    PORT
      LAYER met4 ;
        RECT 12.260 0.000 13.860 57.120 ;
    END
    PORT
      LAYER met4 ;
        RECT 42.260 0.000 43.860 57.120 ;
    END
    PORT
      LAYER met4 ;
        RECT 68.380 1395.360 69.980 1452.480 ;
    END
    PORT
      LAYER met4 ;
        RECT 98.380 1395.360 99.980 1452.480 ;
    END
    PORT
      LAYER met4 ;
        RECT 128.380 1395.360 129.980 1452.480 ;
    END
    PORT
      LAYER met4 ;
        RECT 158.380 1395.360 159.980 1452.480 ;
    END
    PORT
      LAYER met4 ;
        RECT 188.380 1395.360 189.980 1452.480 ;
    END
    PORT
      LAYER met4 ;
        RECT 218.380 1395.360 219.980 1452.480 ;
    END
    PORT
      LAYER met4 ;
        RECT 248.380 1395.360 249.980 1452.480 ;
    END
    PORT
      LAYER met4 ;
        RECT 68.380 1172.320 69.980 1395.360 ;
    END
    PORT
      LAYER met4 ;
        RECT 98.380 1172.320 99.980 1395.360 ;
    END
    PORT
      LAYER met4 ;
        RECT 128.380 1172.320 129.980 1395.360 ;
    END
    PORT
      LAYER met4 ;
        RECT 158.380 1172.320 159.980 1395.360 ;
    END
    PORT
      LAYER met4 ;
        RECT 188.380 1172.320 189.980 1395.360 ;
    END
    PORT
      LAYER met4 ;
        RECT 218.380 1172.320 219.980 1395.360 ;
    END
    PORT
      LAYER met4 ;
        RECT 248.380 1172.320 249.980 1395.360 ;
    END
    PORT
      LAYER met4 ;
        RECT 68.380 949.280 69.980 1172.320 ;
    END
    PORT
      LAYER met4 ;
        RECT 98.380 949.280 99.980 1172.320 ;
    END
    PORT
      LAYER met4 ;
        RECT 128.380 949.280 129.980 1172.320 ;
    END
    PORT
      LAYER met4 ;
        RECT 158.380 949.280 159.980 1172.320 ;
    END
    PORT
      LAYER met4 ;
        RECT 188.380 949.280 189.980 1172.320 ;
    END
    PORT
      LAYER met4 ;
        RECT 218.380 949.280 219.980 1172.320 ;
    END
    PORT
      LAYER met4 ;
        RECT 248.380 949.280 249.980 1172.320 ;
    END
    PORT
      LAYER met4 ;
        RECT 68.380 726.240 69.980 949.280 ;
    END
    PORT
      LAYER met4 ;
        RECT 98.380 726.240 99.980 949.280 ;
    END
    PORT
      LAYER met4 ;
        RECT 128.380 726.240 129.980 949.280 ;
    END
    PORT
      LAYER met4 ;
        RECT 158.380 726.240 159.980 949.280 ;
    END
    PORT
      LAYER met4 ;
        RECT 188.380 726.240 189.980 949.280 ;
    END
    PORT
      LAYER met4 ;
        RECT 218.380 726.240 219.980 949.280 ;
    END
    PORT
      LAYER met4 ;
        RECT 248.380 726.240 249.980 949.280 ;
    END
    PORT
      LAYER met4 ;
        RECT 68.380 503.200 69.980 726.240 ;
    END
    PORT
      LAYER met4 ;
        RECT 98.380 503.200 99.980 726.240 ;
    END
    PORT
      LAYER met4 ;
        RECT 128.380 503.200 129.980 726.240 ;
    END
    PORT
      LAYER met4 ;
        RECT 158.380 503.200 159.980 726.240 ;
    END
    PORT
      LAYER met4 ;
        RECT 188.380 503.200 189.980 726.240 ;
    END
    PORT
      LAYER met4 ;
        RECT 218.380 503.200 219.980 726.240 ;
    END
    PORT
      LAYER met4 ;
        RECT 248.380 503.200 249.980 726.240 ;
    END
    PORT
      LAYER met4 ;
        RECT 68.380 280.160 69.980 503.200 ;
    END
    PORT
      LAYER met4 ;
        RECT 98.380 280.160 99.980 503.200 ;
    END
    PORT
      LAYER met4 ;
        RECT 128.380 280.160 129.980 503.200 ;
    END
    PORT
      LAYER met4 ;
        RECT 158.380 280.160 159.980 503.200 ;
    END
    PORT
      LAYER met4 ;
        RECT 188.380 280.160 189.980 503.200 ;
    END
    PORT
      LAYER met4 ;
        RECT 218.380 280.160 219.980 503.200 ;
    END
    PORT
      LAYER met4 ;
        RECT 248.380 280.160 249.980 503.200 ;
    END
    PORT
      LAYER met4 ;
        RECT 68.380 57.120 69.980 280.160 ;
    END
    PORT
      LAYER met4 ;
        RECT 98.380 57.120 99.980 280.160 ;
    END
    PORT
      LAYER met4 ;
        RECT 128.380 57.120 129.980 280.160 ;
    END
    PORT
      LAYER met4 ;
        RECT 158.380 57.120 159.980 280.160 ;
    END
    PORT
      LAYER met4 ;
        RECT 188.380 57.120 189.980 280.160 ;
    END
    PORT
      LAYER met4 ;
        RECT 218.380 57.120 219.980 280.160 ;
    END
    PORT
      LAYER met4 ;
        RECT 248.380 57.120 249.980 280.160 ;
    END
    PORT
      LAYER met4 ;
        RECT 68.380 0.000 69.980 57.120 ;
    END
    PORT
      LAYER met4 ;
        RECT 98.380 0.000 99.980 57.120 ;
    END
    PORT
      LAYER met4 ;
        RECT 128.380 0.000 129.980 57.120 ;
    END
    PORT
      LAYER met4 ;
        RECT 158.380 0.000 159.980 57.120 ;
    END
    PORT
      LAYER met4 ;
        RECT 188.380 0.000 189.980 57.120 ;
    END
    PORT
      LAYER met4 ;
        RECT 218.380 0.000 219.980 57.120 ;
    END
    PORT
      LAYER met4 ;
        RECT 248.380 0.000 249.980 57.120 ;
    END
    PORT
      LAYER met4 ;
        RECT 279.060 1395.360 280.660 1452.480 ;
    END
    PORT
      LAYER met4 ;
        RECT 309.060 1395.360 310.660 1452.480 ;
    END
    PORT
      LAYER met4 ;
        RECT 339.060 1395.360 340.660 1452.480 ;
    END
    PORT
      LAYER met4 ;
        RECT 369.060 1395.360 370.660 1452.480 ;
    END
    PORT
      LAYER met4 ;
        RECT 399.060 1395.360 400.660 1452.480 ;
    END
    PORT
      LAYER met4 ;
        RECT 429.060 1395.360 430.660 1452.480 ;
    END
    PORT
      LAYER met4 ;
        RECT 459.060 1395.360 460.660 1452.480 ;
    END
    PORT
      LAYER met4 ;
        RECT 279.060 1172.320 280.660 1395.360 ;
    END
    PORT
      LAYER met4 ;
        RECT 309.060 1172.320 310.660 1395.360 ;
    END
    PORT
      LAYER met4 ;
        RECT 339.060 1172.320 340.660 1395.360 ;
    END
    PORT
      LAYER met4 ;
        RECT 369.060 1172.320 370.660 1395.360 ;
    END
    PORT
      LAYER met4 ;
        RECT 399.060 1172.320 400.660 1395.360 ;
    END
    PORT
      LAYER met4 ;
        RECT 429.060 1172.320 430.660 1395.360 ;
    END
    PORT
      LAYER met4 ;
        RECT 459.060 1172.320 460.660 1395.360 ;
    END
    PORT
      LAYER met4 ;
        RECT 279.060 949.280 280.660 1172.320 ;
    END
    PORT
      LAYER met4 ;
        RECT 309.060 949.280 310.660 1172.320 ;
    END
    PORT
      LAYER met4 ;
        RECT 339.060 949.280 340.660 1172.320 ;
    END
    PORT
      LAYER met4 ;
        RECT 369.060 949.280 370.660 1172.320 ;
    END
    PORT
      LAYER met4 ;
        RECT 399.060 949.280 400.660 1172.320 ;
    END
    PORT
      LAYER met4 ;
        RECT 429.060 949.280 430.660 1172.320 ;
    END
    PORT
      LAYER met4 ;
        RECT 459.060 949.280 460.660 1172.320 ;
    END
    PORT
      LAYER met4 ;
        RECT 279.060 726.240 280.660 949.280 ;
    END
    PORT
      LAYER met4 ;
        RECT 309.060 726.240 310.660 949.280 ;
    END
    PORT
      LAYER met4 ;
        RECT 339.060 726.240 340.660 949.280 ;
    END
    PORT
      LAYER met4 ;
        RECT 369.060 726.240 370.660 949.280 ;
    END
    PORT
      LAYER met4 ;
        RECT 399.060 726.240 400.660 949.280 ;
    END
    PORT
      LAYER met4 ;
        RECT 429.060 726.240 430.660 949.280 ;
    END
    PORT
      LAYER met4 ;
        RECT 459.060 726.240 460.660 949.280 ;
    END
    PORT
      LAYER met4 ;
        RECT 279.060 503.200 280.660 726.240 ;
    END
    PORT
      LAYER met4 ;
        RECT 309.060 503.200 310.660 726.240 ;
    END
    PORT
      LAYER met4 ;
        RECT 339.060 503.200 340.660 726.240 ;
    END
    PORT
      LAYER met4 ;
        RECT 369.060 503.200 370.660 726.240 ;
    END
    PORT
      LAYER met4 ;
        RECT 399.060 503.200 400.660 726.240 ;
    END
    PORT
      LAYER met4 ;
        RECT 429.060 503.200 430.660 726.240 ;
    END
    PORT
      LAYER met4 ;
        RECT 459.060 503.200 460.660 726.240 ;
    END
    PORT
      LAYER met4 ;
        RECT 279.060 280.160 280.660 503.200 ;
    END
    PORT
      LAYER met4 ;
        RECT 309.060 280.160 310.660 503.200 ;
    END
    PORT
      LAYER met4 ;
        RECT 339.060 280.160 340.660 503.200 ;
    END
    PORT
      LAYER met4 ;
        RECT 369.060 280.160 370.660 503.200 ;
    END
    PORT
      LAYER met4 ;
        RECT 399.060 280.160 400.660 503.200 ;
    END
    PORT
      LAYER met4 ;
        RECT 429.060 280.160 430.660 503.200 ;
    END
    PORT
      LAYER met4 ;
        RECT 459.060 280.160 460.660 503.200 ;
    END
    PORT
      LAYER met4 ;
        RECT 279.060 57.120 280.660 280.160 ;
    END
    PORT
      LAYER met4 ;
        RECT 309.060 57.120 310.660 280.160 ;
    END
    PORT
      LAYER met4 ;
        RECT 339.060 57.120 340.660 280.160 ;
    END
    PORT
      LAYER met4 ;
        RECT 369.060 57.120 370.660 280.160 ;
    END
    PORT
      LAYER met4 ;
        RECT 399.060 57.120 400.660 280.160 ;
    END
    PORT
      LAYER met4 ;
        RECT 429.060 57.120 430.660 280.160 ;
    END
    PORT
      LAYER met4 ;
        RECT 459.060 57.120 460.660 280.160 ;
    END
    PORT
      LAYER met4 ;
        RECT 279.060 0.000 280.660 57.120 ;
    END
    PORT
      LAYER met4 ;
        RECT 309.060 0.000 310.660 57.120 ;
    END
    PORT
      LAYER met4 ;
        RECT 339.060 0.000 340.660 57.120 ;
    END
    PORT
      LAYER met4 ;
        RECT 369.060 0.000 370.660 57.120 ;
    END
    PORT
      LAYER met4 ;
        RECT 399.060 0.000 400.660 57.120 ;
    END
    PORT
      LAYER met4 ;
        RECT 429.060 0.000 430.660 57.120 ;
    END
    PORT
      LAYER met4 ;
        RECT 459.060 0.000 460.660 57.120 ;
    END
    PORT
      LAYER met4 ;
        RECT 489.740 1395.360 491.340 1452.480 ;
    END
    PORT
      LAYER met4 ;
        RECT 519.740 1395.360 521.340 1452.480 ;
    END
    PORT
      LAYER met4 ;
        RECT 549.740 1395.360 551.340 1452.480 ;
    END
    PORT
      LAYER met4 ;
        RECT 579.740 1395.360 581.340 1452.480 ;
    END
    PORT
      LAYER met4 ;
        RECT 609.740 1395.360 611.340 1452.480 ;
    END
    PORT
      LAYER met4 ;
        RECT 639.740 1395.360 641.340 1452.480 ;
    END
    PORT
      LAYER met4 ;
        RECT 669.740 1395.360 671.340 1452.480 ;
    END
    PORT
      LAYER met4 ;
        RECT 699.740 1395.360 701.340 1452.480 ;
    END
    PORT
      LAYER met4 ;
        RECT 489.740 1172.320 491.340 1395.360 ;
    END
    PORT
      LAYER met4 ;
        RECT 519.740 1172.320 521.340 1395.360 ;
    END
    PORT
      LAYER met4 ;
        RECT 549.740 1172.320 551.340 1395.360 ;
    END
    PORT
      LAYER met4 ;
        RECT 579.740 1172.320 581.340 1395.360 ;
    END
    PORT
      LAYER met4 ;
        RECT 609.740 1172.320 611.340 1395.360 ;
    END
    PORT
      LAYER met4 ;
        RECT 639.740 1172.320 641.340 1395.360 ;
    END
    PORT
      LAYER met4 ;
        RECT 669.740 1172.320 671.340 1395.360 ;
    END
    PORT
      LAYER met4 ;
        RECT 699.740 1172.320 701.340 1395.360 ;
    END
    PORT
      LAYER met4 ;
        RECT 489.740 949.280 491.340 1172.320 ;
    END
    PORT
      LAYER met4 ;
        RECT 519.740 949.280 521.340 1172.320 ;
    END
    PORT
      LAYER met4 ;
        RECT 549.740 949.280 551.340 1172.320 ;
    END
    PORT
      LAYER met4 ;
        RECT 579.740 949.280 581.340 1172.320 ;
    END
    PORT
      LAYER met4 ;
        RECT 609.740 949.280 611.340 1172.320 ;
    END
    PORT
      LAYER met4 ;
        RECT 639.740 949.280 641.340 1172.320 ;
    END
    PORT
      LAYER met4 ;
        RECT 669.740 949.280 671.340 1172.320 ;
    END
    PORT
      LAYER met4 ;
        RECT 699.740 949.280 701.340 1172.320 ;
    END
    PORT
      LAYER met4 ;
        RECT 489.740 726.240 491.340 949.280 ;
    END
    PORT
      LAYER met4 ;
        RECT 519.740 726.240 521.340 949.280 ;
    END
    PORT
      LAYER met4 ;
        RECT 549.740 726.240 551.340 949.280 ;
    END
    PORT
      LAYER met4 ;
        RECT 579.740 726.240 581.340 949.280 ;
    END
    PORT
      LAYER met4 ;
        RECT 609.740 726.240 611.340 949.280 ;
    END
    PORT
      LAYER met4 ;
        RECT 639.740 726.240 641.340 949.280 ;
    END
    PORT
      LAYER met4 ;
        RECT 669.740 726.240 671.340 949.280 ;
    END
    PORT
      LAYER met4 ;
        RECT 699.740 726.240 701.340 949.280 ;
    END
    PORT
      LAYER met4 ;
        RECT 489.740 503.200 491.340 726.240 ;
    END
    PORT
      LAYER met4 ;
        RECT 519.740 503.200 521.340 726.240 ;
    END
    PORT
      LAYER met4 ;
        RECT 549.740 503.200 551.340 726.240 ;
    END
    PORT
      LAYER met4 ;
        RECT 579.740 503.200 581.340 726.240 ;
    END
    PORT
      LAYER met4 ;
        RECT 609.740 503.200 611.340 726.240 ;
    END
    PORT
      LAYER met4 ;
        RECT 639.740 503.200 641.340 726.240 ;
    END
    PORT
      LAYER met4 ;
        RECT 669.740 503.200 671.340 726.240 ;
    END
    PORT
      LAYER met4 ;
        RECT 699.740 503.200 701.340 726.240 ;
    END
    PORT
      LAYER met4 ;
        RECT 489.740 280.160 491.340 503.200 ;
    END
    PORT
      LAYER met4 ;
        RECT 519.740 280.160 521.340 503.200 ;
    END
    PORT
      LAYER met4 ;
        RECT 549.740 280.160 551.340 503.200 ;
    END
    PORT
      LAYER met4 ;
        RECT 579.740 280.160 581.340 503.200 ;
    END
    PORT
      LAYER met4 ;
        RECT 609.740 280.160 611.340 503.200 ;
    END
    PORT
      LAYER met4 ;
        RECT 639.740 280.160 641.340 503.200 ;
    END
    PORT
      LAYER met4 ;
        RECT 669.740 280.160 671.340 503.200 ;
    END
    PORT
      LAYER met4 ;
        RECT 699.740 280.160 701.340 503.200 ;
    END
    PORT
      LAYER met4 ;
        RECT 489.740 57.120 491.340 280.160 ;
    END
    PORT
      LAYER met4 ;
        RECT 519.740 57.120 521.340 280.160 ;
    END
    PORT
      LAYER met4 ;
        RECT 549.740 57.120 551.340 280.160 ;
    END
    PORT
      LAYER met4 ;
        RECT 579.740 57.120 581.340 280.160 ;
    END
    PORT
      LAYER met4 ;
        RECT 609.740 57.120 611.340 280.160 ;
    END
    PORT
      LAYER met4 ;
        RECT 639.740 57.120 641.340 280.160 ;
    END
    PORT
      LAYER met4 ;
        RECT 669.740 57.120 671.340 280.160 ;
    END
    PORT
      LAYER met4 ;
        RECT 699.740 57.120 701.340 280.160 ;
    END
    PORT
      LAYER met4 ;
        RECT 489.740 0.000 491.340 57.120 ;
    END
    PORT
      LAYER met4 ;
        RECT 519.740 0.000 521.340 57.120 ;
    END
    PORT
      LAYER met4 ;
        RECT 549.740 0.000 551.340 57.120 ;
    END
    PORT
      LAYER met4 ;
        RECT 579.740 0.000 581.340 57.120 ;
    END
    PORT
      LAYER met4 ;
        RECT 609.740 0.000 611.340 57.120 ;
    END
    PORT
      LAYER met4 ;
        RECT 639.740 0.000 641.340 57.120 ;
    END
    PORT
      LAYER met4 ;
        RECT 669.740 0.000 671.340 57.120 ;
    END
    PORT
      LAYER met4 ;
        RECT 699.740 0.000 701.340 57.120 ;
    END
    PORT
      LAYER met4 ;
        RECT 741.820 1395.360 743.420 1452.480 ;
    END
    PORT
      LAYER met4 ;
        RECT 771.820 1395.360 773.420 1452.480 ;
    END
    PORT
      LAYER met4 ;
        RECT 801.820 1395.360 803.420 1452.480 ;
    END
    PORT
      LAYER met4 ;
        RECT 831.820 1395.360 833.420 1452.480 ;
    END
    PORT
      LAYER met4 ;
        RECT 861.820 1395.360 863.420 1452.480 ;
    END
    PORT
      LAYER met4 ;
        RECT 891.820 1395.360 893.420 1452.480 ;
    END
    PORT
      LAYER met4 ;
        RECT 921.820 1395.360 923.420 1452.480 ;
    END
    PORT
      LAYER met4 ;
        RECT 741.820 1172.320 743.420 1395.360 ;
    END
    PORT
      LAYER met4 ;
        RECT 771.820 1172.320 773.420 1395.360 ;
    END
    PORT
      LAYER met4 ;
        RECT 801.820 1172.320 803.420 1395.360 ;
    END
    PORT
      LAYER met4 ;
        RECT 831.820 1172.320 833.420 1395.360 ;
    END
    PORT
      LAYER met4 ;
        RECT 861.820 1172.320 863.420 1395.360 ;
    END
    PORT
      LAYER met4 ;
        RECT 891.820 1172.320 893.420 1395.360 ;
    END
    PORT
      LAYER met4 ;
        RECT 921.820 1172.320 923.420 1395.360 ;
    END
    PORT
      LAYER met4 ;
        RECT 741.820 949.280 743.420 1172.320 ;
    END
    PORT
      LAYER met4 ;
        RECT 771.820 949.280 773.420 1172.320 ;
    END
    PORT
      LAYER met4 ;
        RECT 801.820 949.280 803.420 1172.320 ;
    END
    PORT
      LAYER met4 ;
        RECT 831.820 949.280 833.420 1172.320 ;
    END
    PORT
      LAYER met4 ;
        RECT 861.820 949.280 863.420 1172.320 ;
    END
    PORT
      LAYER met4 ;
        RECT 891.820 949.280 893.420 1172.320 ;
    END
    PORT
      LAYER met4 ;
        RECT 921.820 949.280 923.420 1172.320 ;
    END
    PORT
      LAYER met4 ;
        RECT 741.820 726.240 743.420 949.280 ;
    END
    PORT
      LAYER met4 ;
        RECT 771.820 726.240 773.420 949.280 ;
    END
    PORT
      LAYER met4 ;
        RECT 801.820 726.240 803.420 949.280 ;
    END
    PORT
      LAYER met4 ;
        RECT 831.820 726.240 833.420 949.280 ;
    END
    PORT
      LAYER met4 ;
        RECT 861.820 726.240 863.420 949.280 ;
    END
    PORT
      LAYER met4 ;
        RECT 891.820 726.240 893.420 949.280 ;
    END
    PORT
      LAYER met4 ;
        RECT 921.820 726.240 923.420 949.280 ;
    END
    PORT
      LAYER met4 ;
        RECT 741.820 503.200 743.420 726.240 ;
    END
    PORT
      LAYER met4 ;
        RECT 771.820 503.200 773.420 726.240 ;
    END
    PORT
      LAYER met4 ;
        RECT 801.820 503.200 803.420 726.240 ;
    END
    PORT
      LAYER met4 ;
        RECT 831.820 503.200 833.420 726.240 ;
    END
    PORT
      LAYER met4 ;
        RECT 861.820 503.200 863.420 726.240 ;
    END
    PORT
      LAYER met4 ;
        RECT 891.820 503.200 893.420 726.240 ;
    END
    PORT
      LAYER met4 ;
        RECT 921.820 503.200 923.420 726.240 ;
    END
    PORT
      LAYER met4 ;
        RECT 741.820 280.160 743.420 503.200 ;
    END
    PORT
      LAYER met4 ;
        RECT 771.820 280.160 773.420 503.200 ;
    END
    PORT
      LAYER met4 ;
        RECT 801.820 280.160 803.420 503.200 ;
    END
    PORT
      LAYER met4 ;
        RECT 831.820 280.160 833.420 503.200 ;
    END
    PORT
      LAYER met4 ;
        RECT 861.820 280.160 863.420 503.200 ;
    END
    PORT
      LAYER met4 ;
        RECT 891.820 280.160 893.420 503.200 ;
    END
    PORT
      LAYER met4 ;
        RECT 921.820 280.160 923.420 503.200 ;
    END
    PORT
      LAYER met4 ;
        RECT 741.820 57.120 743.420 280.160 ;
    END
    PORT
      LAYER met4 ;
        RECT 771.820 57.120 773.420 280.160 ;
    END
    PORT
      LAYER met4 ;
        RECT 801.820 57.120 803.420 280.160 ;
    END
    PORT
      LAYER met4 ;
        RECT 831.820 57.120 833.420 280.160 ;
    END
    PORT
      LAYER met4 ;
        RECT 861.820 57.120 863.420 280.160 ;
    END
    PORT
      LAYER met4 ;
        RECT 891.820 57.120 893.420 280.160 ;
    END
    PORT
      LAYER met4 ;
        RECT 921.820 57.120 923.420 280.160 ;
    END
    PORT
      LAYER met4 ;
        RECT 741.820 0.000 743.420 57.120 ;
    END
    PORT
      LAYER met4 ;
        RECT 771.820 0.000 773.420 57.120 ;
    END
    PORT
      LAYER met4 ;
        RECT 801.820 0.000 803.420 57.120 ;
    END
    PORT
      LAYER met4 ;
        RECT 831.820 0.000 833.420 57.120 ;
    END
    PORT
      LAYER met4 ;
        RECT 861.820 0.000 863.420 57.120 ;
    END
    PORT
      LAYER met4 ;
        RECT 891.820 0.000 893.420 57.120 ;
    END
    PORT
      LAYER met4 ;
        RECT 921.820 0.000 923.420 57.120 ;
    END
    PORT
      LAYER met4 ;
        RECT 952.500 1395.360 954.100 1452.480 ;
    END
    PORT
      LAYER met4 ;
        RECT 982.500 1395.360 984.100 1452.480 ;
    END
    PORT
      LAYER met4 ;
        RECT 1012.500 1395.360 1014.100 1452.480 ;
    END
    PORT
      LAYER met4 ;
        RECT 1042.500 1395.360 1044.100 1452.480 ;
    END
    PORT
      LAYER met4 ;
        RECT 1072.500 1395.360 1074.100 1452.480 ;
    END
    PORT
      LAYER met4 ;
        RECT 1102.500 1395.360 1104.100 1452.480 ;
    END
    PORT
      LAYER met4 ;
        RECT 1132.500 1395.360 1134.100 1452.480 ;
    END
    PORT
      LAYER met4 ;
        RECT 952.500 1172.320 954.100 1395.360 ;
    END
    PORT
      LAYER met4 ;
        RECT 982.500 1172.320 984.100 1395.360 ;
    END
    PORT
      LAYER met4 ;
        RECT 1012.500 1172.320 1014.100 1395.360 ;
    END
    PORT
      LAYER met4 ;
        RECT 1042.500 1172.320 1044.100 1395.360 ;
    END
    PORT
      LAYER met4 ;
        RECT 1072.500 1172.320 1074.100 1395.360 ;
    END
    PORT
      LAYER met4 ;
        RECT 1102.500 1172.320 1104.100 1395.360 ;
    END
    PORT
      LAYER met4 ;
        RECT 1132.500 1172.320 1134.100 1395.360 ;
    END
    PORT
      LAYER met4 ;
        RECT 952.500 949.280 954.100 1172.320 ;
    END
    PORT
      LAYER met4 ;
        RECT 982.500 949.280 984.100 1172.320 ;
    END
    PORT
      LAYER met4 ;
        RECT 1012.500 949.280 1014.100 1172.320 ;
    END
    PORT
      LAYER met4 ;
        RECT 1042.500 949.280 1044.100 1172.320 ;
    END
    PORT
      LAYER met4 ;
        RECT 1072.500 949.280 1074.100 1172.320 ;
    END
    PORT
      LAYER met4 ;
        RECT 1102.500 949.280 1104.100 1172.320 ;
    END
    PORT
      LAYER met4 ;
        RECT 1132.500 949.280 1134.100 1172.320 ;
    END
    PORT
      LAYER met4 ;
        RECT 952.500 726.240 954.100 949.280 ;
    END
    PORT
      LAYER met4 ;
        RECT 982.500 726.240 984.100 949.280 ;
    END
    PORT
      LAYER met4 ;
        RECT 1012.500 726.240 1014.100 949.280 ;
    END
    PORT
      LAYER met4 ;
        RECT 1042.500 726.240 1044.100 949.280 ;
    END
    PORT
      LAYER met4 ;
        RECT 1072.500 726.240 1074.100 949.280 ;
    END
    PORT
      LAYER met4 ;
        RECT 1102.500 726.240 1104.100 949.280 ;
    END
    PORT
      LAYER met4 ;
        RECT 1132.500 726.240 1134.100 949.280 ;
    END
    PORT
      LAYER met4 ;
        RECT 952.500 503.200 954.100 726.240 ;
    END
    PORT
      LAYER met4 ;
        RECT 982.500 503.200 984.100 726.240 ;
    END
    PORT
      LAYER met4 ;
        RECT 1012.500 503.200 1014.100 726.240 ;
    END
    PORT
      LAYER met4 ;
        RECT 1042.500 503.200 1044.100 726.240 ;
    END
    PORT
      LAYER met4 ;
        RECT 1072.500 503.200 1074.100 726.240 ;
    END
    PORT
      LAYER met4 ;
        RECT 1102.500 503.200 1104.100 726.240 ;
    END
    PORT
      LAYER met4 ;
        RECT 1132.500 503.200 1134.100 726.240 ;
    END
    PORT
      LAYER met4 ;
        RECT 952.500 280.160 954.100 503.200 ;
    END
    PORT
      LAYER met4 ;
        RECT 982.500 280.160 984.100 503.200 ;
    END
    PORT
      LAYER met4 ;
        RECT 1012.500 280.160 1014.100 503.200 ;
    END
    PORT
      LAYER met4 ;
        RECT 1042.500 280.160 1044.100 503.200 ;
    END
    PORT
      LAYER met4 ;
        RECT 1072.500 280.160 1074.100 503.200 ;
    END
    PORT
      LAYER met4 ;
        RECT 1102.500 280.160 1104.100 503.200 ;
    END
    PORT
      LAYER met4 ;
        RECT 1132.500 280.160 1134.100 503.200 ;
    END
    PORT
      LAYER met4 ;
        RECT 952.500 57.120 954.100 280.160 ;
    END
    PORT
      LAYER met4 ;
        RECT 982.500 57.120 984.100 280.160 ;
    END
    PORT
      LAYER met4 ;
        RECT 1012.500 57.120 1014.100 280.160 ;
    END
    PORT
      LAYER met4 ;
        RECT 1042.500 57.120 1044.100 280.160 ;
    END
    PORT
      LAYER met4 ;
        RECT 1072.500 57.120 1074.100 280.160 ;
    END
    PORT
      LAYER met4 ;
        RECT 1102.500 57.120 1104.100 280.160 ;
    END
    PORT
      LAYER met4 ;
        RECT 1132.500 57.120 1134.100 280.160 ;
    END
    PORT
      LAYER met4 ;
        RECT 952.500 0.000 954.100 57.120 ;
    END
    PORT
      LAYER met4 ;
        RECT 982.500 0.000 984.100 57.120 ;
    END
    PORT
      LAYER met4 ;
        RECT 1012.500 0.000 1014.100 57.120 ;
    END
    PORT
      LAYER met4 ;
        RECT 1042.500 0.000 1044.100 57.120 ;
    END
    PORT
      LAYER met4 ;
        RECT 1072.500 0.000 1074.100 57.120 ;
    END
    PORT
      LAYER met4 ;
        RECT 1102.500 0.000 1104.100 57.120 ;
    END
    PORT
      LAYER met4 ;
        RECT 1132.500 0.000 1134.100 57.120 ;
    END
    PORT
      LAYER met4 ;
        RECT 1163.180 1395.360 1164.780 1452.480 ;
    END
    PORT
      LAYER met4 ;
        RECT 1193.180 1395.360 1194.780 1452.480 ;
    END
    PORT
      LAYER met4 ;
        RECT 1223.180 1395.360 1224.780 1452.480 ;
    END
    PORT
      LAYER met4 ;
        RECT 1253.180 1395.360 1254.780 1452.480 ;
    END
    PORT
      LAYER met4 ;
        RECT 1283.180 1395.360 1284.780 1452.480 ;
    END
    PORT
      LAYER met4 ;
        RECT 1313.180 1395.360 1314.780 1452.480 ;
    END
    PORT
      LAYER met4 ;
        RECT 1343.180 1395.360 1344.780 1452.480 ;
    END
    PORT
      LAYER met4 ;
        RECT 1163.180 949.280 1164.780 1395.360 ;
    END
    PORT
      LAYER met4 ;
        RECT 1193.180 949.280 1194.780 1395.360 ;
    END
    PORT
      LAYER met4 ;
        RECT 1223.180 949.280 1224.780 1395.360 ;
    END
    PORT
      LAYER met4 ;
        RECT 1253.180 949.280 1254.780 1395.360 ;
    END
    PORT
      LAYER met4 ;
        RECT 1283.180 949.280 1284.780 1395.360 ;
    END
    PORT
      LAYER met4 ;
        RECT 1313.180 949.280 1314.780 1395.360 ;
    END
    PORT
      LAYER met4 ;
        RECT 1343.180 949.280 1344.780 1395.360 ;
    END
    PORT
      LAYER met4 ;
        RECT 1163.180 503.200 1164.780 949.280 ;
    END
    PORT
      LAYER met4 ;
        RECT 1193.180 503.200 1194.780 949.280 ;
    END
    PORT
      LAYER met4 ;
        RECT 1223.180 503.200 1224.780 949.280 ;
    END
    PORT
      LAYER met4 ;
        RECT 1253.180 503.200 1254.780 949.280 ;
    END
    PORT
      LAYER met4 ;
        RECT 1283.180 503.200 1284.780 949.280 ;
    END
    PORT
      LAYER met4 ;
        RECT 1313.180 503.200 1314.780 949.280 ;
    END
    PORT
      LAYER met4 ;
        RECT 1343.180 503.200 1344.780 949.280 ;
    END
    PORT
      LAYER met4 ;
        RECT 1163.180 57.120 1164.780 503.200 ;
    END
    PORT
      LAYER met4 ;
        RECT 1193.180 57.120 1194.780 503.200 ;
    END
    PORT
      LAYER met4 ;
        RECT 1223.180 57.120 1224.780 503.200 ;
    END
    PORT
      LAYER met4 ;
        RECT 1253.180 57.120 1254.780 503.200 ;
    END
    PORT
      LAYER met4 ;
        RECT 1283.180 57.120 1284.780 503.200 ;
    END
    PORT
      LAYER met4 ;
        RECT 1313.180 57.120 1314.780 503.200 ;
    END
    PORT
      LAYER met4 ;
        RECT 1343.180 57.120 1344.780 503.200 ;
    END
    PORT
      LAYER met4 ;
        RECT 1163.180 0.000 1164.780 57.120 ;
    END
    PORT
      LAYER met4 ;
        RECT 1193.180 0.000 1194.780 57.120 ;
    END
    PORT
      LAYER met4 ;
        RECT 1223.180 0.000 1224.780 57.120 ;
    END
    PORT
      LAYER met4 ;
        RECT 1253.180 0.000 1254.780 57.120 ;
    END
    PORT
      LAYER met4 ;
        RECT 1283.180 0.000 1284.780 57.120 ;
    END
    PORT
      LAYER met4 ;
        RECT 1313.180 0.000 1314.780 57.120 ;
    END
    PORT
      LAYER met4 ;
        RECT 1343.180 0.000 1344.780 57.120 ;
    END
    PORT
      LAYER met4 ;
        RECT 1383.060 1395.360 1384.660 1452.480 ;
    END
    PORT
      LAYER met4 ;
        RECT 1413.060 1395.360 1414.660 1452.480 ;
    END
    PORT
      LAYER met4 ;
        RECT 1443.060 1395.360 1444.660 1452.480 ;
    END
    PORT
      LAYER met4 ;
        RECT 1473.060 1395.360 1474.660 1452.480 ;
    END
    PORT
      LAYER met4 ;
        RECT 1503.060 1395.360 1504.660 1452.480 ;
    END
    PORT
      LAYER met4 ;
        RECT 1533.060 1395.360 1534.660 1452.480 ;
    END
    PORT
      LAYER met4 ;
        RECT 1563.060 1395.360 1564.660 1452.480 ;
    END
    PORT
      LAYER met4 ;
        RECT 1383.060 1172.320 1384.660 1395.360 ;
    END
    PORT
      LAYER met4 ;
        RECT 1413.060 1172.320 1414.660 1395.360 ;
    END
    PORT
      LAYER met4 ;
        RECT 1443.060 1172.320 1444.660 1395.360 ;
    END
    PORT
      LAYER met4 ;
        RECT 1473.060 1172.320 1474.660 1395.360 ;
    END
    PORT
      LAYER met4 ;
        RECT 1503.060 1172.320 1504.660 1395.360 ;
    END
    PORT
      LAYER met4 ;
        RECT 1533.060 1172.320 1534.660 1395.360 ;
    END
    PORT
      LAYER met4 ;
        RECT 1563.060 1172.320 1564.660 1395.360 ;
    END
    PORT
      LAYER met4 ;
        RECT 1383.060 949.280 1384.660 1172.320 ;
    END
    PORT
      LAYER met4 ;
        RECT 1413.060 949.280 1414.660 1172.320 ;
    END
    PORT
      LAYER met4 ;
        RECT 1443.060 949.280 1444.660 1172.320 ;
    END
    PORT
      LAYER met4 ;
        RECT 1473.060 949.280 1474.660 1172.320 ;
    END
    PORT
      LAYER met4 ;
        RECT 1503.060 949.280 1504.660 1172.320 ;
    END
    PORT
      LAYER met4 ;
        RECT 1533.060 949.280 1534.660 1172.320 ;
    END
    PORT
      LAYER met4 ;
        RECT 1563.060 949.280 1564.660 1172.320 ;
    END
    PORT
      LAYER met4 ;
        RECT 1383.060 726.240 1384.660 949.280 ;
    END
    PORT
      LAYER met4 ;
        RECT 1413.060 726.240 1414.660 949.280 ;
    END
    PORT
      LAYER met4 ;
        RECT 1443.060 726.240 1444.660 949.280 ;
    END
    PORT
      LAYER met4 ;
        RECT 1473.060 726.240 1474.660 949.280 ;
    END
    PORT
      LAYER met4 ;
        RECT 1503.060 726.240 1504.660 949.280 ;
    END
    PORT
      LAYER met4 ;
        RECT 1533.060 726.240 1534.660 949.280 ;
    END
    PORT
      LAYER met4 ;
        RECT 1563.060 726.240 1564.660 949.280 ;
    END
    PORT
      LAYER met4 ;
        RECT 1383.060 503.200 1384.660 726.240 ;
    END
    PORT
      LAYER met4 ;
        RECT 1413.060 503.200 1414.660 726.240 ;
    END
    PORT
      LAYER met4 ;
        RECT 1443.060 503.200 1444.660 726.240 ;
    END
    PORT
      LAYER met4 ;
        RECT 1473.060 503.200 1474.660 726.240 ;
    END
    PORT
      LAYER met4 ;
        RECT 1503.060 503.200 1504.660 726.240 ;
    END
    PORT
      LAYER met4 ;
        RECT 1533.060 503.200 1534.660 726.240 ;
    END
    PORT
      LAYER met4 ;
        RECT 1563.060 503.200 1564.660 726.240 ;
    END
    PORT
      LAYER met4 ;
        RECT 1383.060 280.160 1384.660 503.200 ;
    END
    PORT
      LAYER met4 ;
        RECT 1413.060 280.160 1414.660 503.200 ;
    END
    PORT
      LAYER met4 ;
        RECT 1443.060 280.160 1444.660 503.200 ;
    END
    PORT
      LAYER met4 ;
        RECT 1473.060 280.160 1474.660 503.200 ;
    END
    PORT
      LAYER met4 ;
        RECT 1503.060 280.160 1504.660 503.200 ;
    END
    PORT
      LAYER met4 ;
        RECT 1533.060 280.160 1534.660 503.200 ;
    END
    PORT
      LAYER met4 ;
        RECT 1563.060 280.160 1564.660 503.200 ;
    END
    PORT
      LAYER met4 ;
        RECT 1383.060 57.120 1384.660 280.160 ;
    END
    PORT
      LAYER met4 ;
        RECT 1413.060 57.120 1414.660 280.160 ;
    END
    PORT
      LAYER met4 ;
        RECT 1443.060 57.120 1444.660 280.160 ;
    END
    PORT
      LAYER met4 ;
        RECT 1473.060 57.120 1474.660 280.160 ;
    END
    PORT
      LAYER met4 ;
        RECT 1503.060 57.120 1504.660 280.160 ;
    END
    PORT
      LAYER met4 ;
        RECT 1533.060 57.120 1534.660 280.160 ;
    END
    PORT
      LAYER met4 ;
        RECT 1563.060 57.120 1564.660 280.160 ;
    END
    PORT
      LAYER met4 ;
        RECT 1383.060 0.000 1384.660 57.120 ;
    END
    PORT
      LAYER met4 ;
        RECT 1413.060 0.000 1414.660 57.120 ;
    END
    PORT
      LAYER met4 ;
        RECT 1443.060 0.000 1444.660 57.120 ;
    END
    PORT
      LAYER met4 ;
        RECT 1473.060 0.000 1474.660 57.120 ;
    END
    PORT
      LAYER met4 ;
        RECT 1503.060 0.000 1504.660 57.120 ;
    END
    PORT
      LAYER met4 ;
        RECT 1533.060 0.000 1534.660 57.120 ;
    END
    PORT
      LAYER met4 ;
        RECT 1563.060 0.000 1564.660 57.120 ;
    END
    PORT
      LAYER met4 ;
        RECT 1593.740 1395.360 1595.340 1452.480 ;
    END
    PORT
      LAYER met4 ;
        RECT 1623.740 1395.360 1625.340 1452.480 ;
    END
    PORT
      LAYER met4 ;
        RECT 1653.740 1395.360 1655.340 1452.480 ;
    END
    PORT
      LAYER met4 ;
        RECT 1683.740 1395.360 1685.340 1452.480 ;
    END
    PORT
      LAYER met4 ;
        RECT 1713.740 1395.360 1715.340 1452.480 ;
    END
    PORT
      LAYER met4 ;
        RECT 1743.740 1395.360 1745.340 1452.480 ;
    END
    PORT
      LAYER met4 ;
        RECT 1773.740 1395.360 1775.340 1452.480 ;
    END
    PORT
      LAYER met4 ;
        RECT 1593.740 1172.320 1595.340 1395.360 ;
    END
    PORT
      LAYER met4 ;
        RECT 1623.740 1172.320 1625.340 1395.360 ;
    END
    PORT
      LAYER met4 ;
        RECT 1653.740 1172.320 1655.340 1395.360 ;
    END
    PORT
      LAYER met4 ;
        RECT 1683.740 1172.320 1685.340 1395.360 ;
    END
    PORT
      LAYER met4 ;
        RECT 1713.740 1172.320 1715.340 1395.360 ;
    END
    PORT
      LAYER met4 ;
        RECT 1743.740 1172.320 1745.340 1395.360 ;
    END
    PORT
      LAYER met4 ;
        RECT 1773.740 1172.320 1775.340 1395.360 ;
    END
    PORT
      LAYER met4 ;
        RECT 1593.740 949.280 1595.340 1172.320 ;
    END
    PORT
      LAYER met4 ;
        RECT 1623.740 949.280 1625.340 1172.320 ;
    END
    PORT
      LAYER met4 ;
        RECT 1653.740 949.280 1655.340 1172.320 ;
    END
    PORT
      LAYER met4 ;
        RECT 1683.740 949.280 1685.340 1172.320 ;
    END
    PORT
      LAYER met4 ;
        RECT 1713.740 949.280 1715.340 1172.320 ;
    END
    PORT
      LAYER met4 ;
        RECT 1743.740 949.280 1745.340 1172.320 ;
    END
    PORT
      LAYER met4 ;
        RECT 1773.740 949.280 1775.340 1172.320 ;
    END
    PORT
      LAYER met4 ;
        RECT 1593.740 726.240 1595.340 949.280 ;
    END
    PORT
      LAYER met4 ;
        RECT 1623.740 726.240 1625.340 949.280 ;
    END
    PORT
      LAYER met4 ;
        RECT 1653.740 726.240 1655.340 949.280 ;
    END
    PORT
      LAYER met4 ;
        RECT 1683.740 726.240 1685.340 949.280 ;
    END
    PORT
      LAYER met4 ;
        RECT 1713.740 726.240 1715.340 949.280 ;
    END
    PORT
      LAYER met4 ;
        RECT 1743.740 726.240 1745.340 949.280 ;
    END
    PORT
      LAYER met4 ;
        RECT 1773.740 726.240 1775.340 949.280 ;
    END
    PORT
      LAYER met4 ;
        RECT 1593.740 503.200 1595.340 726.240 ;
    END
    PORT
      LAYER met4 ;
        RECT 1623.740 503.200 1625.340 726.240 ;
    END
    PORT
      LAYER met4 ;
        RECT 1653.740 503.200 1655.340 726.240 ;
    END
    PORT
      LAYER met4 ;
        RECT 1683.740 503.200 1685.340 726.240 ;
    END
    PORT
      LAYER met4 ;
        RECT 1713.740 503.200 1715.340 726.240 ;
    END
    PORT
      LAYER met4 ;
        RECT 1743.740 503.200 1745.340 726.240 ;
    END
    PORT
      LAYER met4 ;
        RECT 1773.740 503.200 1775.340 726.240 ;
    END
    PORT
      LAYER met4 ;
        RECT 1593.740 280.160 1595.340 503.200 ;
    END
    PORT
      LAYER met4 ;
        RECT 1623.740 280.160 1625.340 503.200 ;
    END
    PORT
      LAYER met4 ;
        RECT 1653.740 280.160 1655.340 503.200 ;
    END
    PORT
      LAYER met4 ;
        RECT 1683.740 280.160 1685.340 503.200 ;
    END
    PORT
      LAYER met4 ;
        RECT 1713.740 280.160 1715.340 503.200 ;
    END
    PORT
      LAYER met4 ;
        RECT 1743.740 280.160 1745.340 503.200 ;
    END
    PORT
      LAYER met4 ;
        RECT 1773.740 280.160 1775.340 503.200 ;
    END
    PORT
      LAYER met4 ;
        RECT 1593.740 57.120 1595.340 280.160 ;
    END
    PORT
      LAYER met4 ;
        RECT 1623.740 57.120 1625.340 280.160 ;
    END
    PORT
      LAYER met4 ;
        RECT 1653.740 57.120 1655.340 280.160 ;
    END
    PORT
      LAYER met4 ;
        RECT 1683.740 57.120 1685.340 280.160 ;
    END
    PORT
      LAYER met4 ;
        RECT 1713.740 57.120 1715.340 280.160 ;
    END
    PORT
      LAYER met4 ;
        RECT 1743.740 57.120 1745.340 280.160 ;
    END
    PORT
      LAYER met4 ;
        RECT 1773.740 57.120 1775.340 280.160 ;
    END
    PORT
      LAYER met4 ;
        RECT 1593.740 0.000 1595.340 57.120 ;
    END
    PORT
      LAYER met4 ;
        RECT 1623.740 0.000 1625.340 57.120 ;
    END
    PORT
      LAYER met4 ;
        RECT 1653.740 0.000 1655.340 57.120 ;
    END
    PORT
      LAYER met4 ;
        RECT 1683.740 0.000 1685.340 57.120 ;
    END
    PORT
      LAYER met4 ;
        RECT 1713.740 0.000 1715.340 57.120 ;
    END
    PORT
      LAYER met4 ;
        RECT 1743.740 0.000 1745.340 57.120 ;
    END
    PORT
      LAYER met4 ;
        RECT 1773.740 0.000 1775.340 57.120 ;
    END
    PORT
      LAYER met4 ;
        RECT 1804.420 1395.360 1806.020 1452.480 ;
    END
    PORT
      LAYER met4 ;
        RECT 1834.420 1395.360 1836.020 1452.480 ;
    END
    PORT
      LAYER met4 ;
        RECT 1804.420 1172.320 1806.020 1395.360 ;
    END
    PORT
      LAYER met4 ;
        RECT 1834.420 1172.320 1836.020 1395.360 ;
    END
    PORT
      LAYER met4 ;
        RECT 1804.420 949.280 1806.020 1172.320 ;
    END
    PORT
      LAYER met4 ;
        RECT 1834.420 949.280 1836.020 1172.320 ;
    END
    PORT
      LAYER met4 ;
        RECT 1804.420 726.240 1806.020 949.280 ;
    END
    PORT
      LAYER met4 ;
        RECT 1834.420 726.240 1836.020 949.280 ;
    END
    PORT
      LAYER met4 ;
        RECT 1804.420 503.200 1806.020 726.240 ;
    END
    PORT
      LAYER met4 ;
        RECT 1834.420 503.200 1836.020 726.240 ;
    END
    PORT
      LAYER met4 ;
        RECT 1804.420 280.160 1806.020 503.200 ;
    END
    PORT
      LAYER met4 ;
        RECT 1834.420 280.160 1836.020 503.200 ;
    END
    PORT
      LAYER met4 ;
        RECT 1804.420 57.120 1806.020 280.160 ;
    END
    PORT
      LAYER met4 ;
        RECT 1834.420 57.120 1836.020 280.160 ;
    END
    PORT
      LAYER met4 ;
        RECT 1804.420 0.000 1806.020 57.120 ;
    END
    PORT
      LAYER met4 ;
        RECT 1834.420 0.000 1836.020 57.120 ;
    END
  END VGND
  PIN VPWR
    DIRECTION INOUT ;
    USE POWER ;
    PORT
      LAYER met4 ;
        RECT 6.960 1395.360 8.560 1452.480 ;
    END
    PORT
      LAYER met4 ;
        RECT 36.960 1395.360 38.560 1452.480 ;
    END
    PORT
      LAYER met4 ;
        RECT 6.960 1172.320 8.560 1395.360 ;
    END
    PORT
      LAYER met4 ;
        RECT 36.960 1172.320 38.560 1395.360 ;
    END
    PORT
      LAYER met4 ;
        RECT 6.960 949.280 8.560 1172.320 ;
    END
    PORT
      LAYER met4 ;
        RECT 36.960 949.280 38.560 1172.320 ;
    END
    PORT
      LAYER met4 ;
        RECT 6.960 726.240 8.560 949.280 ;
    END
    PORT
      LAYER met4 ;
        RECT 36.960 726.240 38.560 949.280 ;
    END
    PORT
      LAYER met4 ;
        RECT 6.960 503.200 8.560 726.240 ;
    END
    PORT
      LAYER met4 ;
        RECT 36.960 503.200 38.560 726.240 ;
    END
    PORT
      LAYER met4 ;
        RECT 6.960 280.160 8.560 503.200 ;
    END
    PORT
      LAYER met4 ;
        RECT 36.960 280.160 38.560 503.200 ;
    END
    PORT
      LAYER met4 ;
        RECT 6.960 57.120 8.560 280.160 ;
    END
    PORT
      LAYER met4 ;
        RECT 36.960 57.120 38.560 280.160 ;
    END
    PORT
      LAYER met4 ;
        RECT 6.960 0.000 8.560 57.120 ;
    END
    PORT
      LAYER met4 ;
        RECT 36.960 0.000 38.560 57.120 ;
    END
    PORT
      LAYER met4 ;
        RECT 63.080 1395.360 64.680 1452.480 ;
    END
    PORT
      LAYER met4 ;
        RECT 93.080 1395.360 94.680 1452.480 ;
    END
    PORT
      LAYER met4 ;
        RECT 123.080 1395.360 124.680 1452.480 ;
    END
    PORT
      LAYER met4 ;
        RECT 153.080 1395.360 154.680 1452.480 ;
    END
    PORT
      LAYER met4 ;
        RECT 183.080 1395.360 184.680 1452.480 ;
    END
    PORT
      LAYER met4 ;
        RECT 213.080 1395.360 214.680 1452.480 ;
    END
    PORT
      LAYER met4 ;
        RECT 243.080 1395.360 244.680 1452.480 ;
    END
    PORT
      LAYER met4 ;
        RECT 63.080 1172.320 64.680 1395.360 ;
    END
    PORT
      LAYER met4 ;
        RECT 93.080 1172.320 94.680 1395.360 ;
    END
    PORT
      LAYER met4 ;
        RECT 123.080 1172.320 124.680 1395.360 ;
    END
    PORT
      LAYER met4 ;
        RECT 153.080 1172.320 154.680 1395.360 ;
    END
    PORT
      LAYER met4 ;
        RECT 183.080 1172.320 184.680 1395.360 ;
    END
    PORT
      LAYER met4 ;
        RECT 213.080 1172.320 214.680 1395.360 ;
    END
    PORT
      LAYER met4 ;
        RECT 243.080 1172.320 244.680 1395.360 ;
    END
    PORT
      LAYER met4 ;
        RECT 63.080 949.280 64.680 1172.320 ;
    END
    PORT
      LAYER met4 ;
        RECT 93.080 949.280 94.680 1172.320 ;
    END
    PORT
      LAYER met4 ;
        RECT 123.080 949.280 124.680 1172.320 ;
    END
    PORT
      LAYER met4 ;
        RECT 153.080 949.280 154.680 1172.320 ;
    END
    PORT
      LAYER met4 ;
        RECT 183.080 949.280 184.680 1172.320 ;
    END
    PORT
      LAYER met4 ;
        RECT 213.080 949.280 214.680 1172.320 ;
    END
    PORT
      LAYER met4 ;
        RECT 243.080 949.280 244.680 1172.320 ;
    END
    PORT
      LAYER met4 ;
        RECT 63.080 726.240 64.680 949.280 ;
    END
    PORT
      LAYER met4 ;
        RECT 93.080 726.240 94.680 949.280 ;
    END
    PORT
      LAYER met4 ;
        RECT 123.080 726.240 124.680 949.280 ;
    END
    PORT
      LAYER met4 ;
        RECT 153.080 726.240 154.680 949.280 ;
    END
    PORT
      LAYER met4 ;
        RECT 183.080 726.240 184.680 949.280 ;
    END
    PORT
      LAYER met4 ;
        RECT 213.080 726.240 214.680 949.280 ;
    END
    PORT
      LAYER met4 ;
        RECT 243.080 726.240 244.680 949.280 ;
    END
    PORT
      LAYER met4 ;
        RECT 63.080 503.200 64.680 726.240 ;
    END
    PORT
      LAYER met4 ;
        RECT 93.080 503.200 94.680 726.240 ;
    END
    PORT
      LAYER met4 ;
        RECT 123.080 503.200 124.680 726.240 ;
    END
    PORT
      LAYER met4 ;
        RECT 153.080 503.200 154.680 726.240 ;
    END
    PORT
      LAYER met4 ;
        RECT 183.080 503.200 184.680 726.240 ;
    END
    PORT
      LAYER met4 ;
        RECT 213.080 503.200 214.680 726.240 ;
    END
    PORT
      LAYER met4 ;
        RECT 243.080 503.200 244.680 726.240 ;
    END
    PORT
      LAYER met4 ;
        RECT 63.080 280.160 64.680 503.200 ;
    END
    PORT
      LAYER met4 ;
        RECT 93.080 280.160 94.680 503.200 ;
    END
    PORT
      LAYER met4 ;
        RECT 123.080 280.160 124.680 503.200 ;
    END
    PORT
      LAYER met4 ;
        RECT 153.080 280.160 154.680 503.200 ;
    END
    PORT
      LAYER met4 ;
        RECT 183.080 280.160 184.680 503.200 ;
    END
    PORT
      LAYER met4 ;
        RECT 213.080 280.160 214.680 503.200 ;
    END
    PORT
      LAYER met4 ;
        RECT 243.080 280.160 244.680 503.200 ;
    END
    PORT
      LAYER met4 ;
        RECT 63.080 57.120 64.680 280.160 ;
    END
    PORT
      LAYER met4 ;
        RECT 93.080 57.120 94.680 280.160 ;
    END
    PORT
      LAYER met4 ;
        RECT 123.080 57.120 124.680 280.160 ;
    END
    PORT
      LAYER met4 ;
        RECT 153.080 57.120 154.680 280.160 ;
    END
    PORT
      LAYER met4 ;
        RECT 183.080 57.120 184.680 280.160 ;
    END
    PORT
      LAYER met4 ;
        RECT 213.080 57.120 214.680 280.160 ;
    END
    PORT
      LAYER met4 ;
        RECT 243.080 57.120 244.680 280.160 ;
    END
    PORT
      LAYER met4 ;
        RECT 63.080 0.000 64.680 57.120 ;
    END
    PORT
      LAYER met4 ;
        RECT 93.080 0.000 94.680 57.120 ;
    END
    PORT
      LAYER met4 ;
        RECT 123.080 0.000 124.680 57.120 ;
    END
    PORT
      LAYER met4 ;
        RECT 153.080 0.000 154.680 57.120 ;
    END
    PORT
      LAYER met4 ;
        RECT 183.080 0.000 184.680 57.120 ;
    END
    PORT
      LAYER met4 ;
        RECT 213.080 0.000 214.680 57.120 ;
    END
    PORT
      LAYER met4 ;
        RECT 243.080 0.000 244.680 57.120 ;
    END
    PORT
      LAYER met4 ;
        RECT 273.760 1395.360 275.360 1452.480 ;
    END
    PORT
      LAYER met4 ;
        RECT 303.760 1395.360 305.360 1452.480 ;
    END
    PORT
      LAYER met4 ;
        RECT 333.760 1395.360 335.360 1452.480 ;
    END
    PORT
      LAYER met4 ;
        RECT 363.760 1395.360 365.360 1452.480 ;
    END
    PORT
      LAYER met4 ;
        RECT 393.760 1395.360 395.360 1452.480 ;
    END
    PORT
      LAYER met4 ;
        RECT 423.760 1395.360 425.360 1452.480 ;
    END
    PORT
      LAYER met4 ;
        RECT 453.760 1395.360 455.360 1452.480 ;
    END
    PORT
      LAYER met4 ;
        RECT 273.760 1172.320 275.360 1395.360 ;
    END
    PORT
      LAYER met4 ;
        RECT 303.760 1172.320 305.360 1395.360 ;
    END
    PORT
      LAYER met4 ;
        RECT 333.760 1172.320 335.360 1395.360 ;
    END
    PORT
      LAYER met4 ;
        RECT 363.760 1172.320 365.360 1395.360 ;
    END
    PORT
      LAYER met4 ;
        RECT 393.760 1172.320 395.360 1395.360 ;
    END
    PORT
      LAYER met4 ;
        RECT 423.760 1172.320 425.360 1395.360 ;
    END
    PORT
      LAYER met4 ;
        RECT 453.760 1172.320 455.360 1395.360 ;
    END
    PORT
      LAYER met4 ;
        RECT 273.760 949.280 275.360 1172.320 ;
    END
    PORT
      LAYER met4 ;
        RECT 303.760 949.280 305.360 1172.320 ;
    END
    PORT
      LAYER met4 ;
        RECT 333.760 949.280 335.360 1172.320 ;
    END
    PORT
      LAYER met4 ;
        RECT 363.760 949.280 365.360 1172.320 ;
    END
    PORT
      LAYER met4 ;
        RECT 393.760 949.280 395.360 1172.320 ;
    END
    PORT
      LAYER met4 ;
        RECT 423.760 949.280 425.360 1172.320 ;
    END
    PORT
      LAYER met4 ;
        RECT 453.760 949.280 455.360 1172.320 ;
    END
    PORT
      LAYER met4 ;
        RECT 273.760 726.240 275.360 949.280 ;
    END
    PORT
      LAYER met4 ;
        RECT 303.760 726.240 305.360 949.280 ;
    END
    PORT
      LAYER met4 ;
        RECT 333.760 726.240 335.360 949.280 ;
    END
    PORT
      LAYER met4 ;
        RECT 363.760 726.240 365.360 949.280 ;
    END
    PORT
      LAYER met4 ;
        RECT 393.760 726.240 395.360 949.280 ;
    END
    PORT
      LAYER met4 ;
        RECT 423.760 726.240 425.360 949.280 ;
    END
    PORT
      LAYER met4 ;
        RECT 453.760 726.240 455.360 949.280 ;
    END
    PORT
      LAYER met4 ;
        RECT 273.760 503.200 275.360 726.240 ;
    END
    PORT
      LAYER met4 ;
        RECT 303.760 503.200 305.360 726.240 ;
    END
    PORT
      LAYER met4 ;
        RECT 333.760 503.200 335.360 726.240 ;
    END
    PORT
      LAYER met4 ;
        RECT 363.760 503.200 365.360 726.240 ;
    END
    PORT
      LAYER met4 ;
        RECT 393.760 503.200 395.360 726.240 ;
    END
    PORT
      LAYER met4 ;
        RECT 423.760 503.200 425.360 726.240 ;
    END
    PORT
      LAYER met4 ;
        RECT 453.760 503.200 455.360 726.240 ;
    END
    PORT
      LAYER met4 ;
        RECT 273.760 280.160 275.360 503.200 ;
    END
    PORT
      LAYER met4 ;
        RECT 303.760 280.160 305.360 503.200 ;
    END
    PORT
      LAYER met4 ;
        RECT 333.760 280.160 335.360 503.200 ;
    END
    PORT
      LAYER met4 ;
        RECT 363.760 280.160 365.360 503.200 ;
    END
    PORT
      LAYER met4 ;
        RECT 393.760 280.160 395.360 503.200 ;
    END
    PORT
      LAYER met4 ;
        RECT 423.760 280.160 425.360 503.200 ;
    END
    PORT
      LAYER met4 ;
        RECT 453.760 280.160 455.360 503.200 ;
    END
    PORT
      LAYER met4 ;
        RECT 273.760 57.120 275.360 280.160 ;
    END
    PORT
      LAYER met4 ;
        RECT 303.760 57.120 305.360 280.160 ;
    END
    PORT
      LAYER met4 ;
        RECT 333.760 57.120 335.360 280.160 ;
    END
    PORT
      LAYER met4 ;
        RECT 363.760 57.120 365.360 280.160 ;
    END
    PORT
      LAYER met4 ;
        RECT 393.760 57.120 395.360 280.160 ;
    END
    PORT
      LAYER met4 ;
        RECT 423.760 57.120 425.360 280.160 ;
    END
    PORT
      LAYER met4 ;
        RECT 453.760 57.120 455.360 280.160 ;
    END
    PORT
      LAYER met4 ;
        RECT 273.760 0.000 275.360 57.120 ;
    END
    PORT
      LAYER met4 ;
        RECT 303.760 0.000 305.360 57.120 ;
    END
    PORT
      LAYER met4 ;
        RECT 333.760 0.000 335.360 57.120 ;
    END
    PORT
      LAYER met4 ;
        RECT 363.760 0.000 365.360 57.120 ;
    END
    PORT
      LAYER met4 ;
        RECT 393.760 0.000 395.360 57.120 ;
    END
    PORT
      LAYER met4 ;
        RECT 423.760 0.000 425.360 57.120 ;
    END
    PORT
      LAYER met4 ;
        RECT 453.760 0.000 455.360 57.120 ;
    END
    PORT
      LAYER met4 ;
        RECT 484.440 1395.360 486.040 1452.480 ;
    END
    PORT
      LAYER met4 ;
        RECT 514.440 1395.360 516.040 1452.480 ;
    END
    PORT
      LAYER met4 ;
        RECT 544.440 1395.360 546.040 1452.480 ;
    END
    PORT
      LAYER met4 ;
        RECT 574.440 1395.360 576.040 1452.480 ;
    END
    PORT
      LAYER met4 ;
        RECT 604.440 1395.360 606.040 1452.480 ;
    END
    PORT
      LAYER met4 ;
        RECT 634.440 1395.360 636.040 1452.480 ;
    END
    PORT
      LAYER met4 ;
        RECT 664.440 1395.360 666.040 1452.480 ;
    END
    PORT
      LAYER met4 ;
        RECT 694.440 1395.360 696.040 1452.480 ;
    END
    PORT
      LAYER met4 ;
        RECT 724.440 1395.360 726.040 1452.480 ;
    END
    PORT
      LAYER met4 ;
        RECT 484.440 1172.320 486.040 1395.360 ;
    END
    PORT
      LAYER met4 ;
        RECT 514.440 1172.320 516.040 1395.360 ;
    END
    PORT
      LAYER met4 ;
        RECT 544.440 1172.320 546.040 1395.360 ;
    END
    PORT
      LAYER met4 ;
        RECT 574.440 1172.320 576.040 1395.360 ;
    END
    PORT
      LAYER met4 ;
        RECT 604.440 1172.320 606.040 1395.360 ;
    END
    PORT
      LAYER met4 ;
        RECT 634.440 1172.320 636.040 1395.360 ;
    END
    PORT
      LAYER met4 ;
        RECT 664.440 1172.320 666.040 1395.360 ;
    END
    PORT
      LAYER met4 ;
        RECT 694.440 1172.320 696.040 1395.360 ;
    END
    PORT
      LAYER met4 ;
        RECT 724.440 1172.320 726.040 1395.360 ;
    END
    PORT
      LAYER met4 ;
        RECT 484.440 949.280 486.040 1172.320 ;
    END
    PORT
      LAYER met4 ;
        RECT 514.440 949.280 516.040 1172.320 ;
    END
    PORT
      LAYER met4 ;
        RECT 544.440 949.280 546.040 1172.320 ;
    END
    PORT
      LAYER met4 ;
        RECT 574.440 949.280 576.040 1172.320 ;
    END
    PORT
      LAYER met4 ;
        RECT 604.440 949.280 606.040 1172.320 ;
    END
    PORT
      LAYER met4 ;
        RECT 634.440 949.280 636.040 1172.320 ;
    END
    PORT
      LAYER met4 ;
        RECT 664.440 949.280 666.040 1172.320 ;
    END
    PORT
      LAYER met4 ;
        RECT 694.440 949.280 696.040 1172.320 ;
    END
    PORT
      LAYER met4 ;
        RECT 724.440 949.280 726.040 1172.320 ;
    END
    PORT
      LAYER met4 ;
        RECT 484.440 726.240 486.040 949.280 ;
    END
    PORT
      LAYER met4 ;
        RECT 514.440 726.240 516.040 949.280 ;
    END
    PORT
      LAYER met4 ;
        RECT 544.440 726.240 546.040 949.280 ;
    END
    PORT
      LAYER met4 ;
        RECT 574.440 726.240 576.040 949.280 ;
    END
    PORT
      LAYER met4 ;
        RECT 604.440 726.240 606.040 949.280 ;
    END
    PORT
      LAYER met4 ;
        RECT 634.440 726.240 636.040 949.280 ;
    END
    PORT
      LAYER met4 ;
        RECT 664.440 726.240 666.040 949.280 ;
    END
    PORT
      LAYER met4 ;
        RECT 694.440 726.240 696.040 949.280 ;
    END
    PORT
      LAYER met4 ;
        RECT 724.440 726.240 726.040 949.280 ;
    END
    PORT
      LAYER met4 ;
        RECT 484.440 503.200 486.040 726.240 ;
    END
    PORT
      LAYER met4 ;
        RECT 514.440 503.200 516.040 726.240 ;
    END
    PORT
      LAYER met4 ;
        RECT 544.440 503.200 546.040 726.240 ;
    END
    PORT
      LAYER met4 ;
        RECT 574.440 503.200 576.040 726.240 ;
    END
    PORT
      LAYER met4 ;
        RECT 604.440 503.200 606.040 726.240 ;
    END
    PORT
      LAYER met4 ;
        RECT 634.440 503.200 636.040 726.240 ;
    END
    PORT
      LAYER met4 ;
        RECT 664.440 503.200 666.040 726.240 ;
    END
    PORT
      LAYER met4 ;
        RECT 694.440 503.200 696.040 726.240 ;
    END
    PORT
      LAYER met4 ;
        RECT 724.440 503.200 726.040 726.240 ;
    END
    PORT
      LAYER met4 ;
        RECT 484.440 280.160 486.040 503.200 ;
    END
    PORT
      LAYER met4 ;
        RECT 514.440 280.160 516.040 503.200 ;
    END
    PORT
      LAYER met4 ;
        RECT 544.440 280.160 546.040 503.200 ;
    END
    PORT
      LAYER met4 ;
        RECT 574.440 280.160 576.040 503.200 ;
    END
    PORT
      LAYER met4 ;
        RECT 604.440 280.160 606.040 503.200 ;
    END
    PORT
      LAYER met4 ;
        RECT 634.440 280.160 636.040 503.200 ;
    END
    PORT
      LAYER met4 ;
        RECT 664.440 280.160 666.040 503.200 ;
    END
    PORT
      LAYER met4 ;
        RECT 694.440 280.160 696.040 503.200 ;
    END
    PORT
      LAYER met4 ;
        RECT 724.440 280.160 726.040 503.200 ;
    END
    PORT
      LAYER met4 ;
        RECT 484.440 57.120 486.040 280.160 ;
    END
    PORT
      LAYER met4 ;
        RECT 514.440 57.120 516.040 280.160 ;
    END
    PORT
      LAYER met4 ;
        RECT 544.440 57.120 546.040 280.160 ;
    END
    PORT
      LAYER met4 ;
        RECT 574.440 57.120 576.040 280.160 ;
    END
    PORT
      LAYER met4 ;
        RECT 604.440 57.120 606.040 280.160 ;
    END
    PORT
      LAYER met4 ;
        RECT 634.440 57.120 636.040 280.160 ;
    END
    PORT
      LAYER met4 ;
        RECT 664.440 57.120 666.040 280.160 ;
    END
    PORT
      LAYER met4 ;
        RECT 694.440 57.120 696.040 280.160 ;
    END
    PORT
      LAYER met4 ;
        RECT 724.440 57.120 726.040 280.160 ;
    END
    PORT
      LAYER met4 ;
        RECT 484.440 0.000 486.040 57.120 ;
    END
    PORT
      LAYER met4 ;
        RECT 514.440 0.000 516.040 57.120 ;
    END
    PORT
      LAYER met4 ;
        RECT 544.440 0.000 546.040 57.120 ;
    END
    PORT
      LAYER met4 ;
        RECT 574.440 0.000 576.040 57.120 ;
    END
    PORT
      LAYER met4 ;
        RECT 604.440 0.000 606.040 57.120 ;
    END
    PORT
      LAYER met4 ;
        RECT 634.440 0.000 636.040 57.120 ;
    END
    PORT
      LAYER met4 ;
        RECT 664.440 0.000 666.040 57.120 ;
    END
    PORT
      LAYER met4 ;
        RECT 694.440 0.000 696.040 57.120 ;
    END
    PORT
      LAYER met4 ;
        RECT 724.440 0.000 726.040 57.120 ;
    END
    PORT
      LAYER met4 ;
        RECT 736.520 1395.360 738.120 1452.480 ;
    END
    PORT
      LAYER met4 ;
        RECT 766.520 1395.360 768.120 1452.480 ;
    END
    PORT
      LAYER met4 ;
        RECT 796.520 1395.360 798.120 1452.480 ;
    END
    PORT
      LAYER met4 ;
        RECT 826.520 1395.360 828.120 1452.480 ;
    END
    PORT
      LAYER met4 ;
        RECT 856.520 1395.360 858.120 1452.480 ;
    END
    PORT
      LAYER met4 ;
        RECT 886.520 1395.360 888.120 1452.480 ;
    END
    PORT
      LAYER met4 ;
        RECT 916.520 1395.360 918.120 1452.480 ;
    END
    PORT
      LAYER met4 ;
        RECT 736.520 1172.320 738.120 1395.360 ;
    END
    PORT
      LAYER met4 ;
        RECT 766.520 1172.320 768.120 1395.360 ;
    END
    PORT
      LAYER met4 ;
        RECT 796.520 1172.320 798.120 1395.360 ;
    END
    PORT
      LAYER met4 ;
        RECT 826.520 1172.320 828.120 1395.360 ;
    END
    PORT
      LAYER met4 ;
        RECT 856.520 1172.320 858.120 1395.360 ;
    END
    PORT
      LAYER met4 ;
        RECT 886.520 1172.320 888.120 1395.360 ;
    END
    PORT
      LAYER met4 ;
        RECT 916.520 1172.320 918.120 1395.360 ;
    END
    PORT
      LAYER met4 ;
        RECT 736.520 949.280 738.120 1172.320 ;
    END
    PORT
      LAYER met4 ;
        RECT 766.520 949.280 768.120 1172.320 ;
    END
    PORT
      LAYER met4 ;
        RECT 796.520 949.280 798.120 1172.320 ;
    END
    PORT
      LAYER met4 ;
        RECT 826.520 949.280 828.120 1172.320 ;
    END
    PORT
      LAYER met4 ;
        RECT 856.520 949.280 858.120 1172.320 ;
    END
    PORT
      LAYER met4 ;
        RECT 886.520 949.280 888.120 1172.320 ;
    END
    PORT
      LAYER met4 ;
        RECT 916.520 949.280 918.120 1172.320 ;
    END
    PORT
      LAYER met4 ;
        RECT 736.520 726.240 738.120 949.280 ;
    END
    PORT
      LAYER met4 ;
        RECT 766.520 726.240 768.120 949.280 ;
    END
    PORT
      LAYER met4 ;
        RECT 796.520 726.240 798.120 949.280 ;
    END
    PORT
      LAYER met4 ;
        RECT 826.520 726.240 828.120 949.280 ;
    END
    PORT
      LAYER met4 ;
        RECT 856.520 726.240 858.120 949.280 ;
    END
    PORT
      LAYER met4 ;
        RECT 886.520 726.240 888.120 949.280 ;
    END
    PORT
      LAYER met4 ;
        RECT 916.520 726.240 918.120 949.280 ;
    END
    PORT
      LAYER met4 ;
        RECT 736.520 503.200 738.120 726.240 ;
    END
    PORT
      LAYER met4 ;
        RECT 766.520 503.200 768.120 726.240 ;
    END
    PORT
      LAYER met4 ;
        RECT 796.520 503.200 798.120 726.240 ;
    END
    PORT
      LAYER met4 ;
        RECT 826.520 503.200 828.120 726.240 ;
    END
    PORT
      LAYER met4 ;
        RECT 856.520 503.200 858.120 726.240 ;
    END
    PORT
      LAYER met4 ;
        RECT 886.520 503.200 888.120 726.240 ;
    END
    PORT
      LAYER met4 ;
        RECT 916.520 503.200 918.120 726.240 ;
    END
    PORT
      LAYER met4 ;
        RECT 736.520 280.160 738.120 503.200 ;
    END
    PORT
      LAYER met4 ;
        RECT 766.520 280.160 768.120 503.200 ;
    END
    PORT
      LAYER met4 ;
        RECT 796.520 280.160 798.120 503.200 ;
    END
    PORT
      LAYER met4 ;
        RECT 826.520 280.160 828.120 503.200 ;
    END
    PORT
      LAYER met4 ;
        RECT 856.520 280.160 858.120 503.200 ;
    END
    PORT
      LAYER met4 ;
        RECT 886.520 280.160 888.120 503.200 ;
    END
    PORT
      LAYER met4 ;
        RECT 916.520 280.160 918.120 503.200 ;
    END
    PORT
      LAYER met4 ;
        RECT 736.520 57.120 738.120 280.160 ;
    END
    PORT
      LAYER met4 ;
        RECT 766.520 57.120 768.120 280.160 ;
    END
    PORT
      LAYER met4 ;
        RECT 796.520 57.120 798.120 280.160 ;
    END
    PORT
      LAYER met4 ;
        RECT 826.520 57.120 828.120 280.160 ;
    END
    PORT
      LAYER met4 ;
        RECT 856.520 57.120 858.120 280.160 ;
    END
    PORT
      LAYER met4 ;
        RECT 886.520 57.120 888.120 280.160 ;
    END
    PORT
      LAYER met4 ;
        RECT 916.520 57.120 918.120 280.160 ;
    END
    PORT
      LAYER met4 ;
        RECT 736.520 0.000 738.120 57.120 ;
    END
    PORT
      LAYER met4 ;
        RECT 766.520 0.000 768.120 57.120 ;
    END
    PORT
      LAYER met4 ;
        RECT 796.520 0.000 798.120 57.120 ;
    END
    PORT
      LAYER met4 ;
        RECT 826.520 0.000 828.120 57.120 ;
    END
    PORT
      LAYER met4 ;
        RECT 856.520 0.000 858.120 57.120 ;
    END
    PORT
      LAYER met4 ;
        RECT 886.520 0.000 888.120 57.120 ;
    END
    PORT
      LAYER met4 ;
        RECT 916.520 0.000 918.120 57.120 ;
    END
    PORT
      LAYER met4 ;
        RECT 947.200 1395.360 948.800 1452.480 ;
    END
    PORT
      LAYER met4 ;
        RECT 977.200 1395.360 978.800 1452.480 ;
    END
    PORT
      LAYER met4 ;
        RECT 1007.200 1395.360 1008.800 1452.480 ;
    END
    PORT
      LAYER met4 ;
        RECT 1037.200 1395.360 1038.800 1452.480 ;
    END
    PORT
      LAYER met4 ;
        RECT 1067.200 1395.360 1068.800 1452.480 ;
    END
    PORT
      LAYER met4 ;
        RECT 1097.200 1395.360 1098.800 1452.480 ;
    END
    PORT
      LAYER met4 ;
        RECT 1127.200 1395.360 1128.800 1452.480 ;
    END
    PORT
      LAYER met4 ;
        RECT 947.200 1172.320 948.800 1395.360 ;
    END
    PORT
      LAYER met4 ;
        RECT 977.200 1172.320 978.800 1395.360 ;
    END
    PORT
      LAYER met4 ;
        RECT 1007.200 1172.320 1008.800 1395.360 ;
    END
    PORT
      LAYER met4 ;
        RECT 1037.200 1172.320 1038.800 1395.360 ;
    END
    PORT
      LAYER met4 ;
        RECT 1067.200 1172.320 1068.800 1395.360 ;
    END
    PORT
      LAYER met4 ;
        RECT 1097.200 1172.320 1098.800 1395.360 ;
    END
    PORT
      LAYER met4 ;
        RECT 1127.200 1172.320 1128.800 1395.360 ;
    END
    PORT
      LAYER met4 ;
        RECT 947.200 949.280 948.800 1172.320 ;
    END
    PORT
      LAYER met4 ;
        RECT 977.200 949.280 978.800 1172.320 ;
    END
    PORT
      LAYER met4 ;
        RECT 1007.200 949.280 1008.800 1172.320 ;
    END
    PORT
      LAYER met4 ;
        RECT 1037.200 949.280 1038.800 1172.320 ;
    END
    PORT
      LAYER met4 ;
        RECT 1067.200 949.280 1068.800 1172.320 ;
    END
    PORT
      LAYER met4 ;
        RECT 1097.200 949.280 1098.800 1172.320 ;
    END
    PORT
      LAYER met4 ;
        RECT 1127.200 949.280 1128.800 1172.320 ;
    END
    PORT
      LAYER met4 ;
        RECT 947.200 726.240 948.800 949.280 ;
    END
    PORT
      LAYER met4 ;
        RECT 977.200 726.240 978.800 949.280 ;
    END
    PORT
      LAYER met4 ;
        RECT 1007.200 726.240 1008.800 949.280 ;
    END
    PORT
      LAYER met4 ;
        RECT 1037.200 726.240 1038.800 949.280 ;
    END
    PORT
      LAYER met4 ;
        RECT 1067.200 726.240 1068.800 949.280 ;
    END
    PORT
      LAYER met4 ;
        RECT 1097.200 726.240 1098.800 949.280 ;
    END
    PORT
      LAYER met4 ;
        RECT 1127.200 726.240 1128.800 949.280 ;
    END
    PORT
      LAYER met4 ;
        RECT 947.200 503.200 948.800 726.240 ;
    END
    PORT
      LAYER met4 ;
        RECT 977.200 503.200 978.800 726.240 ;
    END
    PORT
      LAYER met4 ;
        RECT 1007.200 503.200 1008.800 726.240 ;
    END
    PORT
      LAYER met4 ;
        RECT 1037.200 503.200 1038.800 726.240 ;
    END
    PORT
      LAYER met4 ;
        RECT 1067.200 503.200 1068.800 726.240 ;
    END
    PORT
      LAYER met4 ;
        RECT 1097.200 503.200 1098.800 726.240 ;
    END
    PORT
      LAYER met4 ;
        RECT 1127.200 503.200 1128.800 726.240 ;
    END
    PORT
      LAYER met4 ;
        RECT 947.200 280.160 948.800 503.200 ;
    END
    PORT
      LAYER met4 ;
        RECT 977.200 280.160 978.800 503.200 ;
    END
    PORT
      LAYER met4 ;
        RECT 1007.200 280.160 1008.800 503.200 ;
    END
    PORT
      LAYER met4 ;
        RECT 1037.200 280.160 1038.800 503.200 ;
    END
    PORT
      LAYER met4 ;
        RECT 1067.200 280.160 1068.800 503.200 ;
    END
    PORT
      LAYER met4 ;
        RECT 1097.200 280.160 1098.800 503.200 ;
    END
    PORT
      LAYER met4 ;
        RECT 1127.200 280.160 1128.800 503.200 ;
    END
    PORT
      LAYER met4 ;
        RECT 947.200 57.120 948.800 280.160 ;
    END
    PORT
      LAYER met4 ;
        RECT 977.200 57.120 978.800 280.160 ;
    END
    PORT
      LAYER met4 ;
        RECT 1007.200 57.120 1008.800 280.160 ;
    END
    PORT
      LAYER met4 ;
        RECT 1037.200 57.120 1038.800 280.160 ;
    END
    PORT
      LAYER met4 ;
        RECT 1067.200 57.120 1068.800 280.160 ;
    END
    PORT
      LAYER met4 ;
        RECT 1097.200 57.120 1098.800 280.160 ;
    END
    PORT
      LAYER met4 ;
        RECT 1127.200 57.120 1128.800 280.160 ;
    END
    PORT
      LAYER met4 ;
        RECT 947.200 0.000 948.800 57.120 ;
    END
    PORT
      LAYER met4 ;
        RECT 977.200 0.000 978.800 57.120 ;
    END
    PORT
      LAYER met4 ;
        RECT 1007.200 0.000 1008.800 57.120 ;
    END
    PORT
      LAYER met4 ;
        RECT 1037.200 0.000 1038.800 57.120 ;
    END
    PORT
      LAYER met4 ;
        RECT 1067.200 0.000 1068.800 57.120 ;
    END
    PORT
      LAYER met4 ;
        RECT 1097.200 0.000 1098.800 57.120 ;
    END
    PORT
      LAYER met4 ;
        RECT 1127.200 0.000 1128.800 57.120 ;
    END
    PORT
      LAYER met4 ;
        RECT 1157.880 1395.360 1159.480 1452.480 ;
    END
    PORT
      LAYER met4 ;
        RECT 1187.880 1395.360 1189.480 1452.480 ;
    END
    PORT
      LAYER met4 ;
        RECT 1217.880 1395.360 1219.480 1452.480 ;
    END
    PORT
      LAYER met4 ;
        RECT 1247.880 1395.360 1249.480 1452.480 ;
    END
    PORT
      LAYER met4 ;
        RECT 1277.880 1395.360 1279.480 1452.480 ;
    END
    PORT
      LAYER met4 ;
        RECT 1307.880 1395.360 1309.480 1452.480 ;
    END
    PORT
      LAYER met4 ;
        RECT 1337.880 1395.360 1339.480 1452.480 ;
    END
    PORT
      LAYER met4 ;
        RECT 1157.880 949.280 1159.480 1395.360 ;
    END
    PORT
      LAYER met4 ;
        RECT 1187.880 949.280 1189.480 1395.360 ;
    END
    PORT
      LAYER met4 ;
        RECT 1217.880 949.280 1219.480 1395.360 ;
    END
    PORT
      LAYER met4 ;
        RECT 1247.880 949.280 1249.480 1395.360 ;
    END
    PORT
      LAYER met4 ;
        RECT 1277.880 949.280 1279.480 1395.360 ;
    END
    PORT
      LAYER met4 ;
        RECT 1307.880 949.280 1309.480 1395.360 ;
    END
    PORT
      LAYER met4 ;
        RECT 1337.880 949.280 1339.480 1395.360 ;
    END
    PORT
      LAYER met4 ;
        RECT 1157.880 503.200 1159.480 949.280 ;
    END
    PORT
      LAYER met4 ;
        RECT 1187.880 503.200 1189.480 949.280 ;
    END
    PORT
      LAYER met4 ;
        RECT 1217.880 503.200 1219.480 949.280 ;
    END
    PORT
      LAYER met4 ;
        RECT 1247.880 503.200 1249.480 949.280 ;
    END
    PORT
      LAYER met4 ;
        RECT 1277.880 503.200 1279.480 949.280 ;
    END
    PORT
      LAYER met4 ;
        RECT 1307.880 503.200 1309.480 949.280 ;
    END
    PORT
      LAYER met4 ;
        RECT 1337.880 503.200 1339.480 949.280 ;
    END
    PORT
      LAYER met4 ;
        RECT 1157.880 57.120 1159.480 503.200 ;
    END
    PORT
      LAYER met4 ;
        RECT 1187.880 57.120 1189.480 503.200 ;
    END
    PORT
      LAYER met4 ;
        RECT 1217.880 57.120 1219.480 503.200 ;
    END
    PORT
      LAYER met4 ;
        RECT 1247.880 57.120 1249.480 503.200 ;
    END
    PORT
      LAYER met4 ;
        RECT 1277.880 57.120 1279.480 503.200 ;
    END
    PORT
      LAYER met4 ;
        RECT 1307.880 57.120 1309.480 503.200 ;
    END
    PORT
      LAYER met4 ;
        RECT 1337.880 57.120 1339.480 503.200 ;
    END
    PORT
      LAYER met4 ;
        RECT 1157.880 0.000 1159.480 57.120 ;
    END
    PORT
      LAYER met4 ;
        RECT 1187.880 0.000 1189.480 57.120 ;
    END
    PORT
      LAYER met4 ;
        RECT 1217.880 0.000 1219.480 57.120 ;
    END
    PORT
      LAYER met4 ;
        RECT 1247.880 0.000 1249.480 57.120 ;
    END
    PORT
      LAYER met4 ;
        RECT 1277.880 0.000 1279.480 57.120 ;
    END
    PORT
      LAYER met4 ;
        RECT 1307.880 0.000 1309.480 57.120 ;
    END
    PORT
      LAYER met4 ;
        RECT 1337.880 0.000 1339.480 57.120 ;
    END
    PORT
      LAYER met4 ;
        RECT 1377.760 1395.360 1379.360 1452.480 ;
    END
    PORT
      LAYER met4 ;
        RECT 1407.760 1395.360 1409.360 1452.480 ;
    END
    PORT
      LAYER met4 ;
        RECT 1437.760 1395.360 1439.360 1452.480 ;
    END
    PORT
      LAYER met4 ;
        RECT 1467.760 1395.360 1469.360 1452.480 ;
    END
    PORT
      LAYER met4 ;
        RECT 1497.760 1395.360 1499.360 1452.480 ;
    END
    PORT
      LAYER met4 ;
        RECT 1527.760 1395.360 1529.360 1452.480 ;
    END
    PORT
      LAYER met4 ;
        RECT 1557.760 1395.360 1559.360 1452.480 ;
    END
    PORT
      LAYER met4 ;
        RECT 1377.760 1172.320 1379.360 1395.360 ;
    END
    PORT
      LAYER met4 ;
        RECT 1407.760 1172.320 1409.360 1395.360 ;
    END
    PORT
      LAYER met4 ;
        RECT 1437.760 1172.320 1439.360 1395.360 ;
    END
    PORT
      LAYER met4 ;
        RECT 1467.760 1172.320 1469.360 1395.360 ;
    END
    PORT
      LAYER met4 ;
        RECT 1497.760 1172.320 1499.360 1395.360 ;
    END
    PORT
      LAYER met4 ;
        RECT 1527.760 1172.320 1529.360 1395.360 ;
    END
    PORT
      LAYER met4 ;
        RECT 1557.760 1172.320 1559.360 1395.360 ;
    END
    PORT
      LAYER met4 ;
        RECT 1377.760 949.280 1379.360 1172.320 ;
    END
    PORT
      LAYER met4 ;
        RECT 1407.760 949.280 1409.360 1172.320 ;
    END
    PORT
      LAYER met4 ;
        RECT 1437.760 949.280 1439.360 1172.320 ;
    END
    PORT
      LAYER met4 ;
        RECT 1467.760 949.280 1469.360 1172.320 ;
    END
    PORT
      LAYER met4 ;
        RECT 1497.760 949.280 1499.360 1172.320 ;
    END
    PORT
      LAYER met4 ;
        RECT 1527.760 949.280 1529.360 1172.320 ;
    END
    PORT
      LAYER met4 ;
        RECT 1557.760 949.280 1559.360 1172.320 ;
    END
    PORT
      LAYER met4 ;
        RECT 1377.760 726.240 1379.360 949.280 ;
    END
    PORT
      LAYER met4 ;
        RECT 1407.760 726.240 1409.360 949.280 ;
    END
    PORT
      LAYER met4 ;
        RECT 1437.760 726.240 1439.360 949.280 ;
    END
    PORT
      LAYER met4 ;
        RECT 1467.760 726.240 1469.360 949.280 ;
    END
    PORT
      LAYER met4 ;
        RECT 1497.760 726.240 1499.360 949.280 ;
    END
    PORT
      LAYER met4 ;
        RECT 1527.760 726.240 1529.360 949.280 ;
    END
    PORT
      LAYER met4 ;
        RECT 1557.760 726.240 1559.360 949.280 ;
    END
    PORT
      LAYER met4 ;
        RECT 1377.760 503.200 1379.360 726.240 ;
    END
    PORT
      LAYER met4 ;
        RECT 1407.760 503.200 1409.360 726.240 ;
    END
    PORT
      LAYER met4 ;
        RECT 1437.760 503.200 1439.360 726.240 ;
    END
    PORT
      LAYER met4 ;
        RECT 1467.760 503.200 1469.360 726.240 ;
    END
    PORT
      LAYER met4 ;
        RECT 1497.760 503.200 1499.360 726.240 ;
    END
    PORT
      LAYER met4 ;
        RECT 1527.760 503.200 1529.360 726.240 ;
    END
    PORT
      LAYER met4 ;
        RECT 1557.760 503.200 1559.360 726.240 ;
    END
    PORT
      LAYER met4 ;
        RECT 1377.760 280.160 1379.360 503.200 ;
    END
    PORT
      LAYER met4 ;
        RECT 1407.760 280.160 1409.360 503.200 ;
    END
    PORT
      LAYER met4 ;
        RECT 1437.760 280.160 1439.360 503.200 ;
    END
    PORT
      LAYER met4 ;
        RECT 1467.760 280.160 1469.360 503.200 ;
    END
    PORT
      LAYER met4 ;
        RECT 1497.760 280.160 1499.360 503.200 ;
    END
    PORT
      LAYER met4 ;
        RECT 1527.760 280.160 1529.360 503.200 ;
    END
    PORT
      LAYER met4 ;
        RECT 1557.760 280.160 1559.360 503.200 ;
    END
    PORT
      LAYER met4 ;
        RECT 1377.760 57.120 1379.360 280.160 ;
    END
    PORT
      LAYER met4 ;
        RECT 1407.760 57.120 1409.360 280.160 ;
    END
    PORT
      LAYER met4 ;
        RECT 1437.760 57.120 1439.360 280.160 ;
    END
    PORT
      LAYER met4 ;
        RECT 1467.760 57.120 1469.360 280.160 ;
    END
    PORT
      LAYER met4 ;
        RECT 1497.760 57.120 1499.360 280.160 ;
    END
    PORT
      LAYER met4 ;
        RECT 1527.760 57.120 1529.360 280.160 ;
    END
    PORT
      LAYER met4 ;
        RECT 1557.760 57.120 1559.360 280.160 ;
    END
    PORT
      LAYER met4 ;
        RECT 1377.760 0.000 1379.360 57.120 ;
    END
    PORT
      LAYER met4 ;
        RECT 1407.760 0.000 1409.360 57.120 ;
    END
    PORT
      LAYER met4 ;
        RECT 1437.760 0.000 1439.360 57.120 ;
    END
    PORT
      LAYER met4 ;
        RECT 1467.760 0.000 1469.360 57.120 ;
    END
    PORT
      LAYER met4 ;
        RECT 1497.760 0.000 1499.360 57.120 ;
    END
    PORT
      LAYER met4 ;
        RECT 1527.760 0.000 1529.360 57.120 ;
    END
    PORT
      LAYER met4 ;
        RECT 1557.760 0.000 1559.360 57.120 ;
    END
    PORT
      LAYER met4 ;
        RECT 1588.440 1395.360 1590.040 1452.480 ;
    END
    PORT
      LAYER met4 ;
        RECT 1618.440 1395.360 1620.040 1452.480 ;
    END
    PORT
      LAYER met4 ;
        RECT 1648.440 1395.360 1650.040 1452.480 ;
    END
    PORT
      LAYER met4 ;
        RECT 1678.440 1395.360 1680.040 1452.480 ;
    END
    PORT
      LAYER met4 ;
        RECT 1708.440 1395.360 1710.040 1452.480 ;
    END
    PORT
      LAYER met4 ;
        RECT 1738.440 1395.360 1740.040 1452.480 ;
    END
    PORT
      LAYER met4 ;
        RECT 1768.440 1395.360 1770.040 1452.480 ;
    END
    PORT
      LAYER met4 ;
        RECT 1588.440 1172.320 1590.040 1395.360 ;
    END
    PORT
      LAYER met4 ;
        RECT 1618.440 1172.320 1620.040 1395.360 ;
    END
    PORT
      LAYER met4 ;
        RECT 1648.440 1172.320 1650.040 1395.360 ;
    END
    PORT
      LAYER met4 ;
        RECT 1678.440 1172.320 1680.040 1395.360 ;
    END
    PORT
      LAYER met4 ;
        RECT 1708.440 1172.320 1710.040 1395.360 ;
    END
    PORT
      LAYER met4 ;
        RECT 1738.440 1172.320 1740.040 1395.360 ;
    END
    PORT
      LAYER met4 ;
        RECT 1768.440 1172.320 1770.040 1395.360 ;
    END
    PORT
      LAYER met4 ;
        RECT 1588.440 949.280 1590.040 1172.320 ;
    END
    PORT
      LAYER met4 ;
        RECT 1618.440 949.280 1620.040 1172.320 ;
    END
    PORT
      LAYER met4 ;
        RECT 1648.440 949.280 1650.040 1172.320 ;
    END
    PORT
      LAYER met4 ;
        RECT 1678.440 949.280 1680.040 1172.320 ;
    END
    PORT
      LAYER met4 ;
        RECT 1708.440 949.280 1710.040 1172.320 ;
    END
    PORT
      LAYER met4 ;
        RECT 1738.440 949.280 1740.040 1172.320 ;
    END
    PORT
      LAYER met4 ;
        RECT 1768.440 949.280 1770.040 1172.320 ;
    END
    PORT
      LAYER met4 ;
        RECT 1588.440 726.240 1590.040 949.280 ;
    END
    PORT
      LAYER met4 ;
        RECT 1618.440 726.240 1620.040 949.280 ;
    END
    PORT
      LAYER met4 ;
        RECT 1648.440 726.240 1650.040 949.280 ;
    END
    PORT
      LAYER met4 ;
        RECT 1678.440 726.240 1680.040 949.280 ;
    END
    PORT
      LAYER met4 ;
        RECT 1708.440 726.240 1710.040 949.280 ;
    END
    PORT
      LAYER met4 ;
        RECT 1738.440 726.240 1740.040 949.280 ;
    END
    PORT
      LAYER met4 ;
        RECT 1768.440 726.240 1770.040 949.280 ;
    END
    PORT
      LAYER met4 ;
        RECT 1588.440 503.200 1590.040 726.240 ;
    END
    PORT
      LAYER met4 ;
        RECT 1618.440 503.200 1620.040 726.240 ;
    END
    PORT
      LAYER met4 ;
        RECT 1648.440 503.200 1650.040 726.240 ;
    END
    PORT
      LAYER met4 ;
        RECT 1678.440 503.200 1680.040 726.240 ;
    END
    PORT
      LAYER met4 ;
        RECT 1708.440 503.200 1710.040 726.240 ;
    END
    PORT
      LAYER met4 ;
        RECT 1738.440 503.200 1740.040 726.240 ;
    END
    PORT
      LAYER met4 ;
        RECT 1768.440 503.200 1770.040 726.240 ;
    END
    PORT
      LAYER met4 ;
        RECT 1588.440 280.160 1590.040 503.200 ;
    END
    PORT
      LAYER met4 ;
        RECT 1618.440 280.160 1620.040 503.200 ;
    END
    PORT
      LAYER met4 ;
        RECT 1648.440 280.160 1650.040 503.200 ;
    END
    PORT
      LAYER met4 ;
        RECT 1678.440 280.160 1680.040 503.200 ;
    END
    PORT
      LAYER met4 ;
        RECT 1708.440 280.160 1710.040 503.200 ;
    END
    PORT
      LAYER met4 ;
        RECT 1738.440 280.160 1740.040 503.200 ;
    END
    PORT
      LAYER met4 ;
        RECT 1768.440 280.160 1770.040 503.200 ;
    END
    PORT
      LAYER met4 ;
        RECT 1588.440 57.120 1590.040 280.160 ;
    END
    PORT
      LAYER met4 ;
        RECT 1618.440 57.120 1620.040 280.160 ;
    END
    PORT
      LAYER met4 ;
        RECT 1648.440 57.120 1650.040 280.160 ;
    END
    PORT
      LAYER met4 ;
        RECT 1678.440 57.120 1680.040 280.160 ;
    END
    PORT
      LAYER met4 ;
        RECT 1708.440 57.120 1710.040 280.160 ;
    END
    PORT
      LAYER met4 ;
        RECT 1738.440 57.120 1740.040 280.160 ;
    END
    PORT
      LAYER met4 ;
        RECT 1768.440 57.120 1770.040 280.160 ;
    END
    PORT
      LAYER met4 ;
        RECT 1588.440 0.000 1590.040 57.120 ;
    END
    PORT
      LAYER met4 ;
        RECT 1618.440 0.000 1620.040 57.120 ;
    END
    PORT
      LAYER met4 ;
        RECT 1648.440 0.000 1650.040 57.120 ;
    END
    PORT
      LAYER met4 ;
        RECT 1678.440 0.000 1680.040 57.120 ;
    END
    PORT
      LAYER met4 ;
        RECT 1708.440 0.000 1710.040 57.120 ;
    END
    PORT
      LAYER met4 ;
        RECT 1738.440 0.000 1740.040 57.120 ;
    END
    PORT
      LAYER met4 ;
        RECT 1768.440 0.000 1770.040 57.120 ;
    END
    PORT
      LAYER met4 ;
        RECT 1799.120 1395.360 1800.720 1452.480 ;
    END
    PORT
      LAYER met4 ;
        RECT 1829.120 1395.360 1830.720 1452.480 ;
    END
    PORT
      LAYER met4 ;
        RECT 1799.120 1172.320 1800.720 1395.360 ;
    END
    PORT
      LAYER met4 ;
        RECT 1829.120 1172.320 1830.720 1395.360 ;
    END
    PORT
      LAYER met4 ;
        RECT 1799.120 949.280 1800.720 1172.320 ;
    END
    PORT
      LAYER met4 ;
        RECT 1829.120 949.280 1830.720 1172.320 ;
    END
    PORT
      LAYER met4 ;
        RECT 1799.120 726.240 1800.720 949.280 ;
    END
    PORT
      LAYER met4 ;
        RECT 1829.120 726.240 1830.720 949.280 ;
    END
    PORT
      LAYER met4 ;
        RECT 1799.120 503.200 1800.720 726.240 ;
    END
    PORT
      LAYER met4 ;
        RECT 1829.120 503.200 1830.720 726.240 ;
    END
    PORT
      LAYER met4 ;
        RECT 1799.120 280.160 1800.720 503.200 ;
    END
    PORT
      LAYER met4 ;
        RECT 1829.120 280.160 1830.720 503.200 ;
    END
    PORT
      LAYER met4 ;
        RECT 1799.120 57.120 1800.720 280.160 ;
    END
    PORT
      LAYER met4 ;
        RECT 1829.120 57.120 1830.720 280.160 ;
    END
    PORT
      LAYER met4 ;
        RECT 1799.120 0.000 1800.720 57.120 ;
    END
    PORT
      LAYER met4 ;
        RECT 1829.120 0.000 1830.720 57.120 ;
    END
  END VPWR
  OBS
      LAYER nwell ;
        RECT 2.570 2.635 1845.710 1449.950 ;
      LAYER li1 ;
        RECT 2.760 2.635 1845.520 1449.845 ;
      LAYER met1 ;
        RECT 0.530 0.380 1847.290 1451.760 ;
      LAYER met2 ;
        RECT 0.160 0.560 1847.270 1452.480 ;
        RECT 0.160 0.270 4.410 0.560 ;
        RECT 5.250 0.270 6.710 0.560 ;
        RECT 7.550 0.270 9.010 0.560 ;
        RECT 9.850 0.270 11.310 0.560 ;
        RECT 12.150 0.270 13.610 0.560 ;
        RECT 14.450 0.270 15.910 0.560 ;
        RECT 16.750 0.270 18.210 0.560 ;
        RECT 19.050 0.270 20.510 0.560 ;
        RECT 21.350 0.270 22.810 0.560 ;
        RECT 23.650 0.270 25.110 0.560 ;
        RECT 25.950 0.270 27.410 0.560 ;
        RECT 28.250 0.270 29.710 0.560 ;
        RECT 30.550 0.270 32.010 0.560 ;
        RECT 32.850 0.270 34.310 0.560 ;
        RECT 35.150 0.270 36.610 0.560 ;
        RECT 37.450 0.270 38.910 0.560 ;
        RECT 39.750 0.270 41.210 0.560 ;
        RECT 42.050 0.270 43.510 0.560 ;
        RECT 44.350 0.270 45.810 0.560 ;
        RECT 46.650 0.270 48.110 0.560 ;
        RECT 48.950 0.270 50.410 0.560 ;
        RECT 51.250 0.270 64.670 0.560 ;
        RECT 65.510 0.270 74.790 0.560 ;
        RECT 75.630 0.270 84.910 0.560 ;
        RECT 85.750 0.270 95.030 0.560 ;
        RECT 95.870 0.270 105.150 0.560 ;
        RECT 105.990 0.270 115.270 0.560 ;
        RECT 116.110 0.270 125.390 0.560 ;
        RECT 126.230 0.270 135.510 0.560 ;
        RECT 136.350 0.270 145.630 0.560 ;
        RECT 146.470 0.270 155.750 0.560 ;
        RECT 156.590 0.270 165.870 0.560 ;
        RECT 166.710 0.270 175.990 0.560 ;
        RECT 176.830 0.270 186.110 0.560 ;
        RECT 186.950 0.270 196.230 0.560 ;
        RECT 197.070 0.270 206.350 0.560 ;
        RECT 207.190 0.270 216.470 0.560 ;
        RECT 217.310 0.270 226.590 0.560 ;
        RECT 227.430 0.270 236.710 0.560 ;
        RECT 237.550 0.270 246.830 0.560 ;
        RECT 247.670 0.270 256.950 0.560 ;
        RECT 257.790 0.270 275.350 0.560 ;
        RECT 276.190 0.270 285.470 0.560 ;
        RECT 286.310 0.270 295.590 0.560 ;
        RECT 296.430 0.270 305.710 0.560 ;
        RECT 306.550 0.270 315.830 0.560 ;
        RECT 316.670 0.270 325.950 0.560 ;
        RECT 326.790 0.270 336.070 0.560 ;
        RECT 336.910 0.270 346.190 0.560 ;
        RECT 347.030 0.270 356.310 0.560 ;
        RECT 357.150 0.270 366.430 0.560 ;
        RECT 367.270 0.270 376.550 0.560 ;
        RECT 377.390 0.270 386.670 0.560 ;
        RECT 387.510 0.270 396.790 0.560 ;
        RECT 397.630 0.270 406.910 0.560 ;
        RECT 407.750 0.270 417.030 0.560 ;
        RECT 417.870 0.270 427.150 0.560 ;
        RECT 427.990 0.270 437.270 0.560 ;
        RECT 438.110 0.270 447.390 0.560 ;
        RECT 448.230 0.270 457.510 0.560 ;
        RECT 458.350 0.270 467.630 0.560 ;
        RECT 468.470 0.270 485.110 0.560 ;
        RECT 485.950 0.270 497.530 0.560 ;
        RECT 498.370 0.270 509.950 0.560 ;
        RECT 510.790 0.270 522.370 0.560 ;
        RECT 523.210 0.270 534.790 0.560 ;
        RECT 535.630 0.270 547.210 0.560 ;
        RECT 548.050 0.270 559.630 0.560 ;
        RECT 560.470 0.270 572.050 0.560 ;
        RECT 572.890 0.270 584.470 0.560 ;
        RECT 585.310 0.270 596.890 0.560 ;
        RECT 597.730 0.270 609.310 0.560 ;
        RECT 610.150 0.270 621.730 0.560 ;
        RECT 622.570 0.270 634.150 0.560 ;
        RECT 634.990 0.270 646.570 0.560 ;
        RECT 647.410 0.270 658.990 0.560 ;
        RECT 659.830 0.270 671.410 0.560 ;
        RECT 672.250 0.270 683.830 0.560 ;
        RECT 684.670 0.270 696.250 0.560 ;
        RECT 697.090 0.270 708.670 0.560 ;
        RECT 709.510 0.270 721.090 0.560 ;
        RECT 721.930 0.270 738.110 0.560 ;
        RECT 738.950 0.270 748.230 0.560 ;
        RECT 749.070 0.270 758.350 0.560 ;
        RECT 759.190 0.270 768.470 0.560 ;
        RECT 769.310 0.270 778.590 0.560 ;
        RECT 779.430 0.270 788.710 0.560 ;
        RECT 789.550 0.270 798.830 0.560 ;
        RECT 799.670 0.270 808.950 0.560 ;
        RECT 809.790 0.270 819.070 0.560 ;
        RECT 819.910 0.270 829.190 0.560 ;
        RECT 830.030 0.270 839.310 0.560 ;
        RECT 840.150 0.270 849.430 0.560 ;
        RECT 850.270 0.270 859.550 0.560 ;
        RECT 860.390 0.270 869.670 0.560 ;
        RECT 870.510 0.270 879.790 0.560 ;
        RECT 880.630 0.270 889.910 0.560 ;
        RECT 890.750 0.270 900.030 0.560 ;
        RECT 900.870 0.270 910.150 0.560 ;
        RECT 910.990 0.270 920.270 0.560 ;
        RECT 921.110 0.270 930.390 0.560 ;
        RECT 931.230 0.270 948.790 0.560 ;
        RECT 949.630 0.270 958.910 0.560 ;
        RECT 959.750 0.270 969.030 0.560 ;
        RECT 969.870 0.270 979.150 0.560 ;
        RECT 979.990 0.270 989.270 0.560 ;
        RECT 990.110 0.270 999.390 0.560 ;
        RECT 1000.230 0.270 1009.510 0.560 ;
        RECT 1010.350 0.270 1019.630 0.560 ;
        RECT 1020.470 0.270 1029.750 0.560 ;
        RECT 1030.590 0.270 1039.870 0.560 ;
        RECT 1040.710 0.270 1049.990 0.560 ;
        RECT 1050.830 0.270 1060.110 0.560 ;
        RECT 1060.950 0.270 1070.230 0.560 ;
        RECT 1071.070 0.270 1080.350 0.560 ;
        RECT 1081.190 0.270 1090.470 0.560 ;
        RECT 1091.310 0.270 1100.590 0.560 ;
        RECT 1101.430 0.270 1110.710 0.560 ;
        RECT 1111.550 0.270 1120.830 0.560 ;
        RECT 1121.670 0.270 1130.950 0.560 ;
        RECT 1131.790 0.270 1141.070 0.560 ;
        RECT 1141.910 0.270 1159.930 0.560 ;
        RECT 1160.770 0.270 1170.510 0.560 ;
        RECT 1171.350 0.270 1181.090 0.560 ;
        RECT 1181.930 0.270 1191.670 0.560 ;
        RECT 1192.510 0.270 1202.250 0.560 ;
        RECT 1203.090 0.270 1212.830 0.560 ;
        RECT 1213.670 0.270 1223.410 0.560 ;
        RECT 1224.250 0.270 1233.990 0.560 ;
        RECT 1234.830 0.270 1244.570 0.560 ;
        RECT 1245.410 0.270 1255.150 0.560 ;
        RECT 1255.990 0.270 1265.730 0.560 ;
        RECT 1266.570 0.270 1276.310 0.560 ;
        RECT 1277.150 0.270 1286.890 0.560 ;
        RECT 1287.730 0.270 1297.470 0.560 ;
        RECT 1298.310 0.270 1308.050 0.560 ;
        RECT 1308.890 0.270 1318.630 0.560 ;
        RECT 1319.470 0.270 1329.210 0.560 ;
        RECT 1330.050 0.270 1339.790 0.560 ;
        RECT 1340.630 0.270 1350.370 0.560 ;
        RECT 1351.210 0.270 1360.950 0.560 ;
        RECT 1361.790 0.270 1379.350 0.560 ;
        RECT 1380.190 0.270 1389.470 0.560 ;
        RECT 1390.310 0.270 1399.590 0.560 ;
        RECT 1400.430 0.270 1409.710 0.560 ;
        RECT 1410.550 0.270 1419.830 0.560 ;
        RECT 1420.670 0.270 1429.950 0.560 ;
        RECT 1430.790 0.270 1440.070 0.560 ;
        RECT 1440.910 0.270 1450.190 0.560 ;
        RECT 1451.030 0.270 1460.310 0.560 ;
        RECT 1461.150 0.270 1470.430 0.560 ;
        RECT 1471.270 0.270 1480.550 0.560 ;
        RECT 1481.390 0.270 1490.670 0.560 ;
        RECT 1491.510 0.270 1500.790 0.560 ;
        RECT 1501.630 0.270 1510.910 0.560 ;
        RECT 1511.750 0.270 1521.030 0.560 ;
        RECT 1521.870 0.270 1531.150 0.560 ;
        RECT 1531.990 0.270 1541.270 0.560 ;
        RECT 1542.110 0.270 1551.390 0.560 ;
        RECT 1552.230 0.270 1561.510 0.560 ;
        RECT 1562.350 0.270 1571.630 0.560 ;
        RECT 1572.470 0.270 1590.030 0.560 ;
        RECT 1590.870 0.270 1600.150 0.560 ;
        RECT 1600.990 0.270 1610.270 0.560 ;
        RECT 1611.110 0.270 1620.390 0.560 ;
        RECT 1621.230 0.270 1630.510 0.560 ;
        RECT 1631.350 0.270 1640.630 0.560 ;
        RECT 1641.470 0.270 1650.750 0.560 ;
        RECT 1651.590 0.270 1660.870 0.560 ;
        RECT 1661.710 0.270 1670.990 0.560 ;
        RECT 1671.830 0.270 1681.110 0.560 ;
        RECT 1681.950 0.270 1691.230 0.560 ;
        RECT 1692.070 0.270 1701.350 0.560 ;
        RECT 1702.190 0.270 1711.470 0.560 ;
        RECT 1712.310 0.270 1721.590 0.560 ;
        RECT 1722.430 0.270 1731.710 0.560 ;
        RECT 1732.550 0.270 1741.830 0.560 ;
        RECT 1742.670 0.270 1751.950 0.560 ;
        RECT 1752.790 0.270 1762.070 0.560 ;
        RECT 1762.910 0.270 1772.190 0.560 ;
        RECT 1773.030 0.270 1782.310 0.560 ;
        RECT 1783.150 0.270 1793.350 0.560 ;
        RECT 1794.190 0.270 1796.110 0.560 ;
        RECT 1796.950 0.270 1798.870 0.560 ;
        RECT 1799.710 0.270 1801.630 0.560 ;
        RECT 1802.470 0.270 1804.390 0.560 ;
        RECT 1805.230 0.270 1807.150 0.560 ;
        RECT 1807.990 0.270 1809.910 0.560 ;
        RECT 1810.750 0.270 1812.670 0.560 ;
        RECT 1813.510 0.270 1815.430 0.560 ;
        RECT 1816.270 0.270 1818.190 0.560 ;
        RECT 1819.030 0.270 1820.950 0.560 ;
        RECT 1821.790 0.270 1823.710 0.560 ;
        RECT 1824.550 0.270 1826.470 0.560 ;
        RECT 1827.310 0.270 1829.230 0.560 ;
        RECT 1830.070 0.270 1831.990 0.560 ;
        RECT 1832.830 0.270 1834.750 0.560 ;
        RECT 1835.590 0.270 1837.510 0.560 ;
        RECT 1838.350 0.270 1840.270 0.560 ;
        RECT 1841.110 0.270 1843.030 0.560 ;
        RECT 1843.870 0.270 1845.790 0.560 ;
        RECT 1846.630 0.270 1847.270 0.560 ;
      LAYER met3 ;
        RECT 0.525 1445.360 1848.280 1449.925 ;
        RECT 1.000 1401.800 1848.280 1445.360 ;
        RECT 0.525 1384.160 1848.280 1401.800 ;
        RECT 1.000 1382.760 1848.280 1384.160 ;
        RECT 0.525 1378.720 1848.280 1382.760 ;
        RECT 1.000 1377.320 1848.280 1378.720 ;
        RECT 0.525 1373.280 1848.280 1377.320 ;
        RECT 1.000 1371.880 1848.280 1373.280 ;
        RECT 0.525 1367.840 1848.280 1371.880 ;
        RECT 1.000 1366.440 1848.280 1367.840 ;
        RECT 0.525 1362.400 1848.280 1366.440 ;
        RECT 1.000 1361.000 1848.280 1362.400 ;
        RECT 0.525 1356.960 1848.280 1361.000 ;
        RECT 1.000 1355.560 1848.280 1356.960 ;
        RECT 0.525 1351.520 1848.280 1355.560 ;
        RECT 1.000 1350.120 1848.280 1351.520 ;
        RECT 0.525 1346.080 1848.280 1350.120 ;
        RECT 1.000 1344.680 1848.280 1346.080 ;
        RECT 0.525 1340.640 1848.280 1344.680 ;
        RECT 1.000 1339.240 1848.280 1340.640 ;
        RECT 0.525 1335.200 1848.280 1339.240 ;
        RECT 1.000 1333.800 1848.280 1335.200 ;
        RECT 0.525 1329.760 1848.280 1333.800 ;
        RECT 1.000 1328.360 1848.280 1329.760 ;
        RECT 0.525 1324.320 1848.280 1328.360 ;
        RECT 1.000 1322.920 1848.280 1324.320 ;
        RECT 0.525 1318.880 1848.280 1322.920 ;
        RECT 1.000 1317.480 1848.280 1318.880 ;
        RECT 0.525 1313.440 1848.280 1317.480 ;
        RECT 1.000 1312.040 1848.280 1313.440 ;
        RECT 0.525 1308.000 1848.280 1312.040 ;
        RECT 1.000 1306.600 1848.280 1308.000 ;
        RECT 0.525 1302.560 1848.280 1306.600 ;
        RECT 1.000 1301.160 1848.280 1302.560 ;
        RECT 0.525 1297.120 1848.280 1301.160 ;
        RECT 1.000 1295.720 1848.280 1297.120 ;
        RECT 0.525 1291.680 1848.280 1295.720 ;
        RECT 1.000 1290.280 1848.280 1291.680 ;
        RECT 0.525 1286.240 1848.280 1290.280 ;
        RECT 1.000 1284.840 1848.280 1286.240 ;
        RECT 0.525 1280.800 1848.280 1284.840 ;
        RECT 1.000 1279.400 1848.280 1280.800 ;
        RECT 0.525 1275.360 1848.280 1279.400 ;
        RECT 1.000 1273.960 1848.280 1275.360 ;
        RECT 0.525 1269.920 1848.280 1273.960 ;
        RECT 1.000 1268.520 1848.280 1269.920 ;
        RECT 0.525 1264.480 1848.280 1268.520 ;
        RECT 1.000 1263.080 1848.280 1264.480 ;
        RECT 0.525 1259.040 1848.280 1263.080 ;
        RECT 1.000 1257.640 1848.280 1259.040 ;
        RECT 0.525 1253.600 1848.280 1257.640 ;
        RECT 1.000 1252.200 1848.280 1253.600 ;
        RECT 0.525 1248.160 1848.280 1252.200 ;
        RECT 1.000 1246.760 1848.280 1248.160 ;
        RECT 0.525 1242.720 1848.280 1246.760 ;
        RECT 1.000 1241.320 1848.280 1242.720 ;
        RECT 0.525 1237.280 1848.280 1241.320 ;
        RECT 1.000 1235.880 1848.280 1237.280 ;
        RECT 0.525 1231.840 1848.280 1235.880 ;
        RECT 1.000 1230.440 1848.280 1231.840 ;
        RECT 0.525 1226.400 1848.280 1230.440 ;
        RECT 1.000 1225.000 1848.280 1226.400 ;
        RECT 0.525 1220.960 1848.280 1225.000 ;
        RECT 1.000 1219.560 1848.280 1220.960 ;
        RECT 0.525 1215.520 1848.280 1219.560 ;
        RECT 1.000 1214.120 1848.280 1215.520 ;
        RECT 0.525 1210.080 1848.280 1214.120 ;
        RECT 1.000 1208.680 1847.280 1210.080 ;
        RECT 0.525 1204.640 1848.280 1208.680 ;
        RECT 1.000 1203.240 1847.280 1204.640 ;
        RECT 0.525 1199.200 1848.280 1203.240 ;
        RECT 1.000 1197.800 1847.280 1199.200 ;
        RECT 0.525 1193.760 1848.280 1197.800 ;
        RECT 1.000 1192.360 1847.280 1193.760 ;
        RECT 0.525 1188.320 1848.280 1192.360 ;
        RECT 1.000 1186.920 1847.280 1188.320 ;
        RECT 0.525 1182.880 1848.280 1186.920 ;
        RECT 1.000 1181.480 1847.280 1182.880 ;
        RECT 0.525 1161.120 1848.280 1181.480 ;
        RECT 1.000 1159.720 1848.280 1161.120 ;
        RECT 0.525 1155.680 1848.280 1159.720 ;
        RECT 1.000 1154.280 1848.280 1155.680 ;
        RECT 0.525 1150.240 1848.280 1154.280 ;
        RECT 1.000 1148.840 1848.280 1150.240 ;
        RECT 0.525 1144.800 1848.280 1148.840 ;
        RECT 1.000 1143.400 1848.280 1144.800 ;
        RECT 0.525 1139.360 1848.280 1143.400 ;
        RECT 1.000 1137.960 1848.280 1139.360 ;
        RECT 0.525 1133.920 1848.280 1137.960 ;
        RECT 1.000 1132.520 1848.280 1133.920 ;
        RECT 0.525 1128.480 1848.280 1132.520 ;
        RECT 1.000 1127.080 1848.280 1128.480 ;
        RECT 0.525 1123.040 1848.280 1127.080 ;
        RECT 1.000 1121.640 1848.280 1123.040 ;
        RECT 0.525 1117.600 1848.280 1121.640 ;
        RECT 1.000 1116.200 1848.280 1117.600 ;
        RECT 0.525 1112.160 1848.280 1116.200 ;
        RECT 1.000 1110.760 1848.280 1112.160 ;
        RECT 0.525 1106.720 1848.280 1110.760 ;
        RECT 1.000 1105.320 1848.280 1106.720 ;
        RECT 0.525 1101.280 1848.280 1105.320 ;
        RECT 1.000 1099.880 1848.280 1101.280 ;
        RECT 0.525 1095.840 1848.280 1099.880 ;
        RECT 1.000 1094.440 1848.280 1095.840 ;
        RECT 0.525 1090.400 1848.280 1094.440 ;
        RECT 1.000 1089.000 1848.280 1090.400 ;
        RECT 0.525 1084.960 1848.280 1089.000 ;
        RECT 1.000 1083.560 1848.280 1084.960 ;
        RECT 0.525 1079.520 1848.280 1083.560 ;
        RECT 1.000 1078.120 1848.280 1079.520 ;
        RECT 0.525 1074.080 1848.280 1078.120 ;
        RECT 1.000 1072.680 1848.280 1074.080 ;
        RECT 0.525 1068.640 1848.280 1072.680 ;
        RECT 1.000 1067.240 1848.280 1068.640 ;
        RECT 0.525 1063.200 1848.280 1067.240 ;
        RECT 1.000 1061.800 1848.280 1063.200 ;
        RECT 0.525 1057.760 1848.280 1061.800 ;
        RECT 1.000 1056.360 1848.280 1057.760 ;
        RECT 0.525 1052.320 1848.280 1056.360 ;
        RECT 1.000 1050.920 1848.280 1052.320 ;
        RECT 0.525 1046.880 1848.280 1050.920 ;
        RECT 1.000 1045.480 1848.280 1046.880 ;
        RECT 0.525 1041.440 1848.280 1045.480 ;
        RECT 1.000 1040.040 1848.280 1041.440 ;
        RECT 0.525 1036.000 1848.280 1040.040 ;
        RECT 1.000 1034.600 1848.280 1036.000 ;
        RECT 0.525 1030.560 1848.280 1034.600 ;
        RECT 1.000 1029.160 1848.280 1030.560 ;
        RECT 0.525 1025.120 1848.280 1029.160 ;
        RECT 1.000 1023.720 1848.280 1025.120 ;
        RECT 0.525 1019.680 1848.280 1023.720 ;
        RECT 1.000 1018.280 1848.280 1019.680 ;
        RECT 0.525 1014.240 1848.280 1018.280 ;
        RECT 1.000 1012.840 1848.280 1014.240 ;
        RECT 0.525 1008.800 1848.280 1012.840 ;
        RECT 1.000 1007.400 1848.280 1008.800 ;
        RECT 0.525 1003.360 1848.280 1007.400 ;
        RECT 1.000 1001.960 1848.280 1003.360 ;
        RECT 0.525 997.920 1848.280 1001.960 ;
        RECT 1.000 996.520 1848.280 997.920 ;
        RECT 0.525 992.480 1848.280 996.520 ;
        RECT 1.000 991.080 1848.280 992.480 ;
        RECT 0.525 987.040 1848.280 991.080 ;
        RECT 1.000 985.640 1847.280 987.040 ;
        RECT 0.525 981.600 1848.280 985.640 ;
        RECT 1.000 980.200 1847.280 981.600 ;
        RECT 0.525 976.160 1848.280 980.200 ;
        RECT 1.000 974.760 1847.280 976.160 ;
        RECT 0.525 970.720 1848.280 974.760 ;
        RECT 1.000 969.320 1847.280 970.720 ;
        RECT 0.525 965.280 1848.280 969.320 ;
        RECT 1.000 963.880 1847.280 965.280 ;
        RECT 0.525 959.840 1848.280 963.880 ;
        RECT 1.000 958.440 1847.280 959.840 ;
        RECT 0.525 938.080 1848.280 958.440 ;
        RECT 1.000 936.680 1848.280 938.080 ;
        RECT 0.525 932.640 1848.280 936.680 ;
        RECT 1.000 931.240 1848.280 932.640 ;
        RECT 0.525 927.200 1848.280 931.240 ;
        RECT 1.000 925.800 1848.280 927.200 ;
        RECT 0.525 921.760 1848.280 925.800 ;
        RECT 1.000 920.360 1848.280 921.760 ;
        RECT 0.525 916.320 1848.280 920.360 ;
        RECT 1.000 914.920 1848.280 916.320 ;
        RECT 0.525 910.880 1848.280 914.920 ;
        RECT 1.000 909.480 1848.280 910.880 ;
        RECT 0.525 905.440 1848.280 909.480 ;
        RECT 1.000 904.040 1848.280 905.440 ;
        RECT 0.525 900.000 1848.280 904.040 ;
        RECT 1.000 898.600 1848.280 900.000 ;
        RECT 0.525 894.560 1848.280 898.600 ;
        RECT 1.000 893.160 1848.280 894.560 ;
        RECT 0.525 889.120 1848.280 893.160 ;
        RECT 1.000 887.720 1848.280 889.120 ;
        RECT 0.525 883.680 1848.280 887.720 ;
        RECT 1.000 882.280 1848.280 883.680 ;
        RECT 0.525 878.240 1848.280 882.280 ;
        RECT 1.000 876.840 1848.280 878.240 ;
        RECT 0.525 872.800 1848.280 876.840 ;
        RECT 1.000 871.400 1848.280 872.800 ;
        RECT 0.525 867.360 1848.280 871.400 ;
        RECT 1.000 865.960 1848.280 867.360 ;
        RECT 0.525 861.920 1848.280 865.960 ;
        RECT 1.000 860.520 1848.280 861.920 ;
        RECT 0.525 856.480 1848.280 860.520 ;
        RECT 1.000 855.080 1848.280 856.480 ;
        RECT 0.525 851.040 1848.280 855.080 ;
        RECT 1.000 849.640 1848.280 851.040 ;
        RECT 0.525 845.600 1848.280 849.640 ;
        RECT 1.000 844.200 1848.280 845.600 ;
        RECT 0.525 840.160 1848.280 844.200 ;
        RECT 1.000 838.760 1848.280 840.160 ;
        RECT 0.525 834.720 1848.280 838.760 ;
        RECT 1.000 833.320 1848.280 834.720 ;
        RECT 0.525 829.280 1848.280 833.320 ;
        RECT 1.000 827.880 1848.280 829.280 ;
        RECT 0.525 823.840 1848.280 827.880 ;
        RECT 1.000 822.440 1848.280 823.840 ;
        RECT 0.525 818.400 1848.280 822.440 ;
        RECT 1.000 817.000 1848.280 818.400 ;
        RECT 0.525 812.960 1848.280 817.000 ;
        RECT 1.000 811.560 1848.280 812.960 ;
        RECT 0.525 807.520 1848.280 811.560 ;
        RECT 1.000 806.120 1848.280 807.520 ;
        RECT 0.525 802.080 1848.280 806.120 ;
        RECT 1.000 800.680 1848.280 802.080 ;
        RECT 0.525 796.640 1848.280 800.680 ;
        RECT 1.000 795.240 1848.280 796.640 ;
        RECT 0.525 791.200 1848.280 795.240 ;
        RECT 1.000 789.800 1848.280 791.200 ;
        RECT 0.525 785.760 1848.280 789.800 ;
        RECT 1.000 784.360 1848.280 785.760 ;
        RECT 0.525 780.320 1848.280 784.360 ;
        RECT 1.000 778.920 1848.280 780.320 ;
        RECT 0.525 774.880 1848.280 778.920 ;
        RECT 1.000 773.480 1848.280 774.880 ;
        RECT 0.525 769.440 1848.280 773.480 ;
        RECT 1.000 768.040 1848.280 769.440 ;
        RECT 0.525 764.000 1848.280 768.040 ;
        RECT 1.000 762.600 1847.280 764.000 ;
        RECT 0.525 758.560 1848.280 762.600 ;
        RECT 1.000 757.160 1847.280 758.560 ;
        RECT 0.525 753.120 1848.280 757.160 ;
        RECT 1.000 751.720 1847.280 753.120 ;
        RECT 0.525 747.680 1848.280 751.720 ;
        RECT 1.000 746.280 1847.280 747.680 ;
        RECT 0.525 742.240 1848.280 746.280 ;
        RECT 1.000 740.840 1847.280 742.240 ;
        RECT 0.525 736.800 1848.280 740.840 ;
        RECT 1.000 735.400 1847.280 736.800 ;
        RECT 0.525 715.040 1848.280 735.400 ;
        RECT 1.000 713.640 1848.280 715.040 ;
        RECT 0.525 709.600 1848.280 713.640 ;
        RECT 1.000 708.200 1848.280 709.600 ;
        RECT 0.525 704.160 1848.280 708.200 ;
        RECT 1.000 702.760 1848.280 704.160 ;
        RECT 0.525 698.720 1848.280 702.760 ;
        RECT 1.000 697.320 1848.280 698.720 ;
        RECT 0.525 693.280 1848.280 697.320 ;
        RECT 1.000 691.880 1848.280 693.280 ;
        RECT 0.525 687.840 1848.280 691.880 ;
        RECT 1.000 686.440 1848.280 687.840 ;
        RECT 0.525 682.400 1848.280 686.440 ;
        RECT 1.000 681.000 1848.280 682.400 ;
        RECT 0.525 676.960 1848.280 681.000 ;
        RECT 1.000 675.560 1848.280 676.960 ;
        RECT 0.525 671.520 1848.280 675.560 ;
        RECT 1.000 670.120 1848.280 671.520 ;
        RECT 0.525 666.080 1848.280 670.120 ;
        RECT 1.000 664.680 1848.280 666.080 ;
        RECT 0.525 660.640 1848.280 664.680 ;
        RECT 1.000 659.240 1848.280 660.640 ;
        RECT 0.525 655.200 1848.280 659.240 ;
        RECT 1.000 653.800 1848.280 655.200 ;
        RECT 0.525 649.760 1848.280 653.800 ;
        RECT 1.000 648.360 1848.280 649.760 ;
        RECT 0.525 644.320 1848.280 648.360 ;
        RECT 1.000 642.920 1848.280 644.320 ;
        RECT 0.525 638.880 1848.280 642.920 ;
        RECT 1.000 637.480 1848.280 638.880 ;
        RECT 0.525 633.440 1848.280 637.480 ;
        RECT 1.000 632.040 1848.280 633.440 ;
        RECT 0.525 628.000 1848.280 632.040 ;
        RECT 1.000 626.600 1848.280 628.000 ;
        RECT 0.525 622.560 1848.280 626.600 ;
        RECT 1.000 621.160 1848.280 622.560 ;
        RECT 0.525 617.120 1848.280 621.160 ;
        RECT 1.000 615.720 1848.280 617.120 ;
        RECT 0.525 611.680 1848.280 615.720 ;
        RECT 1.000 610.280 1848.280 611.680 ;
        RECT 0.525 606.240 1848.280 610.280 ;
        RECT 1.000 604.840 1848.280 606.240 ;
        RECT 0.525 600.800 1848.280 604.840 ;
        RECT 1.000 599.400 1848.280 600.800 ;
        RECT 0.525 595.360 1848.280 599.400 ;
        RECT 1.000 593.960 1848.280 595.360 ;
        RECT 0.525 589.920 1848.280 593.960 ;
        RECT 1.000 588.520 1848.280 589.920 ;
        RECT 0.525 584.480 1848.280 588.520 ;
        RECT 1.000 583.080 1848.280 584.480 ;
        RECT 0.525 579.040 1848.280 583.080 ;
        RECT 1.000 577.640 1848.280 579.040 ;
        RECT 0.525 573.600 1848.280 577.640 ;
        RECT 1.000 572.200 1848.280 573.600 ;
        RECT 0.525 568.160 1848.280 572.200 ;
        RECT 1.000 566.760 1848.280 568.160 ;
        RECT 0.525 562.720 1848.280 566.760 ;
        RECT 1.000 561.320 1848.280 562.720 ;
        RECT 0.525 557.280 1848.280 561.320 ;
        RECT 1.000 555.880 1848.280 557.280 ;
        RECT 0.525 551.840 1848.280 555.880 ;
        RECT 1.000 550.440 1848.280 551.840 ;
        RECT 0.525 546.400 1848.280 550.440 ;
        RECT 1.000 545.000 1848.280 546.400 ;
        RECT 0.525 540.960 1848.280 545.000 ;
        RECT 1.000 539.560 1847.280 540.960 ;
        RECT 0.525 535.520 1848.280 539.560 ;
        RECT 1.000 534.120 1847.280 535.520 ;
        RECT 0.525 530.080 1848.280 534.120 ;
        RECT 1.000 528.680 1847.280 530.080 ;
        RECT 0.525 524.640 1848.280 528.680 ;
        RECT 1.000 523.240 1847.280 524.640 ;
        RECT 0.525 519.200 1848.280 523.240 ;
        RECT 1.000 517.800 1847.280 519.200 ;
        RECT 0.525 513.760 1848.280 517.800 ;
        RECT 1.000 512.360 1847.280 513.760 ;
        RECT 0.525 492.000 1848.280 512.360 ;
        RECT 1.000 490.600 1848.280 492.000 ;
        RECT 0.525 486.560 1848.280 490.600 ;
        RECT 1.000 485.160 1848.280 486.560 ;
        RECT 0.525 481.120 1848.280 485.160 ;
        RECT 1.000 479.720 1848.280 481.120 ;
        RECT 0.525 475.680 1848.280 479.720 ;
        RECT 1.000 474.280 1848.280 475.680 ;
        RECT 0.525 470.240 1848.280 474.280 ;
        RECT 1.000 468.840 1848.280 470.240 ;
        RECT 0.525 464.800 1848.280 468.840 ;
        RECT 1.000 463.400 1848.280 464.800 ;
        RECT 0.525 459.360 1848.280 463.400 ;
        RECT 1.000 457.960 1848.280 459.360 ;
        RECT 0.525 453.920 1848.280 457.960 ;
        RECT 1.000 452.520 1848.280 453.920 ;
        RECT 0.525 448.480 1848.280 452.520 ;
        RECT 1.000 447.080 1848.280 448.480 ;
        RECT 0.525 443.040 1848.280 447.080 ;
        RECT 1.000 441.640 1848.280 443.040 ;
        RECT 0.525 437.600 1848.280 441.640 ;
        RECT 1.000 436.200 1848.280 437.600 ;
        RECT 0.525 432.160 1848.280 436.200 ;
        RECT 1.000 430.760 1848.280 432.160 ;
        RECT 0.525 426.720 1848.280 430.760 ;
        RECT 1.000 425.320 1848.280 426.720 ;
        RECT 0.525 421.280 1848.280 425.320 ;
        RECT 1.000 419.880 1848.280 421.280 ;
        RECT 0.525 415.840 1848.280 419.880 ;
        RECT 1.000 414.440 1848.280 415.840 ;
        RECT 0.525 410.400 1848.280 414.440 ;
        RECT 1.000 409.000 1848.280 410.400 ;
        RECT 0.525 404.960 1848.280 409.000 ;
        RECT 1.000 403.560 1848.280 404.960 ;
        RECT 0.525 399.520 1848.280 403.560 ;
        RECT 1.000 398.120 1848.280 399.520 ;
        RECT 0.525 394.080 1848.280 398.120 ;
        RECT 1.000 392.680 1848.280 394.080 ;
        RECT 0.525 388.640 1848.280 392.680 ;
        RECT 1.000 387.240 1848.280 388.640 ;
        RECT 0.525 383.200 1848.280 387.240 ;
        RECT 1.000 381.800 1848.280 383.200 ;
        RECT 0.525 377.760 1848.280 381.800 ;
        RECT 1.000 376.360 1848.280 377.760 ;
        RECT 0.525 372.320 1848.280 376.360 ;
        RECT 1.000 370.920 1848.280 372.320 ;
        RECT 0.525 366.880 1848.280 370.920 ;
        RECT 1.000 365.480 1848.280 366.880 ;
        RECT 0.525 361.440 1848.280 365.480 ;
        RECT 1.000 360.040 1848.280 361.440 ;
        RECT 0.525 356.000 1848.280 360.040 ;
        RECT 1.000 354.600 1848.280 356.000 ;
        RECT 0.525 350.560 1848.280 354.600 ;
        RECT 1.000 349.160 1848.280 350.560 ;
        RECT 0.525 345.120 1848.280 349.160 ;
        RECT 1.000 343.720 1848.280 345.120 ;
        RECT 0.525 339.680 1848.280 343.720 ;
        RECT 1.000 338.280 1848.280 339.680 ;
        RECT 0.525 334.240 1848.280 338.280 ;
        RECT 1.000 332.840 1848.280 334.240 ;
        RECT 0.525 328.800 1848.280 332.840 ;
        RECT 1.000 327.400 1848.280 328.800 ;
        RECT 0.525 323.360 1848.280 327.400 ;
        RECT 1.000 321.960 1848.280 323.360 ;
        RECT 0.525 317.920 1848.280 321.960 ;
        RECT 1.000 316.520 1847.280 317.920 ;
        RECT 0.525 312.480 1848.280 316.520 ;
        RECT 1.000 311.080 1847.280 312.480 ;
        RECT 0.525 307.040 1848.280 311.080 ;
        RECT 1.000 305.640 1847.280 307.040 ;
        RECT 0.525 301.600 1848.280 305.640 ;
        RECT 1.000 300.200 1847.280 301.600 ;
        RECT 0.525 296.160 1848.280 300.200 ;
        RECT 1.000 294.760 1847.280 296.160 ;
        RECT 0.525 290.720 1848.280 294.760 ;
        RECT 1.000 289.320 1847.280 290.720 ;
        RECT 0.525 268.960 1848.280 289.320 ;
        RECT 1.000 267.560 1848.280 268.960 ;
        RECT 0.525 263.520 1848.280 267.560 ;
        RECT 1.000 262.120 1848.280 263.520 ;
        RECT 0.525 258.080 1848.280 262.120 ;
        RECT 1.000 256.680 1848.280 258.080 ;
        RECT 0.525 252.640 1848.280 256.680 ;
        RECT 1.000 251.240 1848.280 252.640 ;
        RECT 0.525 247.200 1848.280 251.240 ;
        RECT 1.000 245.800 1848.280 247.200 ;
        RECT 0.525 241.760 1848.280 245.800 ;
        RECT 1.000 240.360 1848.280 241.760 ;
        RECT 0.525 236.320 1848.280 240.360 ;
        RECT 1.000 234.920 1848.280 236.320 ;
        RECT 0.525 230.880 1848.280 234.920 ;
        RECT 1.000 229.480 1848.280 230.880 ;
        RECT 0.525 225.440 1848.280 229.480 ;
        RECT 1.000 224.040 1848.280 225.440 ;
        RECT 0.525 220.000 1848.280 224.040 ;
        RECT 1.000 218.600 1848.280 220.000 ;
        RECT 0.525 214.560 1848.280 218.600 ;
        RECT 1.000 213.160 1848.280 214.560 ;
        RECT 0.525 209.120 1848.280 213.160 ;
        RECT 1.000 207.720 1848.280 209.120 ;
        RECT 0.525 203.680 1848.280 207.720 ;
        RECT 1.000 202.280 1848.280 203.680 ;
        RECT 0.525 198.240 1848.280 202.280 ;
        RECT 1.000 196.840 1848.280 198.240 ;
        RECT 0.525 192.800 1848.280 196.840 ;
        RECT 1.000 191.400 1848.280 192.800 ;
        RECT 0.525 187.360 1848.280 191.400 ;
        RECT 1.000 185.960 1848.280 187.360 ;
        RECT 0.525 181.920 1848.280 185.960 ;
        RECT 1.000 180.520 1848.280 181.920 ;
        RECT 0.525 176.480 1848.280 180.520 ;
        RECT 1.000 175.080 1848.280 176.480 ;
        RECT 0.525 171.040 1848.280 175.080 ;
        RECT 1.000 169.640 1848.280 171.040 ;
        RECT 0.525 165.600 1848.280 169.640 ;
        RECT 1.000 164.200 1848.280 165.600 ;
        RECT 0.525 160.160 1848.280 164.200 ;
        RECT 1.000 158.760 1848.280 160.160 ;
        RECT 0.525 154.720 1848.280 158.760 ;
        RECT 1.000 153.320 1848.280 154.720 ;
        RECT 0.525 149.280 1848.280 153.320 ;
        RECT 1.000 147.880 1848.280 149.280 ;
        RECT 0.525 143.840 1848.280 147.880 ;
        RECT 1.000 142.440 1848.280 143.840 ;
        RECT 0.525 138.400 1848.280 142.440 ;
        RECT 1.000 137.000 1848.280 138.400 ;
        RECT 0.525 132.960 1848.280 137.000 ;
        RECT 1.000 131.560 1848.280 132.960 ;
        RECT 0.525 127.520 1848.280 131.560 ;
        RECT 1.000 126.120 1848.280 127.520 ;
        RECT 0.525 122.080 1848.280 126.120 ;
        RECT 1.000 120.680 1848.280 122.080 ;
        RECT 0.525 116.640 1848.280 120.680 ;
        RECT 1.000 115.240 1848.280 116.640 ;
        RECT 0.525 111.200 1848.280 115.240 ;
        RECT 1.000 109.800 1848.280 111.200 ;
        RECT 0.525 105.760 1848.280 109.800 ;
        RECT 1.000 104.360 1848.280 105.760 ;
        RECT 0.525 100.320 1848.280 104.360 ;
        RECT 1.000 98.920 1848.280 100.320 ;
        RECT 0.525 94.880 1848.280 98.920 ;
        RECT 1.000 93.480 1847.280 94.880 ;
        RECT 0.525 89.440 1848.280 93.480 ;
        RECT 1.000 88.040 1847.280 89.440 ;
        RECT 0.525 84.000 1848.280 88.040 ;
        RECT 1.000 82.600 1847.280 84.000 ;
        RECT 0.525 78.560 1848.280 82.600 ;
        RECT 1.000 77.160 1847.280 78.560 ;
        RECT 0.525 73.120 1848.280 77.160 ;
        RECT 1.000 71.720 1847.280 73.120 ;
        RECT 0.525 67.680 1848.280 71.720 ;
        RECT 1.000 66.280 1847.280 67.680 ;
        RECT 0.525 50.000 1848.280 66.280 ;
        RECT 1.000 6.440 1848.280 50.000 ;
        RECT 0.525 0.855 1848.280 6.440 ;
      LAYER met4 ;
        RECT 0.310 3.575 6.560 1406.065 ;
        RECT 8.960 3.575 11.860 1406.065 ;
        RECT 14.260 3.575 36.560 1406.065 ;
        RECT 38.960 3.575 41.860 1406.065 ;
        RECT 44.260 3.575 62.680 1406.065 ;
        RECT 65.080 3.575 67.980 1406.065 ;
        RECT 70.380 3.575 92.680 1406.065 ;
        RECT 95.080 3.575 97.980 1406.065 ;
        RECT 100.380 3.575 122.680 1406.065 ;
        RECT 125.080 3.575 127.980 1406.065 ;
        RECT 130.380 3.575 152.680 1406.065 ;
        RECT 155.080 3.575 157.980 1406.065 ;
        RECT 160.380 3.575 182.680 1406.065 ;
        RECT 185.080 3.575 187.980 1406.065 ;
        RECT 190.380 3.575 212.680 1406.065 ;
        RECT 215.080 3.575 217.980 1406.065 ;
        RECT 220.380 3.575 242.680 1406.065 ;
        RECT 245.080 3.575 247.980 1406.065 ;
        RECT 250.380 3.575 273.360 1406.065 ;
        RECT 275.760 3.575 278.660 1406.065 ;
        RECT 281.060 3.575 303.360 1406.065 ;
        RECT 305.760 3.575 308.660 1406.065 ;
        RECT 311.060 3.575 333.360 1406.065 ;
        RECT 335.760 3.575 338.660 1406.065 ;
        RECT 341.060 3.575 363.360 1406.065 ;
        RECT 365.760 3.575 368.660 1406.065 ;
        RECT 371.060 3.575 393.360 1406.065 ;
        RECT 395.760 3.575 398.660 1406.065 ;
        RECT 401.060 3.575 423.360 1406.065 ;
        RECT 425.760 3.575 428.660 1406.065 ;
        RECT 431.060 3.575 453.360 1406.065 ;
        RECT 455.760 3.575 458.660 1406.065 ;
        RECT 461.060 3.575 484.040 1406.065 ;
        RECT 486.440 3.575 489.340 1406.065 ;
        RECT 491.740 3.575 514.040 1406.065 ;
        RECT 516.440 3.575 519.340 1406.065 ;
        RECT 521.740 3.575 544.040 1406.065 ;
        RECT 546.440 3.575 549.340 1406.065 ;
        RECT 551.740 3.575 574.040 1406.065 ;
        RECT 576.440 3.575 579.340 1406.065 ;
        RECT 581.740 3.575 604.040 1406.065 ;
        RECT 606.440 3.575 609.340 1406.065 ;
        RECT 611.740 3.575 634.040 1406.065 ;
        RECT 636.440 3.575 639.340 1406.065 ;
        RECT 641.740 3.575 664.040 1406.065 ;
        RECT 666.440 3.575 669.340 1406.065 ;
        RECT 671.740 3.575 694.040 1406.065 ;
        RECT 696.440 3.575 699.340 1406.065 ;
        RECT 701.740 3.575 724.040 1406.065 ;
        RECT 726.440 3.575 736.120 1406.065 ;
        RECT 738.520 3.575 741.420 1406.065 ;
        RECT 743.820 3.575 766.120 1406.065 ;
        RECT 768.520 3.575 771.420 1406.065 ;
        RECT 773.820 3.575 796.120 1406.065 ;
        RECT 798.520 3.575 801.420 1406.065 ;
        RECT 803.820 3.575 826.120 1406.065 ;
        RECT 828.520 3.575 831.420 1406.065 ;
        RECT 833.820 3.575 856.120 1406.065 ;
        RECT 858.520 3.575 861.420 1406.065 ;
        RECT 863.820 3.575 886.120 1406.065 ;
        RECT 888.520 3.575 891.420 1406.065 ;
        RECT 893.820 3.575 916.120 1406.065 ;
        RECT 918.520 3.575 921.420 1406.065 ;
        RECT 923.820 3.575 946.800 1406.065 ;
        RECT 949.200 3.575 952.100 1406.065 ;
        RECT 954.500 3.575 976.800 1406.065 ;
        RECT 979.200 3.575 982.100 1406.065 ;
        RECT 984.500 3.575 1006.800 1406.065 ;
        RECT 1009.200 3.575 1012.100 1406.065 ;
        RECT 1014.500 3.575 1036.800 1406.065 ;
        RECT 1039.200 3.575 1042.100 1406.065 ;
        RECT 1044.500 3.575 1066.800 1406.065 ;
        RECT 1069.200 3.575 1072.100 1406.065 ;
        RECT 1074.500 3.575 1096.800 1406.065 ;
        RECT 1099.200 3.575 1102.100 1406.065 ;
        RECT 1104.500 3.575 1126.800 1406.065 ;
        RECT 1129.200 3.575 1132.100 1406.065 ;
        RECT 1134.500 3.575 1157.480 1406.065 ;
        RECT 1159.880 3.575 1162.780 1406.065 ;
        RECT 1165.180 3.575 1187.480 1406.065 ;
        RECT 1189.880 3.575 1192.780 1406.065 ;
        RECT 1195.180 3.575 1217.480 1406.065 ;
        RECT 1219.880 3.575 1222.780 1406.065 ;
        RECT 1225.180 3.575 1247.480 1406.065 ;
        RECT 1249.880 3.575 1252.780 1406.065 ;
        RECT 1255.180 3.575 1277.480 1406.065 ;
        RECT 1279.880 3.575 1282.780 1406.065 ;
        RECT 1285.180 3.575 1307.480 1406.065 ;
        RECT 1309.880 3.575 1312.780 1406.065 ;
        RECT 1315.180 3.575 1337.480 1406.065 ;
        RECT 1339.880 3.575 1342.780 1406.065 ;
        RECT 1345.180 3.575 1377.360 1406.065 ;
        RECT 1379.760 3.575 1382.660 1406.065 ;
        RECT 1385.060 3.575 1407.360 1406.065 ;
        RECT 1409.760 3.575 1412.660 1406.065 ;
        RECT 1415.060 3.575 1437.360 1406.065 ;
        RECT 1439.760 3.575 1442.660 1406.065 ;
        RECT 1445.060 3.575 1467.360 1406.065 ;
        RECT 1469.760 3.575 1472.660 1406.065 ;
        RECT 1475.060 3.575 1497.360 1406.065 ;
        RECT 1499.760 3.575 1502.660 1406.065 ;
        RECT 1505.060 3.575 1527.360 1406.065 ;
        RECT 1529.760 3.575 1532.660 1406.065 ;
        RECT 1535.060 3.575 1557.360 1406.065 ;
        RECT 1559.760 3.575 1562.660 1406.065 ;
        RECT 1565.060 3.575 1588.040 1406.065 ;
        RECT 1590.440 3.575 1593.340 1406.065 ;
        RECT 1595.740 3.575 1618.040 1406.065 ;
        RECT 1620.440 3.575 1623.340 1406.065 ;
        RECT 1625.740 3.575 1648.040 1406.065 ;
        RECT 1650.440 3.575 1653.340 1406.065 ;
        RECT 1655.740 3.575 1678.040 1406.065 ;
        RECT 1680.440 3.575 1683.340 1406.065 ;
        RECT 1685.740 3.575 1708.040 1406.065 ;
        RECT 1710.440 3.575 1713.340 1406.065 ;
        RECT 1715.740 3.575 1738.040 1406.065 ;
        RECT 1740.440 3.575 1743.340 1406.065 ;
        RECT 1745.740 3.575 1768.040 1406.065 ;
        RECT 1770.440 3.575 1773.340 1406.065 ;
        RECT 1775.740 3.575 1798.720 1406.065 ;
        RECT 1801.120 3.575 1804.020 1406.065 ;
        RECT 1806.420 3.575 1828.720 1406.065 ;
        RECT 1831.120 3.575 1834.020 1406.065 ;
        RECT 1836.420 3.575 1847.065 1406.065 ;
  END
END classic_fabric_chipfoundry_medium
END LIBRARY

